VERSION 5.8 ;
BUSBITCHARS "[]" ;
DIVIDERCHAR "/" ;
UNITS
    DATABASE MICRONS 1000 ;
END UNITS

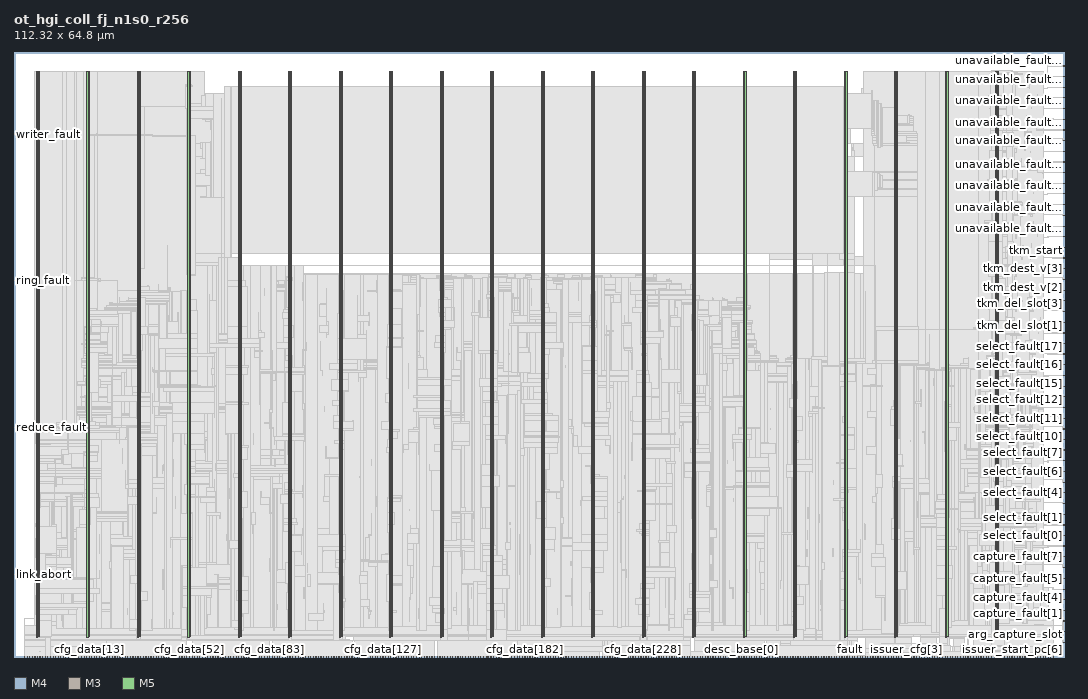
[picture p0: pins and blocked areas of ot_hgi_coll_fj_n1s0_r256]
MACRO ot_hgi_coll_fj_n1s0_r256
  FOREIGN ot_hgi_coll_fj_n1s0_r256 0 0 ;
  CLASS BLOCK ;
  SIZE 112.32 BY 64.8 ;
  PIN arg_capture_slot
    DIRECTION INPUT ;
    USE SIGNAL ;
    PORT
      LAYER M4 ;
        RECT  112.236 1.536 112.32 1.56 ;
    END
  END arg_capture_slot
  PIN capture_fault[0]
    DIRECTION INPUT ;
    USE SIGNAL ;
    PORT
      LAYER M4 ;
        RECT  112.236 2.688 112.32 2.712 ;
    END
  END capture_fault[0]
  PIN capture_fault[1]
    DIRECTION INPUT ;
    USE SIGNAL ;
    PORT
      LAYER M4 ;
        RECT  112.236 3.84 112.32 3.864 ;
    END
  END capture_fault[1]
  PIN capture_fault[2]
    DIRECTION INPUT ;
    USE SIGNAL ;
    PORT
      LAYER M4 ;
        RECT  112.236 4.992 112.32 5.016 ;
    END
  END capture_fault[2]
  PIN capture_fault[3]
    DIRECTION INPUT ;
    USE SIGNAL ;
    PORT
      LAYER M4 ;
        RECT  112.236 6.144 112.32 6.168 ;
    END
  END capture_fault[3]
  PIN capture_fault[4]
    DIRECTION INPUT ;
    USE SIGNAL ;
    PORT
      LAYER M4 ;
        RECT  112.236 7.248 112.32 7.272 ;
    END
  END capture_fault[4]
  PIN capture_fault[5]
    DIRECTION INPUT ;
    USE SIGNAL ;
    PORT
      LAYER M4 ;
        RECT  112.236 8.4 112.32 8.424 ;
    END
  END capture_fault[5]
  PIN capture_fault[6]
    DIRECTION INPUT ;
    USE SIGNAL ;
    PORT
      LAYER M4 ;
        RECT  112.236 9.552 112.32 9.576 ;
    END
  END capture_fault[6]
  PIN capture_fault[7]
    DIRECTION INPUT ;
    USE SIGNAL ;
    PORT
      LAYER M4 ;
        RECT  112.236 10.704 112.32 10.728 ;
    END
  END capture_fault[7]
  PIN cfg_addr[0]
    DIRECTION INPUT ;
    USE SIGNAL ;
    PORT
      LAYER M3 ;
        RECT  1.116 0 1.134 0.038 ;
    END
  END cfg_addr[0]
  PIN cfg_addr[10]
    DIRECTION INPUT ;
    USE SIGNAL ;
    PORT
      LAYER M3 ;
        RECT  3.888 0 3.906 0.038 ;
    END
  END cfg_addr[10]
  PIN cfg_addr[11]
    DIRECTION INPUT ;
    USE SIGNAL ;
    PORT
      LAYER M3 ;
        RECT  4.176 0 4.194 0.038 ;
    END
  END cfg_addr[11]
  PIN cfg_addr[1]
    DIRECTION INPUT ;
    USE SIGNAL ;
    PORT
      LAYER M3 ;
        RECT  1.404 0 1.422 0.038 ;
    END
  END cfg_addr[1]
  PIN cfg_addr[2]
    DIRECTION INPUT ;
    USE SIGNAL ;
    PORT
      LAYER M3 ;
        RECT  1.692 0 1.71 0.038 ;
    END
  END cfg_addr[2]
  PIN cfg_addr[3]
    DIRECTION INPUT ;
    USE SIGNAL ;
    PORT
      LAYER M3 ;
        RECT  1.944 0 1.962 0.038 ;
    END
  END cfg_addr[3]
  PIN cfg_addr[4]
    DIRECTION INPUT ;
    USE SIGNAL ;
    PORT
      LAYER M3 ;
        RECT  2.232 0 2.25 0.038 ;
    END
  END cfg_addr[4]
  PIN cfg_addr[5]
    DIRECTION INPUT ;
    USE SIGNAL ;
    PORT
      LAYER M3 ;
        RECT  2.52 0 2.538 0.038 ;
    END
  END cfg_addr[5]
  PIN cfg_addr[6]
    DIRECTION INPUT ;
    USE SIGNAL ;
    PORT
      LAYER M3 ;
        RECT  2.772 0 2.79 0.038 ;
    END
  END cfg_addr[6]
  PIN cfg_addr[7]
    DIRECTION INPUT ;
    USE SIGNAL ;
    PORT
      LAYER M3 ;
        RECT  3.06 0 3.078 0.038 ;
    END
  END cfg_addr[7]
  PIN cfg_addr[8]
    DIRECTION INPUT ;
    USE SIGNAL ;
    PORT
      LAYER M3 ;
        RECT  3.348 0 3.366 0.038 ;
    END
  END cfg_addr[8]
  PIN cfg_addr[9]
    DIRECTION INPUT ;
    USE SIGNAL ;
    PORT
      LAYER M3 ;
        RECT  3.6 0 3.618 0.038 ;
    END
  END cfg_addr[9]
  PIN cfg_data[0]
    DIRECTION INPUT ;
    USE SIGNAL ;
    PORT
      LAYER M3 ;
        RECT  4.428 0 4.446 0.038 ;
    END
  END cfg_data[0]
  PIN cfg_data[100]
    DIRECTION INPUT ;
    USE SIGNAL ;
    PORT
      LAYER M5 ;
        RECT  32.016 0 32.04 0.084 ;
    END
  END cfg_data[100]
  PIN cfg_data[101]
    DIRECTION INPUT ;
    USE SIGNAL ;
    PORT
      LAYER M5 ;
        RECT  32.304 0 32.328 0.084 ;
    END
  END cfg_data[101]
  PIN cfg_data[102]
    DIRECTION INPUT ;
    USE SIGNAL ;
    PORT
      LAYER M5 ;
        RECT  32.544 0 32.568 0.084 ;
    END
  END cfg_data[102]
  PIN cfg_data[103]
    DIRECTION INPUT ;
    USE SIGNAL ;
    PORT
      LAYER M5 ;
        RECT  32.832 0 32.856 0.084 ;
    END
  END cfg_data[103]
  PIN cfg_data[104]
    DIRECTION INPUT ;
    USE SIGNAL ;
    PORT
      LAYER M5 ;
        RECT  33.12 0 33.144 0.084 ;
    END
  END cfg_data[104]
  PIN cfg_data[105]
    DIRECTION INPUT ;
    USE SIGNAL ;
    PORT
      LAYER M5 ;
        RECT  33.408 0 33.432 0.084 ;
    END
  END cfg_data[105]
  PIN cfg_data[106]
    DIRECTION INPUT ;
    USE SIGNAL ;
    PORT
      LAYER M5 ;
        RECT  33.648 0 33.672 0.084 ;
    END
  END cfg_data[106]
  PIN cfg_data[107]
    DIRECTION INPUT ;
    USE SIGNAL ;
    PORT
      LAYER M5 ;
        RECT  33.936 0 33.96 0.084 ;
    END
  END cfg_data[107]
  PIN cfg_data[108]
    DIRECTION INPUT ;
    USE SIGNAL ;
    PORT
      LAYER M5 ;
        RECT  34.224 0 34.248 0.084 ;
    END
  END cfg_data[108]
  PIN cfg_data[109]
    DIRECTION INPUT ;
    USE SIGNAL ;
    PORT
      LAYER M5 ;
        RECT  34.512 0 34.536 0.084 ;
    END
  END cfg_data[109]
  PIN cfg_data[10]
    DIRECTION INPUT ;
    USE SIGNAL ;
    PORT
      LAYER M3 ;
        RECT  7.2 0 7.218 0.038 ;
    END
  END cfg_data[10]
  PIN cfg_data[110]
    DIRECTION INPUT ;
    USE SIGNAL ;
    PORT
      LAYER M5 ;
        RECT  34.752 0 34.776 0.084 ;
    END
  END cfg_data[110]
  PIN cfg_data[111]
    DIRECTION INPUT ;
    USE SIGNAL ;
    PORT
      LAYER M5 ;
        RECT  35.04 0 35.064 0.084 ;
    END
  END cfg_data[111]
  PIN cfg_data[112]
    DIRECTION INPUT ;
    USE SIGNAL ;
    PORT
      LAYER M5 ;
        RECT  35.328 0 35.352 0.084 ;
    END
  END cfg_data[112]
  PIN cfg_data[113]
    DIRECTION INPUT ;
    USE SIGNAL ;
    PORT
      LAYER M5 ;
        RECT  35.616 0 35.64 0.084 ;
    END
  END cfg_data[113]
  PIN cfg_data[114]
    DIRECTION INPUT ;
    USE SIGNAL ;
    PORT
      LAYER M5 ;
        RECT  35.856 0 35.88 0.084 ;
    END
  END cfg_data[114]
  PIN cfg_data[115]
    DIRECTION INPUT ;
    USE SIGNAL ;
    PORT
      LAYER M5 ;
        RECT  36.144 0 36.168 0.084 ;
    END
  END cfg_data[115]
  PIN cfg_data[116]
    DIRECTION INPUT ;
    USE SIGNAL ;
    PORT
      LAYER M3 ;
        RECT  36.432 0 36.45 0.038 ;
    END
  END cfg_data[116]
  PIN cfg_data[117]
    DIRECTION INPUT ;
    USE SIGNAL ;
    PORT
      LAYER M3 ;
        RECT  36.72 0 36.738 0.038 ;
    END
  END cfg_data[117]
  PIN cfg_data[118]
    DIRECTION INPUT ;
    USE SIGNAL ;
    PORT
      LAYER M3 ;
        RECT  36.972 0 36.99 0.038 ;
    END
  END cfg_data[118]
  PIN cfg_data[119]
    DIRECTION INPUT ;
    USE SIGNAL ;
    PORT
      LAYER M3 ;
        RECT  37.26 0 37.278 0.038 ;
    END
  END cfg_data[119]
  PIN cfg_data[11]
    DIRECTION INPUT ;
    USE SIGNAL ;
    PORT
      LAYER M3 ;
        RECT  7.488 0 7.506 0.038 ;
    END
  END cfg_data[11]
  PIN cfg_data[120]
    DIRECTION INPUT ;
    USE SIGNAL ;
    PORT
      LAYER M3 ;
        RECT  37.548 0 37.566 0.038 ;
    END
  END cfg_data[120]
  PIN cfg_data[121]
    DIRECTION INPUT ;
    USE SIGNAL ;
    PORT
      LAYER M3 ;
        RECT  37.8 0 37.818 0.038 ;
    END
  END cfg_data[121]
  PIN cfg_data[122]
    DIRECTION INPUT ;
    USE SIGNAL ;
    PORT
      LAYER M3 ;
        RECT  38.088 0 38.106 0.038 ;
    END
  END cfg_data[122]
  PIN cfg_data[123]
    DIRECTION INPUT ;
    USE SIGNAL ;
    PORT
      LAYER M3 ;
        RECT  38.376 0 38.394 0.038 ;
    END
  END cfg_data[123]
  PIN cfg_data[124]
    DIRECTION INPUT ;
    USE SIGNAL ;
    PORT
      LAYER M3 ;
        RECT  38.628 0 38.646 0.038 ;
    END
  END cfg_data[124]
  PIN cfg_data[125]
    DIRECTION INPUT ;
    USE SIGNAL ;
    PORT
      LAYER M3 ;
        RECT  38.916 0 38.934 0.038 ;
    END
  END cfg_data[125]
  PIN cfg_data[126]
    DIRECTION INPUT ;
    USE SIGNAL ;
    PORT
      LAYER M3 ;
        RECT  39.204 0 39.222 0.038 ;
    END
  END cfg_data[126]
  PIN cfg_data[127]
    DIRECTION INPUT ;
    USE SIGNAL ;
    PORT
      LAYER M3 ;
        RECT  39.456 0 39.474 0.038 ;
    END
  END cfg_data[127]
  PIN cfg_data[128]
    DIRECTION INPUT ;
    USE SIGNAL ;
    PORT
      LAYER M3 ;
        RECT  39.744 0 39.762 0.038 ;
    END
  END cfg_data[128]
  PIN cfg_data[129]
    DIRECTION INPUT ;
    USE SIGNAL ;
    PORT
      LAYER M3 ;
        RECT  40.032 0 40.05 0.038 ;
    END
  END cfg_data[129]
  PIN cfg_data[12]
    DIRECTION INPUT ;
    USE SIGNAL ;
    PORT
      LAYER M3 ;
        RECT  7.74 0 7.758 0.038 ;
    END
  END cfg_data[12]
  PIN cfg_data[130]
    DIRECTION INPUT ;
    USE SIGNAL ;
    PORT
      LAYER M3 ;
        RECT  40.284 0 40.302 0.038 ;
    END
  END cfg_data[130]
  PIN cfg_data[131]
    DIRECTION INPUT ;
    USE SIGNAL ;
    PORT
      LAYER M3 ;
        RECT  40.572 0 40.59 0.038 ;
    END
  END cfg_data[131]
  PIN cfg_data[132]
    DIRECTION INPUT ;
    USE SIGNAL ;
    PORT
      LAYER M3 ;
        RECT  40.86 0 40.878 0.038 ;
    END
  END cfg_data[132]
  PIN cfg_data[133]
    DIRECTION INPUT ;
    USE SIGNAL ;
    PORT
      LAYER M3 ;
        RECT  41.112 0 41.13 0.038 ;
    END
  END cfg_data[133]
  PIN cfg_data[134]
    DIRECTION INPUT ;
    USE SIGNAL ;
    PORT
      LAYER M3 ;
        RECT  41.4 0 41.418 0.038 ;
    END
  END cfg_data[134]
  PIN cfg_data[135]
    DIRECTION INPUT ;
    USE SIGNAL ;
    PORT
      LAYER M3 ;
        RECT  41.688 0 41.706 0.038 ;
    END
  END cfg_data[135]
  PIN cfg_data[136]
    DIRECTION INPUT ;
    USE SIGNAL ;
    PORT
      LAYER M3 ;
        RECT  41.94 0 41.958 0.038 ;
    END
  END cfg_data[136]
  PIN cfg_data[137]
    DIRECTION INPUT ;
    USE SIGNAL ;
    PORT
      LAYER M3 ;
        RECT  42.228 0 42.246 0.038 ;
    END
  END cfg_data[137]
  PIN cfg_data[138]
    DIRECTION INPUT ;
    USE SIGNAL ;
    PORT
      LAYER M3 ;
        RECT  42.516 0 42.534 0.038 ;
    END
  END cfg_data[138]
  PIN cfg_data[139]
    DIRECTION INPUT ;
    USE SIGNAL ;
    PORT
      LAYER M3 ;
        RECT  42.768 0 42.786 0.038 ;
    END
  END cfg_data[139]
  PIN cfg_data[13]
    DIRECTION INPUT ;
    USE SIGNAL ;
    PORT
      LAYER M3 ;
        RECT  8.028 0 8.046 0.038 ;
    END
  END cfg_data[13]
  PIN cfg_data[140]
    DIRECTION INPUT ;
    USE SIGNAL ;
    PORT
      LAYER M3 ;
        RECT  43.056 0 43.074 0.038 ;
    END
  END cfg_data[140]
  PIN cfg_data[141]
    DIRECTION INPUT ;
    USE SIGNAL ;
    PORT
      LAYER M3 ;
        RECT  43.344 0 43.362 0.038 ;
    END
  END cfg_data[141]
  PIN cfg_data[142]
    DIRECTION INPUT ;
    USE SIGNAL ;
    PORT
      LAYER M3 ;
        RECT  43.596 0 43.614 0.038 ;
    END
  END cfg_data[142]
  PIN cfg_data[143]
    DIRECTION INPUT ;
    USE SIGNAL ;
    PORT
      LAYER M3 ;
        RECT  43.884 0 43.902 0.038 ;
    END
  END cfg_data[143]
  PIN cfg_data[144]
    DIRECTION INPUT ;
    USE SIGNAL ;
    PORT
      LAYER M3 ;
        RECT  44.172 0 44.19 0.038 ;
    END
  END cfg_data[144]
  PIN cfg_data[145]
    DIRECTION INPUT ;
    USE SIGNAL ;
    PORT
      LAYER M3 ;
        RECT  44.424 0 44.442 0.038 ;
    END
  END cfg_data[145]
  PIN cfg_data[146]
    DIRECTION INPUT ;
    USE SIGNAL ;
    PORT
      LAYER M3 ;
        RECT  44.712 0 44.73 0.038 ;
    END
  END cfg_data[146]
  PIN cfg_data[147]
    DIRECTION INPUT ;
    USE SIGNAL ;
    PORT
      LAYER M3 ;
        RECT  44.964 0 44.982 0.038 ;
    END
  END cfg_data[147]
  PIN cfg_data[148]
    DIRECTION INPUT ;
    USE SIGNAL ;
    PORT
      LAYER M5 ;
        RECT  45.264 0 45.288 0.084 ;
    END
  END cfg_data[148]
  PIN cfg_data[149]
    DIRECTION INPUT ;
    USE SIGNAL ;
    PORT
      LAYER M5 ;
        RECT  45.552 0 45.576 0.084 ;
    END
  END cfg_data[149]
  PIN cfg_data[14]
    DIRECTION INPUT ;
    USE SIGNAL ;
    PORT
      LAYER M3 ;
        RECT  8.316 0 8.334 0.038 ;
    END
  END cfg_data[14]
  PIN cfg_data[150]
    DIRECTION INPUT ;
    USE SIGNAL ;
    PORT
      LAYER M5 ;
        RECT  45.792 0 45.816 0.084 ;
    END
  END cfg_data[150]
  PIN cfg_data[151]
    DIRECTION INPUT ;
    USE SIGNAL ;
    PORT
      LAYER M5 ;
        RECT  46.08 0 46.104 0.084 ;
    END
  END cfg_data[151]
  PIN cfg_data[152]
    DIRECTION INPUT ;
    USE SIGNAL ;
    PORT
      LAYER M5 ;
        RECT  46.368 0 46.392 0.084 ;
    END
  END cfg_data[152]
  PIN cfg_data[153]
    DIRECTION INPUT ;
    USE SIGNAL ;
    PORT
      LAYER M5 ;
        RECT  46.656 0 46.68 0.084 ;
    END
  END cfg_data[153]
  PIN cfg_data[154]
    DIRECTION INPUT ;
    USE SIGNAL ;
    PORT
      LAYER M5 ;
        RECT  46.896 0 46.92 0.084 ;
    END
  END cfg_data[154]
  PIN cfg_data[155]
    DIRECTION INPUT ;
    USE SIGNAL ;
    PORT
      LAYER M5 ;
        RECT  47.184 0 47.208 0.084 ;
    END
  END cfg_data[155]
  PIN cfg_data[156]
    DIRECTION INPUT ;
    USE SIGNAL ;
    PORT
      LAYER M5 ;
        RECT  47.472 0 47.496 0.084 ;
    END
  END cfg_data[156]
  PIN cfg_data[157]
    DIRECTION INPUT ;
    USE SIGNAL ;
    PORT
      LAYER M5 ;
        RECT  47.76 0 47.784 0.084 ;
    END
  END cfg_data[157]
  PIN cfg_data[158]
    DIRECTION INPUT ;
    USE SIGNAL ;
    PORT
      LAYER M5 ;
        RECT  48 0 48.024 0.084 ;
    END
  END cfg_data[158]
  PIN cfg_data[159]
    DIRECTION INPUT ;
    USE SIGNAL ;
    PORT
      LAYER M5 ;
        RECT  48.288 0 48.312 0.084 ;
    END
  END cfg_data[159]
  PIN cfg_data[15]
    DIRECTION INPUT ;
    USE SIGNAL ;
    PORT
      LAYER M3 ;
        RECT  8.568 0 8.586 0.038 ;
    END
  END cfg_data[15]
  PIN cfg_data[160]
    DIRECTION INPUT ;
    USE SIGNAL ;
    PORT
      LAYER M5 ;
        RECT  48.576 0 48.6 0.084 ;
    END
  END cfg_data[160]
  PIN cfg_data[161]
    DIRECTION INPUT ;
    USE SIGNAL ;
    PORT
      LAYER M5 ;
        RECT  48.816 0 48.84 0.084 ;
    END
  END cfg_data[161]
  PIN cfg_data[162]
    DIRECTION INPUT ;
    USE SIGNAL ;
    PORT
      LAYER M5 ;
        RECT  49.104 0 49.128 0.084 ;
    END
  END cfg_data[162]
  PIN cfg_data[163]
    DIRECTION INPUT ;
    USE SIGNAL ;
    PORT
      LAYER M5 ;
        RECT  49.392 0 49.416 0.084 ;
    END
  END cfg_data[163]
  PIN cfg_data[164]
    DIRECTION INPUT ;
    USE SIGNAL ;
    PORT
      LAYER M5 ;
        RECT  49.68 0 49.704 0.084 ;
    END
  END cfg_data[164]
  PIN cfg_data[165]
    DIRECTION INPUT ;
    USE SIGNAL ;
    PORT
      LAYER M5 ;
        RECT  49.92 0 49.944 0.084 ;
    END
  END cfg_data[165]
  PIN cfg_data[166]
    DIRECTION INPUT ;
    USE SIGNAL ;
    PORT
      LAYER M5 ;
        RECT  50.208 0 50.232 0.084 ;
    END
  END cfg_data[166]
  PIN cfg_data[167]
    DIRECTION INPUT ;
    USE SIGNAL ;
    PORT
      LAYER M5 ;
        RECT  50.496 0 50.52 0.084 ;
    END
  END cfg_data[167]
  PIN cfg_data[168]
    DIRECTION INPUT ;
    USE SIGNAL ;
    PORT
      LAYER M5 ;
        RECT  50.784 0 50.808 0.084 ;
    END
  END cfg_data[168]
  PIN cfg_data[169]
    DIRECTION INPUT ;
    USE SIGNAL ;
    PORT
      LAYER M5 ;
        RECT  51.024 0 51.048 0.084 ;
    END
  END cfg_data[169]
  PIN cfg_data[16]
    DIRECTION INPUT ;
    USE SIGNAL ;
    PORT
      LAYER M3 ;
        RECT  8.856 0 8.874 0.038 ;
    END
  END cfg_data[16]
  PIN cfg_data[170]
    DIRECTION INPUT ;
    USE SIGNAL ;
    PORT
      LAYER M5 ;
        RECT  51.312 0 51.336 0.084 ;
    END
  END cfg_data[170]
  PIN cfg_data[171]
    DIRECTION INPUT ;
    USE SIGNAL ;
    PORT
      LAYER M5 ;
        RECT  51.6 0 51.624 0.084 ;
    END
  END cfg_data[171]
  PIN cfg_data[172]
    DIRECTION INPUT ;
    USE SIGNAL ;
    PORT
      LAYER M5 ;
        RECT  51.888 0 51.912 0.084 ;
    END
  END cfg_data[172]
  PIN cfg_data[173]
    DIRECTION INPUT ;
    USE SIGNAL ;
    PORT
      LAYER M5 ;
        RECT  52.128 0 52.152 0.084 ;
    END
  END cfg_data[173]
  PIN cfg_data[174]
    DIRECTION INPUT ;
    USE SIGNAL ;
    PORT
      LAYER M5 ;
        RECT  52.416 0 52.44 0.084 ;
    END
  END cfg_data[174]
  PIN cfg_data[175]
    DIRECTION INPUT ;
    USE SIGNAL ;
    PORT
      LAYER M5 ;
        RECT  52.704 0 52.728 0.084 ;
    END
  END cfg_data[175]
  PIN cfg_data[176]
    DIRECTION INPUT ;
    USE SIGNAL ;
    PORT
      LAYER M5 ;
        RECT  52.992 0 53.016 0.084 ;
    END
  END cfg_data[176]
  PIN cfg_data[177]
    DIRECTION INPUT ;
    USE SIGNAL ;
    PORT
      LAYER M5 ;
        RECT  53.232 0 53.256 0.084 ;
    END
  END cfg_data[177]
  PIN cfg_data[178]
    DIRECTION INPUT ;
    USE SIGNAL ;
    PORT
      LAYER M5 ;
        RECT  53.52 0 53.544 0.084 ;
    END
  END cfg_data[178]
  PIN cfg_data[179]
    DIRECTION INPUT ;
    USE SIGNAL ;
    PORT
      LAYER M5 ;
        RECT  53.808 0 53.832 0.084 ;
    END
  END cfg_data[179]
  PIN cfg_data[17]
    DIRECTION INPUT ;
    USE SIGNAL ;
    PORT
      LAYER M3 ;
        RECT  9.144 0 9.162 0.038 ;
    END
  END cfg_data[17]
  PIN cfg_data[180]
    DIRECTION INPUT ;
    USE SIGNAL ;
    PORT
      LAYER M3 ;
        RECT  54.072 0 54.09 0.038 ;
    END
  END cfg_data[180]
  PIN cfg_data[181]
    DIRECTION INPUT ;
    USE SIGNAL ;
    PORT
      LAYER M3 ;
        RECT  54.36 0 54.378 0.038 ;
    END
  END cfg_data[181]
  PIN cfg_data[182]
    DIRECTION INPUT ;
    USE SIGNAL ;
    PORT
      LAYER M3 ;
        RECT  54.648 0 54.666 0.038 ;
    END
  END cfg_data[182]
  PIN cfg_data[183]
    DIRECTION INPUT ;
    USE SIGNAL ;
    PORT
      LAYER M3 ;
        RECT  54.9 0 54.918 0.038 ;
    END
  END cfg_data[183]
  PIN cfg_data[184]
    DIRECTION INPUT ;
    USE SIGNAL ;
    PORT
      LAYER M3 ;
        RECT  55.188 0 55.206 0.038 ;
    END
  END cfg_data[184]
  PIN cfg_data[185]
    DIRECTION INPUT ;
    USE SIGNAL ;
    PORT
      LAYER M3 ;
        RECT  55.476 0 55.494 0.038 ;
    END
  END cfg_data[185]
  PIN cfg_data[186]
    DIRECTION INPUT ;
    USE SIGNAL ;
    PORT
      LAYER M3 ;
        RECT  55.728 0 55.746 0.038 ;
    END
  END cfg_data[186]
  PIN cfg_data[187]
    DIRECTION INPUT ;
    USE SIGNAL ;
    PORT
      LAYER M3 ;
        RECT  56.016 0 56.034 0.038 ;
    END
  END cfg_data[187]
  PIN cfg_data[188]
    DIRECTION INPUT ;
    USE SIGNAL ;
    PORT
      LAYER M3 ;
        RECT  56.304 0 56.322 0.038 ;
    END
  END cfg_data[188]
  PIN cfg_data[189]
    DIRECTION INPUT ;
    USE SIGNAL ;
    PORT
      LAYER M3 ;
        RECT  56.556 0 56.574 0.038 ;
    END
  END cfg_data[189]
  PIN cfg_data[18]
    DIRECTION INPUT ;
    USE SIGNAL ;
    PORT
      LAYER M3 ;
        RECT  9.396 0 9.414 0.038 ;
    END
  END cfg_data[18]
  PIN cfg_data[190]
    DIRECTION INPUT ;
    USE SIGNAL ;
    PORT
      LAYER M3 ;
        RECT  56.844 0 56.862 0.038 ;
    END
  END cfg_data[190]
  PIN cfg_data[191]
    DIRECTION INPUT ;
    USE SIGNAL ;
    PORT
      LAYER M3 ;
        RECT  57.132 0 57.15 0.038 ;
    END
  END cfg_data[191]
  PIN cfg_data[192]
    DIRECTION INPUT ;
    USE SIGNAL ;
    PORT
      LAYER M3 ;
        RECT  57.384 0 57.402 0.038 ;
    END
  END cfg_data[192]
  PIN cfg_data[193]
    DIRECTION INPUT ;
    USE SIGNAL ;
    PORT
      LAYER M3 ;
        RECT  57.672 0 57.69 0.038 ;
    END
  END cfg_data[193]
  PIN cfg_data[194]
    DIRECTION INPUT ;
    USE SIGNAL ;
    PORT
      LAYER M3 ;
        RECT  57.96 0 57.978 0.038 ;
    END
  END cfg_data[194]
  PIN cfg_data[195]
    DIRECTION INPUT ;
    USE SIGNAL ;
    PORT
      LAYER M3 ;
        RECT  58.212 0 58.23 0.038 ;
    END
  END cfg_data[195]
  PIN cfg_data[196]
    DIRECTION INPUT ;
    USE SIGNAL ;
    PORT
      LAYER M3 ;
        RECT  58.5 0 58.518 0.038 ;
    END
  END cfg_data[196]
  PIN cfg_data[197]
    DIRECTION INPUT ;
    USE SIGNAL ;
    PORT
      LAYER M3 ;
        RECT  58.788 0 58.806 0.038 ;
    END
  END cfg_data[197]
  PIN cfg_data[198]
    DIRECTION INPUT ;
    USE SIGNAL ;
    PORT
      LAYER M3 ;
        RECT  59.04 0 59.058 0.038 ;
    END
  END cfg_data[198]
  PIN cfg_data[199]
    DIRECTION INPUT ;
    USE SIGNAL ;
    PORT
      LAYER M3 ;
        RECT  59.328 0 59.346 0.038 ;
    END
  END cfg_data[199]
  PIN cfg_data[19]
    DIRECTION INPUT ;
    USE SIGNAL ;
    PORT
      LAYER M3 ;
        RECT  9.684 0 9.702 0.038 ;
    END
  END cfg_data[19]
  PIN cfg_data[1]
    DIRECTION INPUT ;
    USE SIGNAL ;
    PORT
      LAYER M3 ;
        RECT  4.716 0 4.734 0.038 ;
    END
  END cfg_data[1]
  PIN cfg_data[200]
    DIRECTION INPUT ;
    USE SIGNAL ;
    PORT
      LAYER M3 ;
        RECT  59.616 0 59.634 0.038 ;
    END
  END cfg_data[200]
  PIN cfg_data[201]
    DIRECTION INPUT ;
    USE SIGNAL ;
    PORT
      LAYER M3 ;
        RECT  59.868 0 59.886 0.038 ;
    END
  END cfg_data[201]
  PIN cfg_data[202]
    DIRECTION INPUT ;
    USE SIGNAL ;
    PORT
      LAYER M3 ;
        RECT  60.156 0 60.174 0.038 ;
    END
  END cfg_data[202]
  PIN cfg_data[203]
    DIRECTION INPUT ;
    USE SIGNAL ;
    PORT
      LAYER M3 ;
        RECT  60.444 0 60.462 0.038 ;
    END
  END cfg_data[203]
  PIN cfg_data[204]
    DIRECTION INPUT ;
    USE SIGNAL ;
    PORT
      LAYER M3 ;
        RECT  60.696 0 60.714 0.038 ;
    END
  END cfg_data[204]
  PIN cfg_data[205]
    DIRECTION INPUT ;
    USE SIGNAL ;
    PORT
      LAYER M3 ;
        RECT  60.984 0 61.002 0.038 ;
    END
  END cfg_data[205]
  PIN cfg_data[206]
    DIRECTION INPUT ;
    USE SIGNAL ;
    PORT
      LAYER M3 ;
        RECT  61.236 0 61.254 0.038 ;
    END
  END cfg_data[206]
  PIN cfg_data[207]
    DIRECTION INPUT ;
    USE SIGNAL ;
    PORT
      LAYER M3 ;
        RECT  61.524 0 61.542 0.038 ;
    END
  END cfg_data[207]
  PIN cfg_data[208]
    DIRECTION INPUT ;
    USE SIGNAL ;
    PORT
      LAYER M3 ;
        RECT  61.812 0 61.83 0.038 ;
    END
  END cfg_data[208]
  PIN cfg_data[209]
    DIRECTION INPUT ;
    USE SIGNAL ;
    PORT
      LAYER M3 ;
        RECT  62.064 0 62.082 0.038 ;
    END
  END cfg_data[209]
  PIN cfg_data[20]
    DIRECTION INPUT ;
    USE SIGNAL ;
    PORT
      LAYER M5 ;
        RECT  9.936 0 9.96 0.084 ;
    END
  END cfg_data[20]
  PIN cfg_data[210]
    DIRECTION INPUT ;
    USE SIGNAL ;
    PORT
      LAYER M3 ;
        RECT  62.352 0 62.37 0.038 ;
    END
  END cfg_data[210]
  PIN cfg_data[211]
    DIRECTION INPUT ;
    USE SIGNAL ;
    PORT
      LAYER M3 ;
        RECT  62.64 0 62.658 0.038 ;
    END
  END cfg_data[211]
  PIN cfg_data[212]
    DIRECTION INPUT ;
    USE SIGNAL ;
    PORT
      LAYER M5 ;
        RECT  62.928 0 62.952 0.084 ;
    END
  END cfg_data[212]
  PIN cfg_data[213]
    DIRECTION INPUT ;
    USE SIGNAL ;
    PORT
      LAYER M5 ;
        RECT  63.168 0 63.192 0.084 ;
    END
  END cfg_data[213]
  PIN cfg_data[214]
    DIRECTION INPUT ;
    USE SIGNAL ;
    PORT
      LAYER M5 ;
        RECT  63.456 0 63.48 0.084 ;
    END
  END cfg_data[214]
  PIN cfg_data[215]
    DIRECTION INPUT ;
    USE SIGNAL ;
    PORT
      LAYER M5 ;
        RECT  63.744 0 63.768 0.084 ;
    END
  END cfg_data[215]
  PIN cfg_data[216]
    DIRECTION INPUT ;
    USE SIGNAL ;
    PORT
      LAYER M5 ;
        RECT  64.032 0 64.056 0.084 ;
    END
  END cfg_data[216]
  PIN cfg_data[217]
    DIRECTION INPUT ;
    USE SIGNAL ;
    PORT
      LAYER M5 ;
        RECT  64.272 0 64.296 0.084 ;
    END
  END cfg_data[217]
  PIN cfg_data[218]
    DIRECTION INPUT ;
    USE SIGNAL ;
    PORT
      LAYER M5 ;
        RECT  64.56 0 64.584 0.084 ;
    END
  END cfg_data[218]
  PIN cfg_data[219]
    DIRECTION INPUT ;
    USE SIGNAL ;
    PORT
      LAYER M5 ;
        RECT  64.848 0 64.872 0.084 ;
    END
  END cfg_data[219]
  PIN cfg_data[21]
    DIRECTION INPUT ;
    USE SIGNAL ;
    PORT
      LAYER M5 ;
        RECT  10.224 0 10.248 0.084 ;
    END
  END cfg_data[21]
  PIN cfg_data[220]
    DIRECTION INPUT ;
    USE SIGNAL ;
    PORT
      LAYER M5 ;
        RECT  65.088 0 65.112 0.084 ;
    END
  END cfg_data[220]
  PIN cfg_data[221]
    DIRECTION INPUT ;
    USE SIGNAL ;
    PORT
      LAYER M5 ;
        RECT  65.376 0 65.4 0.084 ;
    END
  END cfg_data[221]
  PIN cfg_data[222]
    DIRECTION INPUT ;
    USE SIGNAL ;
    PORT
      LAYER M5 ;
        RECT  65.664 0 65.688 0.084 ;
    END
  END cfg_data[222]
  PIN cfg_data[223]
    DIRECTION INPUT ;
    USE SIGNAL ;
    PORT
      LAYER M5 ;
        RECT  65.952 0 65.976 0.084 ;
    END
  END cfg_data[223]
  PIN cfg_data[224]
    DIRECTION INPUT ;
    USE SIGNAL ;
    PORT
      LAYER M5 ;
        RECT  66.192 0 66.216 0.084 ;
    END
  END cfg_data[224]
  PIN cfg_data[225]
    DIRECTION INPUT ;
    USE SIGNAL ;
    PORT
      LAYER M5 ;
        RECT  66.48 0 66.504 0.084 ;
    END
  END cfg_data[225]
  PIN cfg_data[226]
    DIRECTION INPUT ;
    USE SIGNAL ;
    PORT
      LAYER M5 ;
        RECT  66.768 0 66.792 0.084 ;
    END
  END cfg_data[226]
  PIN cfg_data[227]
    DIRECTION INPUT ;
    USE SIGNAL ;
    PORT
      LAYER M5 ;
        RECT  67.056 0 67.08 0.084 ;
    END
  END cfg_data[227]
  PIN cfg_data[228]
    DIRECTION INPUT ;
    USE SIGNAL ;
    PORT
      LAYER M5 ;
        RECT  67.296 0 67.32 0.084 ;
    END
  END cfg_data[228]
  PIN cfg_data[229]
    DIRECTION INPUT ;
    USE SIGNAL ;
    PORT
      LAYER M5 ;
        RECT  67.584 0 67.608 0.084 ;
    END
  END cfg_data[229]
  PIN cfg_data[22]
    DIRECTION INPUT ;
    USE SIGNAL ;
    PORT
      LAYER M5 ;
        RECT  10.512 0 10.536 0.084 ;
    END
  END cfg_data[22]
  PIN cfg_data[230]
    DIRECTION INPUT ;
    USE SIGNAL ;
    PORT
      LAYER M5 ;
        RECT  67.872 0 67.896 0.084 ;
    END
  END cfg_data[230]
  PIN cfg_data[231]
    DIRECTION INPUT ;
    USE SIGNAL ;
    PORT
      LAYER M5 ;
        RECT  68.16 0 68.184 0.084 ;
    END
  END cfg_data[231]
  PIN cfg_data[232]
    DIRECTION INPUT ;
    USE SIGNAL ;
    PORT
      LAYER M5 ;
        RECT  68.4 0 68.424 0.084 ;
    END
  END cfg_data[232]
  PIN cfg_data[233]
    DIRECTION INPUT ;
    USE SIGNAL ;
    PORT
      LAYER M5 ;
        RECT  68.688 0 68.712 0.084 ;
    END
  END cfg_data[233]
  PIN cfg_data[234]
    DIRECTION INPUT ;
    USE SIGNAL ;
    PORT
      LAYER M5 ;
        RECT  68.976 0 69 0.084 ;
    END
  END cfg_data[234]
  PIN cfg_data[235]
    DIRECTION INPUT ;
    USE SIGNAL ;
    PORT
      LAYER M5 ;
        RECT  69.264 0 69.288 0.084 ;
    END
  END cfg_data[235]
  PIN cfg_data[236]
    DIRECTION INPUT ;
    USE SIGNAL ;
    PORT
      LAYER M5 ;
        RECT  69.504 0 69.528 0.084 ;
    END
  END cfg_data[236]
  PIN cfg_data[237]
    DIRECTION INPUT ;
    USE SIGNAL ;
    PORT
      LAYER M5 ;
        RECT  69.792 0 69.816 0.084 ;
    END
  END cfg_data[237]
  PIN cfg_data[238]
    DIRECTION INPUT ;
    USE SIGNAL ;
    PORT
      LAYER M5 ;
        RECT  70.08 0 70.104 0.084 ;
    END
  END cfg_data[238]
  PIN cfg_data[239]
    DIRECTION INPUT ;
    USE SIGNAL ;
    PORT
      LAYER M5 ;
        RECT  70.368 0 70.392 0.084 ;
    END
  END cfg_data[239]
  PIN cfg_data[23]
    DIRECTION INPUT ;
    USE SIGNAL ;
    PORT
      LAYER M5 ;
        RECT  10.8 0 10.824 0.084 ;
    END
  END cfg_data[23]
  PIN cfg_data[240]
    DIRECTION INPUT ;
    USE SIGNAL ;
    PORT
      LAYER M5 ;
        RECT  70.608 0 70.632 0.084 ;
    END
  END cfg_data[240]
  PIN cfg_data[241]
    DIRECTION INPUT ;
    USE SIGNAL ;
    PORT
      LAYER M5 ;
        RECT  70.896 0 70.92 0.084 ;
    END
  END cfg_data[241]
  PIN cfg_data[242]
    DIRECTION INPUT ;
    USE SIGNAL ;
    PORT
      LAYER M5 ;
        RECT  71.184 0 71.208 0.084 ;
    END
  END cfg_data[242]
  PIN cfg_data[243]
    DIRECTION INPUT ;
    USE SIGNAL ;
    PORT
      LAYER M5 ;
        RECT  71.472 0 71.496 0.084 ;
    END
  END cfg_data[243]
  PIN cfg_data[244]
    DIRECTION INPUT ;
    USE SIGNAL ;
    PORT
      LAYER M3 ;
        RECT  71.748 0 71.766 0.038 ;
    END
  END cfg_data[244]
  PIN cfg_data[245]
    DIRECTION INPUT ;
    USE SIGNAL ;
    PORT
      LAYER M3 ;
        RECT  72 0 72.018 0.038 ;
    END
  END cfg_data[245]
  PIN cfg_data[246]
    DIRECTION INPUT ;
    USE SIGNAL ;
    PORT
      LAYER M3 ;
        RECT  72.288 0 72.306 0.038 ;
    END
  END cfg_data[246]
  PIN cfg_data[247]
    DIRECTION INPUT ;
    USE SIGNAL ;
    PORT
      LAYER M3 ;
        RECT  72.576 0 72.594 0.038 ;
    END
  END cfg_data[247]
  PIN cfg_data[248]
    DIRECTION INPUT ;
    USE SIGNAL ;
    PORT
      LAYER M3 ;
        RECT  72.828 0 72.846 0.038 ;
    END
  END cfg_data[248]
  PIN cfg_data[249]
    DIRECTION INPUT ;
    USE SIGNAL ;
    PORT
      LAYER M3 ;
        RECT  73.116 0 73.134 0.038 ;
    END
  END cfg_data[249]
  PIN cfg_data[24]
    DIRECTION INPUT ;
    USE SIGNAL ;
    PORT
      LAYER M5 ;
        RECT  11.04 0 11.064 0.084 ;
    END
  END cfg_data[24]
  PIN cfg_data[250]
    DIRECTION INPUT ;
    USE SIGNAL ;
    PORT
      LAYER M3 ;
        RECT  73.404 0 73.422 0.038 ;
    END
  END cfg_data[250]
  PIN cfg_data[251]
    DIRECTION INPUT ;
    USE SIGNAL ;
    PORT
      LAYER M3 ;
        RECT  73.656 0 73.674 0.038 ;
    END
  END cfg_data[251]
  PIN cfg_data[252]
    DIRECTION INPUT ;
    USE SIGNAL ;
    PORT
      LAYER M3 ;
        RECT  73.944 0 73.962 0.038 ;
    END
  END cfg_data[252]
  PIN cfg_data[253]
    DIRECTION INPUT ;
    USE SIGNAL ;
    PORT
      LAYER M3 ;
        RECT  74.232 0 74.25 0.038 ;
    END
  END cfg_data[253]
  PIN cfg_data[254]
    DIRECTION INPUT ;
    USE SIGNAL ;
    PORT
      LAYER M3 ;
        RECT  74.484 0 74.502 0.038 ;
    END
  END cfg_data[254]
  PIN cfg_data[255]
    DIRECTION INPUT ;
    USE SIGNAL ;
    PORT
      LAYER M3 ;
        RECT  74.772 0 74.79 0.038 ;
    END
  END cfg_data[255]
  PIN cfg_data[25]
    DIRECTION INPUT ;
    USE SIGNAL ;
    PORT
      LAYER M5 ;
        RECT  11.328 0 11.352 0.084 ;
    END
  END cfg_data[25]
  PIN cfg_data[26]
    DIRECTION INPUT ;
    USE SIGNAL ;
    PORT
      LAYER M5 ;
        RECT  11.616 0 11.64 0.084 ;
    END
  END cfg_data[26]
  PIN cfg_data[27]
    DIRECTION INPUT ;
    USE SIGNAL ;
    PORT
      LAYER M5 ;
        RECT  11.904 0 11.928 0.084 ;
    END
  END cfg_data[27]
  PIN cfg_data[28]
    DIRECTION INPUT ;
    USE SIGNAL ;
    PORT
      LAYER M5 ;
        RECT  12.144 0 12.168 0.084 ;
    END
  END cfg_data[28]
  PIN cfg_data[29]
    DIRECTION INPUT ;
    USE SIGNAL ;
    PORT
      LAYER M5 ;
        RECT  12.432 0 12.456 0.084 ;
    END
  END cfg_data[29]
  PIN cfg_data[2]
    DIRECTION INPUT ;
    USE SIGNAL ;
    PORT
      LAYER M3 ;
        RECT  5.004 0 5.022 0.038 ;
    END
  END cfg_data[2]
  PIN cfg_data[30]
    DIRECTION INPUT ;
    USE SIGNAL ;
    PORT
      LAYER M5 ;
        RECT  12.72 0 12.744 0.084 ;
    END
  END cfg_data[30]
  PIN cfg_data[31]
    DIRECTION INPUT ;
    USE SIGNAL ;
    PORT
      LAYER M5 ;
        RECT  13.008 0 13.032 0.084 ;
    END
  END cfg_data[31]
  PIN cfg_data[32]
    DIRECTION INPUT ;
    USE SIGNAL ;
    PORT
      LAYER M5 ;
        RECT  13.248 0 13.272 0.084 ;
    END
  END cfg_data[32]
  PIN cfg_data[33]
    DIRECTION INPUT ;
    USE SIGNAL ;
    PORT
      LAYER M5 ;
        RECT  13.536 0 13.56 0.084 ;
    END
  END cfg_data[33]
  PIN cfg_data[34]
    DIRECTION INPUT ;
    USE SIGNAL ;
    PORT
      LAYER M5 ;
        RECT  13.824 0 13.848 0.084 ;
    END
  END cfg_data[34]
  PIN cfg_data[35]
    DIRECTION INPUT ;
    USE SIGNAL ;
    PORT
      LAYER M5 ;
        RECT  14.112 0 14.136 0.084 ;
    END
  END cfg_data[35]
  PIN cfg_data[36]
    DIRECTION INPUT ;
    USE SIGNAL ;
    PORT
      LAYER M5 ;
        RECT  14.352 0 14.376 0.084 ;
    END
  END cfg_data[36]
  PIN cfg_data[37]
    DIRECTION INPUT ;
    USE SIGNAL ;
    PORT
      LAYER M5 ;
        RECT  14.64 0 14.664 0.084 ;
    END
  END cfg_data[37]
  PIN cfg_data[38]
    DIRECTION INPUT ;
    USE SIGNAL ;
    PORT
      LAYER M5 ;
        RECT  14.928 0 14.952 0.084 ;
    END
  END cfg_data[38]
  PIN cfg_data[39]
    DIRECTION INPUT ;
    USE SIGNAL ;
    PORT
      LAYER M5 ;
        RECT  15.216 0 15.24 0.084 ;
    END
  END cfg_data[39]
  PIN cfg_data[3]
    DIRECTION INPUT ;
    USE SIGNAL ;
    PORT
      LAYER M3 ;
        RECT  5.256 0 5.274 0.038 ;
    END
  END cfg_data[3]
  PIN cfg_data[40]
    DIRECTION INPUT ;
    USE SIGNAL ;
    PORT
      LAYER M5 ;
        RECT  15.456 0 15.48 0.084 ;
    END
  END cfg_data[40]
  PIN cfg_data[41]
    DIRECTION INPUT ;
    USE SIGNAL ;
    PORT
      LAYER M5 ;
        RECT  15.744 0 15.768 0.084 ;
    END
  END cfg_data[41]
  PIN cfg_data[42]
    DIRECTION INPUT ;
    USE SIGNAL ;
    PORT
      LAYER M5 ;
        RECT  16.032 0 16.056 0.084 ;
    END
  END cfg_data[42]
  PIN cfg_data[43]
    DIRECTION INPUT ;
    USE SIGNAL ;
    PORT
      LAYER M5 ;
        RECT  16.272 0 16.296 0.084 ;
    END
  END cfg_data[43]
  PIN cfg_data[44]
    DIRECTION INPUT ;
    USE SIGNAL ;
    PORT
      LAYER M5 ;
        RECT  16.56 0 16.584 0.084 ;
    END
  END cfg_data[44]
  PIN cfg_data[45]
    DIRECTION INPUT ;
    USE SIGNAL ;
    PORT
      LAYER M5 ;
        RECT  16.848 0 16.872 0.084 ;
    END
  END cfg_data[45]
  PIN cfg_data[46]
    DIRECTION INPUT ;
    USE SIGNAL ;
    PORT
      LAYER M5 ;
        RECT  17.136 0 17.16 0.084 ;
    END
  END cfg_data[46]
  PIN cfg_data[47]
    DIRECTION INPUT ;
    USE SIGNAL ;
    PORT
      LAYER M5 ;
        RECT  17.376 0 17.4 0.084 ;
    END
  END cfg_data[47]
  PIN cfg_data[48]
    DIRECTION INPUT ;
    USE SIGNAL ;
    PORT
      LAYER M5 ;
        RECT  17.664 0 17.688 0.084 ;
    END
  END cfg_data[48]
  PIN cfg_data[49]
    DIRECTION INPUT ;
    USE SIGNAL ;
    PORT
      LAYER M5 ;
        RECT  17.952 0 17.976 0.084 ;
    END
  END cfg_data[49]
  PIN cfg_data[4]
    DIRECTION INPUT ;
    USE SIGNAL ;
    PORT
      LAYER M3 ;
        RECT  5.544 0 5.562 0.038 ;
    END
  END cfg_data[4]
  PIN cfg_data[50]
    DIRECTION INPUT ;
    USE SIGNAL ;
    PORT
      LAYER M5 ;
        RECT  18.24 0 18.264 0.084 ;
    END
  END cfg_data[50]
  PIN cfg_data[51]
    DIRECTION INPUT ;
    USE SIGNAL ;
    PORT
      LAYER M5 ;
        RECT  18.48 0 18.504 0.084 ;
    END
  END cfg_data[51]
  PIN cfg_data[52]
    DIRECTION INPUT ;
    USE SIGNAL ;
    PORT
      LAYER M3 ;
        RECT  18.792 0 18.81 0.038 ;
    END
  END cfg_data[52]
  PIN cfg_data[53]
    DIRECTION INPUT ;
    USE SIGNAL ;
    PORT
      LAYER M3 ;
        RECT  19.044 0 19.062 0.038 ;
    END
  END cfg_data[53]
  PIN cfg_data[54]
    DIRECTION INPUT ;
    USE SIGNAL ;
    PORT
      LAYER M3 ;
        RECT  19.332 0 19.35 0.038 ;
    END
  END cfg_data[54]
  PIN cfg_data[55]
    DIRECTION INPUT ;
    USE SIGNAL ;
    PORT
      LAYER M3 ;
        RECT  19.62 0 19.638 0.038 ;
    END
  END cfg_data[55]
  PIN cfg_data[56]
    DIRECTION INPUT ;
    USE SIGNAL ;
    PORT
      LAYER M3 ;
        RECT  19.872 0 19.89 0.038 ;
    END
  END cfg_data[56]
  PIN cfg_data[57]
    DIRECTION INPUT ;
    USE SIGNAL ;
    PORT
      LAYER M3 ;
        RECT  20.16 0 20.178 0.038 ;
    END
  END cfg_data[57]
  PIN cfg_data[58]
    DIRECTION INPUT ;
    USE SIGNAL ;
    PORT
      LAYER M3 ;
        RECT  20.448 0 20.466 0.038 ;
    END
  END cfg_data[58]
  PIN cfg_data[59]
    DIRECTION INPUT ;
    USE SIGNAL ;
    PORT
      LAYER M3 ;
        RECT  20.7 0 20.718 0.038 ;
    END
  END cfg_data[59]
  PIN cfg_data[5]
    DIRECTION INPUT ;
    USE SIGNAL ;
    PORT
      LAYER M3 ;
        RECT  5.832 0 5.85 0.038 ;
    END
  END cfg_data[5]
  PIN cfg_data[60]
    DIRECTION INPUT ;
    USE SIGNAL ;
    PORT
      LAYER M3 ;
        RECT  20.988 0 21.006 0.038 ;
    END
  END cfg_data[60]
  PIN cfg_data[61]
    DIRECTION INPUT ;
    USE SIGNAL ;
    PORT
      LAYER M3 ;
        RECT  21.276 0 21.294 0.038 ;
    END
  END cfg_data[61]
  PIN cfg_data[62]
    DIRECTION INPUT ;
    USE SIGNAL ;
    PORT
      LAYER M3 ;
        RECT  21.528 0 21.546 0.038 ;
    END
  END cfg_data[62]
  PIN cfg_data[63]
    DIRECTION INPUT ;
    USE SIGNAL ;
    PORT
      LAYER M3 ;
        RECT  21.816 0 21.834 0.038 ;
    END
  END cfg_data[63]
  PIN cfg_data[64]
    DIRECTION INPUT ;
    USE SIGNAL ;
    PORT
      LAYER M3 ;
        RECT  22.104 0 22.122 0.038 ;
    END
  END cfg_data[64]
  PIN cfg_data[65]
    DIRECTION INPUT ;
    USE SIGNAL ;
    PORT
      LAYER M3 ;
        RECT  22.356 0 22.374 0.038 ;
    END
  END cfg_data[65]
  PIN cfg_data[66]
    DIRECTION INPUT ;
    USE SIGNAL ;
    PORT
      LAYER M3 ;
        RECT  22.644 0 22.662 0.038 ;
    END
  END cfg_data[66]
  PIN cfg_data[67]
    DIRECTION INPUT ;
    USE SIGNAL ;
    PORT
      LAYER M3 ;
        RECT  22.932 0 22.95 0.038 ;
    END
  END cfg_data[67]
  PIN cfg_data[68]
    DIRECTION INPUT ;
    USE SIGNAL ;
    PORT
      LAYER M3 ;
        RECT  23.184 0 23.202 0.038 ;
    END
  END cfg_data[68]
  PIN cfg_data[69]
    DIRECTION INPUT ;
    USE SIGNAL ;
    PORT
      LAYER M3 ;
        RECT  23.472 0 23.49 0.038 ;
    END
  END cfg_data[69]
  PIN cfg_data[6]
    DIRECTION INPUT ;
    USE SIGNAL ;
    PORT
      LAYER M3 ;
        RECT  6.084 0 6.102 0.038 ;
    END
  END cfg_data[6]
  PIN cfg_data[70]
    DIRECTION INPUT ;
    USE SIGNAL ;
    PORT
      LAYER M3 ;
        RECT  23.76 0 23.778 0.038 ;
    END
  END cfg_data[70]
  PIN cfg_data[71]
    DIRECTION INPUT ;
    USE SIGNAL ;
    PORT
      LAYER M3 ;
        RECT  24.012 0 24.03 0.038 ;
    END
  END cfg_data[71]
  PIN cfg_data[72]
    DIRECTION INPUT ;
    USE SIGNAL ;
    PORT
      LAYER M3 ;
        RECT  24.3 0 24.318 0.038 ;
    END
  END cfg_data[72]
  PIN cfg_data[73]
    DIRECTION INPUT ;
    USE SIGNAL ;
    PORT
      LAYER M3 ;
        RECT  24.588 0 24.606 0.038 ;
    END
  END cfg_data[73]
  PIN cfg_data[74]
    DIRECTION INPUT ;
    USE SIGNAL ;
    PORT
      LAYER M3 ;
        RECT  24.84 0 24.858 0.038 ;
    END
  END cfg_data[74]
  PIN cfg_data[75]
    DIRECTION INPUT ;
    USE SIGNAL ;
    PORT
      LAYER M3 ;
        RECT  25.128 0 25.146 0.038 ;
    END
  END cfg_data[75]
  PIN cfg_data[76]
    DIRECTION INPUT ;
    USE SIGNAL ;
    PORT
      LAYER M3 ;
        RECT  25.416 0 25.434 0.038 ;
    END
  END cfg_data[76]
  PIN cfg_data[77]
    DIRECTION INPUT ;
    USE SIGNAL ;
    PORT
      LAYER M3 ;
        RECT  25.668 0 25.686 0.038 ;
    END
  END cfg_data[77]
  PIN cfg_data[78]
    DIRECTION INPUT ;
    USE SIGNAL ;
    PORT
      LAYER M3 ;
        RECT  25.956 0 25.974 0.038 ;
    END
  END cfg_data[78]
  PIN cfg_data[79]
    DIRECTION INPUT ;
    USE SIGNAL ;
    PORT
      LAYER M3 ;
        RECT  26.244 0 26.262 0.038 ;
    END
  END cfg_data[79]
  PIN cfg_data[7]
    DIRECTION INPUT ;
    USE SIGNAL ;
    PORT
      LAYER M3 ;
        RECT  6.372 0 6.39 0.038 ;
    END
  END cfg_data[7]
  PIN cfg_data[80]
    DIRECTION INPUT ;
    USE SIGNAL ;
    PORT
      LAYER M3 ;
        RECT  26.496 0 26.514 0.038 ;
    END
  END cfg_data[80]
  PIN cfg_data[81]
    DIRECTION INPUT ;
    USE SIGNAL ;
    PORT
      LAYER M3 ;
        RECT  26.784 0 26.802 0.038 ;
    END
  END cfg_data[81]
  PIN cfg_data[82]
    DIRECTION INPUT ;
    USE SIGNAL ;
    PORT
      LAYER M3 ;
        RECT  27.072 0 27.09 0.038 ;
    END
  END cfg_data[82]
  PIN cfg_data[83]
    DIRECTION INPUT ;
    USE SIGNAL ;
    PORT
      LAYER M3 ;
        RECT  27.324 0 27.342 0.038 ;
    END
  END cfg_data[83]
  PIN cfg_data[84]
    DIRECTION INPUT ;
    USE SIGNAL ;
    PORT
      LAYER M5 ;
        RECT  27.6 0 27.624 0.084 ;
    END
  END cfg_data[84]
  PIN cfg_data[85]
    DIRECTION INPUT ;
    USE SIGNAL ;
    PORT
      LAYER M5 ;
        RECT  27.888 0 27.912 0.084 ;
    END
  END cfg_data[85]
  PIN cfg_data[86]
    DIRECTION INPUT ;
    USE SIGNAL ;
    PORT
      LAYER M5 ;
        RECT  28.176 0 28.2 0.084 ;
    END
  END cfg_data[86]
  PIN cfg_data[87]
    DIRECTION INPUT ;
    USE SIGNAL ;
    PORT
      LAYER M5 ;
        RECT  28.416 0 28.44 0.084 ;
    END
  END cfg_data[87]
  PIN cfg_data[88]
    DIRECTION INPUT ;
    USE SIGNAL ;
    PORT
      LAYER M5 ;
        RECT  28.704 0 28.728 0.084 ;
    END
  END cfg_data[88]
  PIN cfg_data[89]
    DIRECTION INPUT ;
    USE SIGNAL ;
    PORT
      LAYER M5 ;
        RECT  28.992 0 29.016 0.084 ;
    END
  END cfg_data[89]
  PIN cfg_data[8]
    DIRECTION INPUT ;
    USE SIGNAL ;
    PORT
      LAYER M3 ;
        RECT  6.66 0 6.678 0.038 ;
    END
  END cfg_data[8]
  PIN cfg_data[90]
    DIRECTION INPUT ;
    USE SIGNAL ;
    PORT
      LAYER M5 ;
        RECT  29.28 0 29.304 0.084 ;
    END
  END cfg_data[90]
  PIN cfg_data[91]
    DIRECTION INPUT ;
    USE SIGNAL ;
    PORT
      LAYER M5 ;
        RECT  29.52 0 29.544 0.084 ;
    END
  END cfg_data[91]
  PIN cfg_data[92]
    DIRECTION INPUT ;
    USE SIGNAL ;
    PORT
      LAYER M5 ;
        RECT  29.808 0 29.832 0.084 ;
    END
  END cfg_data[92]
  PIN cfg_data[93]
    DIRECTION INPUT ;
    USE SIGNAL ;
    PORT
      LAYER M5 ;
        RECT  30.096 0 30.12 0.084 ;
    END
  END cfg_data[93]
  PIN cfg_data[94]
    DIRECTION INPUT ;
    USE SIGNAL ;
    PORT
      LAYER M5 ;
        RECT  30.384 0 30.408 0.084 ;
    END
  END cfg_data[94]
  PIN cfg_data[95]
    DIRECTION INPUT ;
    USE SIGNAL ;
    PORT
      LAYER M5 ;
        RECT  30.624 0 30.648 0.084 ;
    END
  END cfg_data[95]
  PIN cfg_data[96]
    DIRECTION INPUT ;
    USE SIGNAL ;
    PORT
      LAYER M5 ;
        RECT  30.912 0 30.936 0.084 ;
    END
  END cfg_data[96]
  PIN cfg_data[97]
    DIRECTION INPUT ;
    USE SIGNAL ;
    PORT
      LAYER M5 ;
        RECT  31.2 0 31.224 0.084 ;
    END
  END cfg_data[97]
  PIN cfg_data[98]
    DIRECTION INPUT ;
    USE SIGNAL ;
    PORT
      LAYER M5 ;
        RECT  31.488 0 31.512 0.084 ;
    END
  END cfg_data[98]
  PIN cfg_data[99]
    DIRECTION INPUT ;
    USE SIGNAL ;
    PORT
      LAYER M5 ;
        RECT  31.728 0 31.752 0.084 ;
    END
  END cfg_data[99]
  PIN cfg_data[9]
    DIRECTION INPUT ;
    USE SIGNAL ;
    PORT
      LAYER M3 ;
        RECT  6.912 0 6.93 0.038 ;
    END
  END cfg_data[9]
  PIN cfg_target[0]
    DIRECTION INPUT ;
    USE SIGNAL ;
    PORT
      LAYER M3 ;
        RECT  75.06 0 75.078 0.038 ;
    END
  END cfg_target[0]
  PIN cfg_target[1]
    DIRECTION INPUT ;
    USE SIGNAL ;
    PORT
      LAYER M3 ;
        RECT  75.312 0 75.33 0.038 ;
    END
  END cfg_target[1]
  PIN cfg_target[2]
    DIRECTION INPUT ;
    USE SIGNAL ;
    PORT
      LAYER M3 ;
        RECT  75.6 0 75.618 0.038 ;
    END
  END cfg_target[2]
  PIN cfg_target[3]
    DIRECTION INPUT ;
    USE SIGNAL ;
    PORT
      LAYER M3 ;
        RECT  75.888 0 75.906 0.038 ;
    END
  END cfg_target[3]
  PIN cfg_target[4]
    DIRECTION INPUT ;
    USE SIGNAL ;
    PORT
      LAYER M3 ;
        RECT  76.14 0 76.158 0.038 ;
    END
  END cfg_target[4]
  PIN cfg_target[5]
    DIRECTION INPUT ;
    USE SIGNAL ;
    PORT
      LAYER M3 ;
        RECT  76.428 0 76.446 0.038 ;
    END
  END cfg_target[5]
  PIN cfg_target[6]
    DIRECTION INPUT ;
    USE SIGNAL ;
    PORT
      LAYER M3 ;
        RECT  76.716 0 76.734 0.038 ;
    END
  END cfg_target[6]
  PIN cfg_target[7]
    DIRECTION INPUT ;
    USE SIGNAL ;
    PORT
      LAYER M3 ;
        RECT  76.968 0 76.986 0.038 ;
    END
  END cfg_target[7]
  PIN cfg_v
    DIRECTION INPUT ;
    USE SIGNAL ;
    PORT
      LAYER M3 ;
        RECT  77.256 0 77.274 0.038 ;
    END
  END cfg_v
  PIN clk
    DIRECTION INPUT ;
    USE SIGNAL ;
    PORT
      LAYER M3 ;
        RECT  50.58 0 50.598 0.038 ;
    END
  END clk
  PIN configured
    DIRECTION OUTPUT ;
    USE SIGNAL ;
    PORT
      LAYER M3 ;
        RECT  77.544 0 77.562 0.038 ;
    END
  END configured
  PIN desc_base[0]
    DIRECTION INPUT ;
    USE SIGNAL ;
    PORT
      LAYER M3 ;
        RECT  77.796 0 77.814 0.038 ;
    END
  END desc_base[0]
  PIN desc_base[10]
    DIRECTION INPUT ;
    USE SIGNAL ;
    PORT
      LAYER M5 ;
        RECT  80.544 0 80.568 0.084 ;
    END
  END desc_base[10]
  PIN desc_base[11]
    DIRECTION INPUT ;
    USE SIGNAL ;
    PORT
      LAYER M5 ;
        RECT  80.832 0 80.856 0.084 ;
    END
  END desc_base[11]
  PIN desc_base[1]
    DIRECTION INPUT ;
    USE SIGNAL ;
    PORT
      LAYER M3 ;
        RECT  78.084 0 78.102 0.038 ;
    END
  END desc_base[1]
  PIN desc_base[2]
    DIRECTION INPUT ;
    USE SIGNAL ;
    PORT
      LAYER M3 ;
        RECT  78.336 0 78.354 0.038 ;
    END
  END desc_base[2]
  PIN desc_base[3]
    DIRECTION INPUT ;
    USE SIGNAL ;
    PORT
      LAYER M3 ;
        RECT  78.624 0 78.642 0.038 ;
    END
  END desc_base[3]
  PIN desc_base[4]
    DIRECTION INPUT ;
    USE SIGNAL ;
    PORT
      LAYER M3 ;
        RECT  78.912 0 78.93 0.038 ;
    END
  END desc_base[4]
  PIN desc_base[5]
    DIRECTION INPUT ;
    USE SIGNAL ;
    PORT
      LAYER M3 ;
        RECT  79.164 0 79.182 0.038 ;
    END
  END desc_base[5]
  PIN desc_base[6]
    DIRECTION INPUT ;
    USE SIGNAL ;
    PORT
      LAYER M3 ;
        RECT  79.452 0 79.47 0.038 ;
    END
  END desc_base[6]
  PIN desc_base[7]
    DIRECTION INPUT ;
    USE SIGNAL ;
    PORT
      LAYER M3 ;
        RECT  79.74 0 79.758 0.038 ;
    END
  END desc_base[7]
  PIN desc_base[8]
    DIRECTION INPUT ;
    USE SIGNAL ;
    PORT
      LAYER M3 ;
        RECT  79.992 0 80.01 0.038 ;
    END
  END desc_base[8]
  PIN desc_base[9]
    DIRECTION INPUT ;
    USE SIGNAL ;
    PORT
      LAYER M3 ;
        RECT  80.28 0 80.298 0.038 ;
    END
  END desc_base[9]
  PIN desc_limit[0]
    DIRECTION INPUT ;
    USE SIGNAL ;
    PORT
      LAYER M5 ;
        RECT  81.12 0 81.144 0.084 ;
    END
  END desc_limit[0]
  PIN desc_limit[10]
    DIRECTION INPUT ;
    USE SIGNAL ;
    PORT
      LAYER M5 ;
        RECT  83.856 0 83.88 0.084 ;
    END
  END desc_limit[10]
  PIN desc_limit[11]
    DIRECTION INPUT ;
    USE SIGNAL ;
    PORT
      LAYER M5 ;
        RECT  84.144 0 84.168 0.084 ;
    END
  END desc_limit[11]
  PIN desc_limit[12]
    DIRECTION INPUT ;
    USE SIGNAL ;
    PORT
      LAYER M5 ;
        RECT  84.432 0 84.456 0.084 ;
    END
  END desc_limit[12]
  PIN desc_limit[1]
    DIRECTION INPUT ;
    USE SIGNAL ;
    PORT
      LAYER M5 ;
        RECT  81.408 0 81.432 0.084 ;
    END
  END desc_limit[1]
  PIN desc_limit[2]
    DIRECTION INPUT ;
    USE SIGNAL ;
    PORT
      LAYER M5 ;
        RECT  81.648 0 81.672 0.084 ;
    END
  END desc_limit[2]
  PIN desc_limit[3]
    DIRECTION INPUT ;
    USE SIGNAL ;
    PORT
      LAYER M5 ;
        RECT  81.936 0 81.96 0.084 ;
    END
  END desc_limit[3]
  PIN desc_limit[4]
    DIRECTION INPUT ;
    USE SIGNAL ;
    PORT
      LAYER M5 ;
        RECT  82.224 0 82.248 0.084 ;
    END
  END desc_limit[4]
  PIN desc_limit[5]
    DIRECTION INPUT ;
    USE SIGNAL ;
    PORT
      LAYER M5 ;
        RECT  82.464 0 82.488 0.084 ;
    END
  END desc_limit[5]
  PIN desc_limit[6]
    DIRECTION INPUT ;
    USE SIGNAL ;
    PORT
      LAYER M5 ;
        RECT  82.752 0 82.776 0.084 ;
    END
  END desc_limit[6]
  PIN desc_limit[7]
    DIRECTION INPUT ;
    USE SIGNAL ;
    PORT
      LAYER M5 ;
        RECT  83.04 0 83.064 0.084 ;
    END
  END desc_limit[7]
  PIN desc_limit[8]
    DIRECTION INPUT ;
    USE SIGNAL ;
    PORT
      LAYER M5 ;
        RECT  83.328 0 83.352 0.084 ;
    END
  END desc_limit[8]
  PIN desc_limit[9]
    DIRECTION INPUT ;
    USE SIGNAL ;
    PORT
      LAYER M5 ;
        RECT  83.568 0 83.592 0.084 ;
    END
  END desc_limit[9]
  PIN desc_loops[0]
    DIRECTION INPUT ;
    USE SIGNAL ;
    PORT
      LAYER M5 ;
        RECT  84.672 0 84.696 0.084 ;
    END
  END desc_loops[0]
  PIN desc_loops[10]
    DIRECTION INPUT ;
    USE SIGNAL ;
    PORT
      LAYER M5 ;
        RECT  87.456 0 87.48 0.084 ;
    END
  END desc_loops[10]
  PIN desc_loops[11]
    DIRECTION INPUT ;
    USE SIGNAL ;
    PORT
      LAYER M5 ;
        RECT  87.744 0 87.768 0.084 ;
    END
  END desc_loops[11]
  PIN desc_loops[12]
    DIRECTION INPUT ;
    USE SIGNAL ;
    PORT
      LAYER M5 ;
        RECT  87.984 0 88.008 0.084 ;
    END
  END desc_loops[12]
  PIN desc_loops[13]
    DIRECTION INPUT ;
    USE SIGNAL ;
    PORT
      LAYER M5 ;
        RECT  88.272 0 88.296 0.084 ;
    END
  END desc_loops[13]
  PIN desc_loops[14]
    DIRECTION INPUT ;
    USE SIGNAL ;
    PORT
      LAYER M5 ;
        RECT  88.56 0 88.584 0.084 ;
    END
  END desc_loops[14]
  PIN desc_loops[15]
    DIRECTION INPUT ;
    USE SIGNAL ;
    PORT
      LAYER M5 ;
        RECT  88.848 0 88.872 0.084 ;
    END
  END desc_loops[15]
  PIN desc_loops[1]
    DIRECTION INPUT ;
    USE SIGNAL ;
    PORT
      LAYER M5 ;
        RECT  84.96 0 84.984 0.084 ;
    END
  END desc_loops[1]
  PIN desc_loops[2]
    DIRECTION INPUT ;
    USE SIGNAL ;
    PORT
      LAYER M5 ;
        RECT  85.248 0 85.272 0.084 ;
    END
  END desc_loops[2]
  PIN desc_loops[3]
    DIRECTION INPUT ;
    USE SIGNAL ;
    PORT
      LAYER M5 ;
        RECT  85.536 0 85.56 0.084 ;
    END
  END desc_loops[3]
  PIN desc_loops[4]
    DIRECTION INPUT ;
    USE SIGNAL ;
    PORT
      LAYER M5 ;
        RECT  85.776 0 85.8 0.084 ;
    END
  END desc_loops[4]
  PIN desc_loops[5]
    DIRECTION INPUT ;
    USE SIGNAL ;
    PORT
      LAYER M5 ;
        RECT  86.064 0 86.088 0.084 ;
    END
  END desc_loops[5]
  PIN desc_loops[6]
    DIRECTION INPUT ;
    USE SIGNAL ;
    PORT
      LAYER M5 ;
        RECT  86.352 0 86.376 0.084 ;
    END
  END desc_loops[6]
  PIN desc_loops[7]
    DIRECTION INPUT ;
    USE SIGNAL ;
    PORT
      LAYER M5 ;
        RECT  86.64 0 86.664 0.084 ;
    END
  END desc_loops[7]
  PIN desc_loops[8]
    DIRECTION INPUT ;
    USE SIGNAL ;
    PORT
      LAYER M5 ;
        RECT  86.88 0 86.904 0.084 ;
    END
  END desc_loops[8]
  PIN desc_loops[9]
    DIRECTION INPUT ;
    USE SIGNAL ;
    PORT
      LAYER M5 ;
        RECT  87.168 0 87.192 0.084 ;
    END
  END desc_loops[9]
  PIN desc_v
    DIRECTION INPUT ;
    USE SIGNAL ;
    PORT
      LAYER M5 ;
        RECT  89.088 0 89.112 0.084 ;
    END
  END desc_v
  PIN fault
    DIRECTION OUTPUT ;
    USE SIGNAL ;
    PORT
      LAYER M3 ;
        RECT  89.388 0 89.406 0.038 ;
    END
  END fault
  PIN fault_cause[0]
    DIRECTION OUTPUT ;
    USE SIGNAL ;
    PORT
      LAYER M3 ;
        RECT  89.676 0 89.694 0.038 ;
    END
  END fault_cause[0]
  PIN fault_cause[10]
    DIRECTION OUTPUT ;
    USE SIGNAL ;
    PORT
      LAYER M3 ;
        RECT  92.412 0 92.43 0.038 ;
    END
  END fault_cause[10]
  PIN fault_cause[11]
    DIRECTION OUTPUT ;
    USE SIGNAL ;
    PORT
      LAYER M3 ;
        RECT  92.7 0 92.718 0.038 ;
    END
  END fault_cause[11]
  PIN fault_cause[12]
    DIRECTION OUTPUT ;
    USE SIGNAL ;
    PORT
      LAYER M3 ;
        RECT  92.988 0 93.006 0.038 ;
    END
  END fault_cause[12]
  PIN fault_cause[13]
    DIRECTION OUTPUT ;
    USE SIGNAL ;
    PORT
      LAYER M3 ;
        RECT  93.24 0 93.258 0.038 ;
    END
  END fault_cause[13]
  PIN fault_cause[14]
    DIRECTION OUTPUT ;
    USE SIGNAL ;
    PORT
      LAYER M3 ;
        RECT  93.528 0 93.546 0.038 ;
    END
  END fault_cause[14]
  PIN fault_cause[15]
    DIRECTION OUTPUT ;
    USE SIGNAL ;
    PORT
      LAYER M3 ;
        RECT  93.816 0 93.834 0.038 ;
    END
  END fault_cause[15]
  PIN fault_cause[1]
    DIRECTION OUTPUT ;
    USE SIGNAL ;
    PORT
      LAYER M3 ;
        RECT  89.928 0 89.946 0.038 ;
    END
  END fault_cause[1]
  PIN fault_cause[2]
    DIRECTION OUTPUT ;
    USE SIGNAL ;
    PORT
      LAYER M3 ;
        RECT  90.216 0 90.234 0.038 ;
    END
  END fault_cause[2]
  PIN fault_cause[3]
    DIRECTION OUTPUT ;
    USE SIGNAL ;
    PORT
      LAYER M3 ;
        RECT  90.504 0 90.522 0.038 ;
    END
  END fault_cause[3]
  PIN fault_cause[4]
    DIRECTION OUTPUT ;
    USE SIGNAL ;
    PORT
      LAYER M3 ;
        RECT  90.756 0 90.774 0.038 ;
    END
  END fault_cause[4]
  PIN fault_cause[5]
    DIRECTION OUTPUT ;
    USE SIGNAL ;
    PORT
      LAYER M3 ;
        RECT  91.044 0 91.062 0.038 ;
    END
  END fault_cause[5]
  PIN fault_cause[6]
    DIRECTION OUTPUT ;
    USE SIGNAL ;
    PORT
      LAYER M3 ;
        RECT  91.332 0 91.35 0.038 ;
    END
  END fault_cause[6]
  PIN fault_cause[7]
    DIRECTION OUTPUT ;
    USE SIGNAL ;
    PORT
      LAYER M3 ;
        RECT  91.584 0 91.602 0.038 ;
    END
  END fault_cause[7]
  PIN fault_cause[8]
    DIRECTION OUTPUT ;
    USE SIGNAL ;
    PORT
      LAYER M3 ;
        RECT  91.872 0 91.89 0.038 ;
    END
  END fault_cause[8]
  PIN fault_cause[9]
    DIRECTION OUTPUT ;
    USE SIGNAL ;
    PORT
      LAYER M3 ;
        RECT  92.16 0 92.178 0.038 ;
    END
  END fault_cause[9]
  PIN init_busy
    DIRECTION OUTPUT ;
    USE SIGNAL ;
    PORT
      LAYER M3 ;
        RECT  94.068 0 94.086 0.038 ;
    END
  END init_busy
  PIN issuer_busy
    DIRECTION INPUT ;
    USE SIGNAL ;
    PORT
      LAYER M3 ;
        RECT  94.356 0 94.374 0.038 ;
    END
  END issuer_busy
  PIN issuer_cfg[0]
    DIRECTION OUTPUT ;
    USE SIGNAL ;
    PORT
      LAYER M3 ;
        RECT  94.608 0 94.626 0.038 ;
    END
  END issuer_cfg[0]
  PIN issuer_cfg[10]
    DIRECTION OUTPUT ;
    USE SIGNAL ;
    PORT
      LAYER M3 ;
        RECT  97.38 0 97.398 0.038 ;
    END
  END issuer_cfg[10]
  PIN issuer_cfg[11]
    DIRECTION OUTPUT ;
    USE SIGNAL ;
    PORT
      LAYER M3 ;
        RECT  97.668 0 97.686 0.038 ;
    END
  END issuer_cfg[11]
  PIN issuer_cfg[12]
    DIRECTION OUTPUT ;
    USE SIGNAL ;
    PORT
      LAYER M3 ;
        RECT  97.92 0 97.938 0.038 ;
    END
  END issuer_cfg[12]
  PIN issuer_cfg[13]
    DIRECTION OUTPUT ;
    USE SIGNAL ;
    PORT
      LAYER M5 ;
        RECT  98.208 0 98.232 0.084 ;
    END
  END issuer_cfg[13]
  PIN issuer_cfg[14]
    DIRECTION OUTPUT ;
    USE SIGNAL ;
    PORT
      LAYER M5 ;
        RECT  98.496 0 98.52 0.084 ;
    END
  END issuer_cfg[14]
  PIN issuer_cfg[15]
    DIRECTION OUTPUT ;
    USE SIGNAL ;
    PORT
      LAYER M5 ;
        RECT  98.736 0 98.76 0.084 ;
    END
  END issuer_cfg[15]
  PIN issuer_cfg[16]
    DIRECTION OUTPUT ;
    USE SIGNAL ;
    PORT
      LAYER M5 ;
        RECT  99.024 0 99.048 0.084 ;
    END
  END issuer_cfg[16]
  PIN issuer_cfg[17]
    DIRECTION OUTPUT ;
    USE SIGNAL ;
    PORT
      LAYER M5 ;
        RECT  99.312 0 99.336 0.084 ;
    END
  END issuer_cfg[17]
  PIN issuer_cfg[18]
    DIRECTION OUTPUT ;
    USE SIGNAL ;
    PORT
      LAYER M5 ;
        RECT  99.6 0 99.624 0.084 ;
    END
  END issuer_cfg[18]
  PIN issuer_cfg[19]
    DIRECTION OUTPUT ;
    USE SIGNAL ;
    PORT
      LAYER M5 ;
        RECT  99.84 0 99.864 0.084 ;
    END
  END issuer_cfg[19]
  PIN issuer_cfg[1]
    DIRECTION OUTPUT ;
    USE SIGNAL ;
    PORT
      LAYER M3 ;
        RECT  94.896 0 94.914 0.038 ;
    END
  END issuer_cfg[1]
  PIN issuer_cfg[20]
    DIRECTION OUTPUT ;
    USE SIGNAL ;
    PORT
      LAYER M5 ;
        RECT  100.128 0 100.152 0.084 ;
    END
  END issuer_cfg[20]
  PIN issuer_cfg[21]
    DIRECTION OUTPUT ;
    USE SIGNAL ;
    PORT
      LAYER M5 ;
        RECT  100.416 0 100.44 0.084 ;
    END
  END issuer_cfg[21]
  PIN issuer_cfg[22]
    DIRECTION OUTPUT ;
    USE SIGNAL ;
    PORT
      LAYER M5 ;
        RECT  100.704 0 100.728 0.084 ;
    END
  END issuer_cfg[22]
  PIN issuer_cfg[23]
    DIRECTION OUTPUT ;
    USE SIGNAL ;
    PORT
      LAYER M5 ;
        RECT  100.944 0 100.968 0.084 ;
    END
  END issuer_cfg[23]
  PIN issuer_cfg[24]
    DIRECTION OUTPUT ;
    USE SIGNAL ;
    PORT
      LAYER M5 ;
        RECT  101.232 0 101.256 0.084 ;
    END
  END issuer_cfg[24]
  PIN issuer_cfg[25]
    DIRECTION OUTPUT ;
    USE SIGNAL ;
    PORT
      LAYER M5 ;
        RECT  101.52 0 101.544 0.084 ;
    END
  END issuer_cfg[25]
  PIN issuer_cfg[26]
    DIRECTION OUTPUT ;
    USE SIGNAL ;
    PORT
      LAYER M5 ;
        RECT  101.808 0 101.832 0.084 ;
    END
  END issuer_cfg[26]
  PIN issuer_cfg[27]
    DIRECTION OUTPUT ;
    USE SIGNAL ;
    PORT
      LAYER M5 ;
        RECT  102.048 0 102.072 0.084 ;
    END
  END issuer_cfg[27]
  PIN issuer_cfg[28]
    DIRECTION OUTPUT ;
    USE SIGNAL ;
    PORT
      LAYER M5 ;
        RECT  102.336 0 102.36 0.084 ;
    END
  END issuer_cfg[28]
  PIN issuer_cfg[29]
    DIRECTION OUTPUT ;
    USE SIGNAL ;
    PORT
      LAYER M5 ;
        RECT  102.624 0 102.648 0.084 ;
    END
  END issuer_cfg[29]
  PIN issuer_cfg[2]
    DIRECTION OUTPUT ;
    USE SIGNAL ;
    PORT
      LAYER M3 ;
        RECT  95.184 0 95.202 0.038 ;
    END
  END issuer_cfg[2]
  PIN issuer_cfg[30]
    DIRECTION OUTPUT ;
    USE SIGNAL ;
    PORT
      LAYER M5 ;
        RECT  102.912 0 102.936 0.084 ;
    END
  END issuer_cfg[30]
  PIN issuer_cfg[31]
    DIRECTION OUTPUT ;
    USE SIGNAL ;
    PORT
      LAYER M5 ;
        RECT  103.152 0 103.176 0.084 ;
    END
  END issuer_cfg[31]
  PIN issuer_cfg[32]
    DIRECTION OUTPUT ;
    USE SIGNAL ;
    PORT
      LAYER M5 ;
        RECT  103.44 0 103.464 0.084 ;
    END
  END issuer_cfg[32]
  PIN issuer_cfg[33]
    DIRECTION OUTPUT ;
    USE SIGNAL ;
    PORT
      LAYER M5 ;
        RECT  103.728 0 103.752 0.084 ;
    END
  END issuer_cfg[33]
  PIN issuer_cfg[34]
    DIRECTION OUTPUT ;
    USE SIGNAL ;
    PORT
      LAYER M5 ;
        RECT  104.016 0 104.04 0.084 ;
    END
  END issuer_cfg[34]
  PIN issuer_cfg[35]
    DIRECTION OUTPUT ;
    USE SIGNAL ;
    PORT
      LAYER M5 ;
        RECT  104.256 0 104.28 0.084 ;
    END
  END issuer_cfg[35]
  PIN issuer_cfg[36]
    DIRECTION OUTPUT ;
    USE SIGNAL ;
    PORT
      LAYER M5 ;
        RECT  104.544 0 104.568 0.084 ;
    END
  END issuer_cfg[36]
  PIN issuer_cfg[3]
    DIRECTION OUTPUT ;
    USE SIGNAL ;
    PORT
      LAYER M3 ;
        RECT  95.436 0 95.454 0.038 ;
    END
  END issuer_cfg[3]
  PIN issuer_cfg[4]
    DIRECTION OUTPUT ;
    USE SIGNAL ;
    PORT
      LAYER M3 ;
        RECT  95.724 0 95.742 0.038 ;
    END
  END issuer_cfg[4]
  PIN issuer_cfg[5]
    DIRECTION OUTPUT ;
    USE SIGNAL ;
    PORT
      LAYER M3 ;
        RECT  96.012 0 96.03 0.038 ;
    END
  END issuer_cfg[5]
  PIN issuer_cfg[6]
    DIRECTION OUTPUT ;
    USE SIGNAL ;
    PORT
      LAYER M3 ;
        RECT  96.264 0 96.282 0.038 ;
    END
  END issuer_cfg[6]
  PIN issuer_cfg[7]
    DIRECTION OUTPUT ;
    USE SIGNAL ;
    PORT
      LAYER M3 ;
        RECT  96.552 0 96.57 0.038 ;
    END
  END issuer_cfg[7]
  PIN issuer_cfg[8]
    DIRECTION OUTPUT ;
    USE SIGNAL ;
    PORT
      LAYER M3 ;
        RECT  96.84 0 96.858 0.038 ;
    END
  END issuer_cfg[8]
  PIN issuer_cfg[9]
    DIRECTION OUTPUT ;
    USE SIGNAL ;
    PORT
      LAYER M3 ;
        RECT  97.092 0 97.11 0.038 ;
    END
  END issuer_cfg[9]
  PIN issuer_fault
    DIRECTION INPUT ;
    USE SIGNAL ;
    PORT
      LAYER M5 ;
        RECT  104.832 0 104.856 0.084 ;
    END
  END issuer_fault
  PIN issuer_start
    DIRECTION OUTPUT ;
    USE SIGNAL ;
    PORT
      LAYER M5 ;
        RECT  105.12 0 105.144 0.084 ;
    END
  END issuer_start
  PIN issuer_start_pc[0]
    DIRECTION OUTPUT ;
    USE SIGNAL ;
    PORT
      LAYER M5 ;
        RECT  105.36 0 105.384 0.084 ;
    END
  END issuer_start_pc[0]
  PIN issuer_start_pc[1]
    DIRECTION OUTPUT ;
    USE SIGNAL ;
    PORT
      LAYER M5 ;
        RECT  105.648 0 105.672 0.084 ;
    END
  END issuer_start_pc[1]
  PIN issuer_start_pc[2]
    DIRECTION OUTPUT ;
    USE SIGNAL ;
    PORT
      LAYER M5 ;
        RECT  105.936 0 105.96 0.084 ;
    END
  END issuer_start_pc[2]
  PIN issuer_start_pc[3]
    DIRECTION OUTPUT ;
    USE SIGNAL ;
    PORT
      LAYER M5 ;
        RECT  106.224 0 106.248 0.084 ;
    END
  END issuer_start_pc[3]
  PIN issuer_start_pc[4]
    DIRECTION OUTPUT ;
    USE SIGNAL ;
    PORT
      LAYER M5 ;
        RECT  106.464 0 106.488 0.084 ;
    END
  END issuer_start_pc[4]
  PIN issuer_start_pc[5]
    DIRECTION OUTPUT ;
    USE SIGNAL ;
    PORT
      LAYER M5 ;
        RECT  106.752 0 106.776 0.084 ;
    END
  END issuer_start_pc[5]
  PIN issuer_start_pc[6]
    DIRECTION OUTPUT ;
    USE SIGNAL ;
    PORT
      LAYER M3 ;
        RECT  107.028 0 107.046 0.038 ;
    END
  END issuer_start_pc[6]
  PIN issuer_start_pc[7]
    DIRECTION OUTPUT ;
    USE SIGNAL ;
    PORT
      LAYER M3 ;
        RECT  107.316 0 107.334 0.038 ;
    END
  END issuer_start_pc[7]
  PIN issuer_uop_pc[0]
    DIRECTION INPUT ;
    USE SIGNAL ;
    PORT
      LAYER M3 ;
        RECT  107.604 0 107.622 0.038 ;
    END
  END issuer_uop_pc[0]
  PIN issuer_uop_pc[1]
    DIRECTION INPUT ;
    USE SIGNAL ;
    PORT
      LAYER M3 ;
        RECT  107.856 0 107.874 0.038 ;
    END
  END issuer_uop_pc[1]
  PIN issuer_uop_pc[2]
    DIRECTION INPUT ;
    USE SIGNAL ;
    PORT
      LAYER M3 ;
        RECT  108.144 0 108.162 0.038 ;
    END
  END issuer_uop_pc[2]
  PIN issuer_uop_pc[3]
    DIRECTION INPUT ;
    USE SIGNAL ;
    PORT
      LAYER M3 ;
        RECT  108.432 0 108.45 0.038 ;
    END
  END issuer_uop_pc[3]
  PIN issuer_uop_pc[4]
    DIRECTION INPUT ;
    USE SIGNAL ;
    PORT
      LAYER M3 ;
        RECT  108.684 0 108.702 0.038 ;
    END
  END issuer_uop_pc[4]
  PIN issuer_uop_pc[5]
    DIRECTION INPUT ;
    USE SIGNAL ;
    PORT
      LAYER M3 ;
        RECT  108.972 0 108.99 0.038 ;
    END
  END issuer_uop_pc[5]
  PIN issuer_uop_pc[6]
    DIRECTION INPUT ;
    USE SIGNAL ;
    PORT
      LAYER M3 ;
        RECT  109.26 0 109.278 0.038 ;
    END
  END issuer_uop_pc[6]
  PIN issuer_uop_pc[7]
    DIRECTION INPUT ;
    USE SIGNAL ;
    PORT
      LAYER M3 ;
        RECT  109.512 0 109.53 0.038 ;
    END
  END issuer_uop_pc[7]
  PIN issuer_uop_v
    DIRECTION INPUT ;
    USE SIGNAL ;
    PORT
      LAYER M3 ;
        RECT  109.8 0 109.818 0.038 ;
    END
  END issuer_uop_v
  PIN launch_v
    DIRECTION INPUT ;
    USE SIGNAL ;
    PORT
      LAYER M3 ;
        RECT  110.088 0 110.106 0.038 ;
    END
  END launch_v
  PIN link_abort
    DIRECTION INPUT ;
    USE SIGNAL ;
    PORT
      LAYER M4 ;
        RECT  0 8.832 0.084 8.856 ;
    END
  END link_abort
  PIN program_active
    DIRECTION INPUT ;
    USE SIGNAL ;
    PORT
      LAYER M3 ;
        RECT  110.34 0 110.358 0.038 ;
    END
  END program_active
  PIN program_fault
    DIRECTION OUTPUT ;
    USE SIGNAL ;
    PORT
      LAYER M3 ;
        RECT  110.628 0 110.646 0.038 ;
    END
  END program_fault
  PIN protocol_fault
    DIRECTION INPUT ;
    USE SIGNAL ;
    PORT
      LAYER M4 ;
        RECT  112.236 11.856 112.32 11.88 ;
    END
  END protocol_fault
  PIN qid[0]
    DIRECTION INPUT ;
    USE SIGNAL ;
    PORT
      LAYER M3 ;
        RECT  110.88 0 110.898 0.038 ;
    END
  END qid[0]
  PIN qid[1]
    DIRECTION INPUT ;
    USE SIGNAL ;
    PORT
      LAYER M3 ;
        RECT  111.168 0 111.186 0.038 ;
    END
  END qid[1]
  PIN reduce_fault
    DIRECTION INPUT ;
    USE SIGNAL ;
    PORT
      LAYER M4 ;
        RECT  0 24.528 0.084 24.552 ;
    END
  END reduce_fault
  PIN ring_fault
    DIRECTION INPUT ;
    USE SIGNAL ;
    PORT
      LAYER M4 ;
        RECT  0 40.224 0.084 40.248 ;
    END
  END ring_fault
  PIN rst_n
    DIRECTION INPUT ;
    USE SIGNAL ;
    PORT
      LAYER M3 ;
        RECT  51.804 0 51.822 0.038 ;
    END
  END rst_n
  PIN select_fault[0]
    DIRECTION INPUT ;
    USE SIGNAL ;
    PORT
      LAYER M4 ;
        RECT  112.236 12.96 112.32 12.984 ;
    END
  END select_fault[0]
  PIN select_fault[10]
    DIRECTION INPUT ;
    USE SIGNAL ;
    PORT
      LAYER M4 ;
        RECT  112.236 24.384 112.32 24.408 ;
    END
  END select_fault[10]
  PIN select_fault[11]
    DIRECTION INPUT ;
    USE SIGNAL ;
    PORT
      LAYER M4 ;
        RECT  112.236 25.536 112.32 25.56 ;
    END
  END select_fault[11]
  PIN select_fault[12]
    DIRECTION INPUT ;
    USE SIGNAL ;
    PORT
      LAYER M4 ;
        RECT  112.236 26.688 112.32 26.712 ;
    END
  END select_fault[12]
  PIN select_fault[13]
    DIRECTION INPUT ;
    USE SIGNAL ;
    PORT
      LAYER M4 ;
        RECT  112.236 27.84 112.32 27.864 ;
    END
  END select_fault[13]
  PIN select_fault[14]
    DIRECTION INPUT ;
    USE SIGNAL ;
    PORT
      LAYER M4 ;
        RECT  112.236 28.944 112.32 28.968 ;
    END
  END select_fault[14]
  PIN select_fault[15]
    DIRECTION INPUT ;
    USE SIGNAL ;
    PORT
      LAYER M4 ;
        RECT  112.236 30.096 112.32 30.12 ;
    END
  END select_fault[15]
  PIN select_fault[16]
    DIRECTION INPUT ;
    USE SIGNAL ;
    PORT
      LAYER M4 ;
        RECT  112.236 31.248 112.32 31.272 ;
    END
  END select_fault[16]
  PIN select_fault[17]
    DIRECTION INPUT ;
    USE SIGNAL ;
    PORT
      LAYER M4 ;
        RECT  112.236 32.4 112.32 32.424 ;
    END
  END select_fault[17]
  PIN select_fault[1]
    DIRECTION INPUT ;
    USE SIGNAL ;
    PORT
      LAYER M4 ;
        RECT  112.236 14.112 112.32 14.136 ;
    END
  END select_fault[1]
  PIN select_fault[2]
    DIRECTION INPUT ;
    USE SIGNAL ;
    PORT
      LAYER M4 ;
        RECT  112.236 15.264 112.32 15.288 ;
    END
  END select_fault[2]
  PIN select_fault[3]
    DIRECTION INPUT ;
    USE SIGNAL ;
    PORT
      LAYER M4 ;
        RECT  112.236 16.416 112.32 16.44 ;
    END
  END select_fault[3]
  PIN select_fault[4]
    DIRECTION INPUT ;
    USE SIGNAL ;
    PORT
      LAYER M4 ;
        RECT  112.236 17.568 112.32 17.592 ;
    END
  END select_fault[4]
  PIN select_fault[5]
    DIRECTION INPUT ;
    USE SIGNAL ;
    PORT
      LAYER M4 ;
        RECT  112.236 18.672 112.32 18.696 ;
    END
  END select_fault[5]
  PIN select_fault[6]
    DIRECTION INPUT ;
    USE SIGNAL ;
    PORT
      LAYER M4 ;
        RECT  112.236 19.824 112.32 19.848 ;
    END
  END select_fault[6]
  PIN select_fault[7]
    DIRECTION INPUT ;
    USE SIGNAL ;
    PORT
      LAYER M4 ;
        RECT  112.236 20.976 112.32 21 ;
    END
  END select_fault[7]
  PIN select_fault[8]
    DIRECTION INPUT ;
    USE SIGNAL ;
    PORT
      LAYER M4 ;
        RECT  112.236 22.128 112.32 22.152 ;
    END
  END select_fault[8]
  PIN select_fault[9]
    DIRECTION INPUT ;
    USE SIGNAL ;
    PORT
      LAYER M4 ;
        RECT  112.236 23.232 112.32 23.256 ;
    END
  END select_fault[9]
  PIN tkm_del_slot[0]
    DIRECTION INPUT ;
    USE SIGNAL ;
    PORT
      LAYER M4 ;
        RECT  112.236 33.552 112.32 33.576 ;
    END
  END tkm_del_slot[0]
  PIN tkm_del_slot[1]
    DIRECTION INPUT ;
    USE SIGNAL ;
    PORT
      LAYER M4 ;
        RECT  112.236 34.656 112.32 34.68 ;
    END
  END tkm_del_slot[1]
  PIN tkm_del_slot[2]
    DIRECTION INPUT ;
    USE SIGNAL ;
    PORT
      LAYER M4 ;
        RECT  112.236 35.808 112.32 35.832 ;
    END
  END tkm_del_slot[2]
  PIN tkm_del_slot[3]
    DIRECTION INPUT ;
    USE SIGNAL ;
    PORT
      LAYER M4 ;
        RECT  112.236 36.96 112.32 36.984 ;
    END
  END tkm_del_slot[3]
  PIN tkm_dest_v[0]
    DIRECTION INPUT ;
    USE SIGNAL ;
    PORT
      LAYER M4 ;
        RECT  112.236 38.112 112.32 38.136 ;
    END
  END tkm_dest_v[0]
  PIN tkm_dest_v[1]
    DIRECTION INPUT ;
    USE SIGNAL ;
    PORT
      LAYER M4 ;
        RECT  112.236 39.216 112.32 39.24 ;
    END
  END tkm_dest_v[1]
  PIN tkm_dest_v[2]
    DIRECTION INPUT ;
    USE SIGNAL ;
    PORT
      LAYER M4 ;
        RECT  112.236 40.368 112.32 40.392 ;
    END
  END tkm_dest_v[2]
  PIN tkm_dest_v[3]
    DIRECTION INPUT ;
    USE SIGNAL ;
    PORT
      LAYER M4 ;
        RECT  112.236 41.52 112.32 41.544 ;
    END
  END tkm_dest_v[3]
  PIN tkm_start
    DIRECTION INPUT ;
    USE SIGNAL ;
    PORT
      LAYER M4 ;
        RECT  112.236 42.672 112.32 42.696 ;
    END
  END tkm_start
  PIN unavailable_fault[0]
    DIRECTION INPUT ;
    USE SIGNAL ;
    PORT
      LAYER M4 ;
        RECT  112.236 43.824 112.32 43.848 ;
    END
  END unavailable_fault[0]
  PIN unavailable_fault[10]
    DIRECTION INPUT ;
    USE SIGNAL ;
    PORT
      LAYER M4 ;
        RECT  112.236 55.248 112.32 55.272 ;
    END
  END unavailable_fault[10]
  PIN unavailable_fault[11]
    DIRECTION INPUT ;
    USE SIGNAL ;
    PORT
      LAYER M4 ;
        RECT  112.236 56.352 112.32 56.376 ;
    END
  END unavailable_fault[11]
  PIN unavailable_fault[12]
    DIRECTION INPUT ;
    USE SIGNAL ;
    PORT
      LAYER M4 ;
        RECT  112.236 57.504 112.32 57.528 ;
    END
  END unavailable_fault[12]
  PIN unavailable_fault[13]
    DIRECTION INPUT ;
    USE SIGNAL ;
    PORT
      LAYER M4 ;
        RECT  112.236 58.656 112.32 58.68 ;
    END
  END unavailable_fault[13]
  PIN unavailable_fault[14]
    DIRECTION INPUT ;
    USE SIGNAL ;
    PORT
      LAYER M4 ;
        RECT  112.236 59.808 112.32 59.832 ;
    END
  END unavailable_fault[14]
  PIN unavailable_fault[15]
    DIRECTION INPUT ;
    USE SIGNAL ;
    PORT
      LAYER M4 ;
        RECT  112.236 60.912 112.32 60.936 ;
    END
  END unavailable_fault[15]
  PIN unavailable_fault[16]
    DIRECTION INPUT ;
    USE SIGNAL ;
    PORT
      LAYER M4 ;
        RECT  112.236 62.064 112.32 62.088 ;
    END
  END unavailable_fault[16]
  PIN unavailable_fault[17]
    DIRECTION INPUT ;
    USE SIGNAL ;
    PORT
      LAYER M4 ;
        RECT  112.236 63.216 112.32 63.24 ;
    END
  END unavailable_fault[17]
  PIN unavailable_fault[1]
    DIRECTION INPUT ;
    USE SIGNAL ;
    PORT
      LAYER M4 ;
        RECT  112.236 44.928 112.32 44.952 ;
    END
  END unavailable_fault[1]
  PIN unavailable_fault[2]
    DIRECTION INPUT ;
    USE SIGNAL ;
    PORT
      LAYER M4 ;
        RECT  112.236 46.08 112.32 46.104 ;
    END
  END unavailable_fault[2]
  PIN unavailable_fault[3]
    DIRECTION INPUT ;
    USE SIGNAL ;
    PORT
      LAYER M4 ;
        RECT  112.236 47.232 112.32 47.256 ;
    END
  END unavailable_fault[3]
  PIN unavailable_fault[4]
    DIRECTION INPUT ;
    USE SIGNAL ;
    PORT
      LAYER M4 ;
        RECT  112.236 48.384 112.32 48.408 ;
    END
  END unavailable_fault[4]
  PIN unavailable_fault[5]
    DIRECTION INPUT ;
    USE SIGNAL ;
    PORT
      LAYER M4 ;
        RECT  112.236 49.536 112.32 49.56 ;
    END
  END unavailable_fault[5]
  PIN unavailable_fault[6]
    DIRECTION INPUT ;
    USE SIGNAL ;
    PORT
      LAYER M4 ;
        RECT  112.236 50.64 112.32 50.664 ;
    END
  END unavailable_fault[6]
  PIN unavailable_fault[7]
    DIRECTION INPUT ;
    USE SIGNAL ;
    PORT
      LAYER M4 ;
        RECT  112.236 51.792 112.32 51.816 ;
    END
  END unavailable_fault[7]
  PIN unavailable_fault[8]
    DIRECTION INPUT ;
    USE SIGNAL ;
    PORT
      LAYER M4 ;
        RECT  112.236 52.944 112.32 52.968 ;
    END
  END unavailable_fault[8]
  PIN unavailable_fault[9]
    DIRECTION INPUT ;
    USE SIGNAL ;
    PORT
      LAYER M4 ;
        RECT  112.236 54.096 112.32 54.12 ;
    END
  END unavailable_fault[9]
  PIN writer_fault
    DIRECTION INPUT ;
    USE SIGNAL ;
    PORT
      LAYER M4 ;
        RECT  0 55.92 0.084 55.944 ;
    END
  END writer_fault
  PIN VDD
    DIRECTION INOUT ;
    USE POWER ;
    PORT
      LAYER M5 ;
        RECT  105.192 2.151 105.312 62.649 ;
        RECT  99.792 2.151 99.912 62.649 ;
        RECT  94.392 2.151 94.512 62.649 ;
        RECT  88.992 2.151 89.112 62.649 ;
        RECT  83.592 2.151 83.712 62.649 ;
        RECT  78.192 2.151 78.312 62.649 ;
        RECT  72.792 2.151 72.912 62.649 ;
        RECT  67.392 2.151 67.512 62.649 ;
        RECT  61.992 2.151 62.112 62.649 ;
        RECT  56.592 2.151 56.712 62.649 ;
        RECT  51.192 2.151 51.312 62.649 ;
        RECT  45.792 2.151 45.912 62.649 ;
        RECT  40.392 2.151 40.512 62.649 ;
        RECT  34.992 2.151 35.112 62.649 ;
        RECT  29.592 2.151 29.712 62.649 ;
        RECT  24.192 2.151 24.312 62.649 ;
        RECT  18.792 2.151 18.912 62.649 ;
        RECT  13.392 2.151 13.512 62.649 ;
        RECT  7.992 2.151 8.112 62.649 ;
        RECT  2.592 2.151 2.712 62.649 ;
    END
  END VDD
  PIN VSS
    DIRECTION INOUT ;
    USE GROUND ;
    PORT
      LAYER M5 ;
        RECT  105 2.137 105.12 62.663 ;
        RECT  99.6 2.137 99.72 62.663 ;
        RECT  94.2 2.137 94.32 62.663 ;
        RECT  88.8 2.137 88.92 62.649 ;
        RECT  83.4 2.137 83.52 62.649 ;
        RECT  78 2.137 78.12 62.649 ;
        RECT  72.6 2.137 72.72 62.649 ;
        RECT  67.2 2.137 67.32 62.649 ;
        RECT  61.8 2.137 61.92 62.649 ;
        RECT  56.4 2.137 56.52 62.649 ;
        RECT  51 2.137 51.12 62.649 ;
        RECT  45.6 2.137 45.72 62.649 ;
        RECT  40.2 2.137 40.32 62.649 ;
        RECT  34.8 2.137 34.92 62.649 ;
        RECT  29.4 2.137 29.52 62.649 ;
        RECT  24 2.137 24.12 62.649 ;
        RECT  18.6 2.137 18.72 62.663 ;
        RECT  13.2 2.137 13.32 62.663 ;
        RECT  7.8 2.137 7.92 62.663 ;
        RECT  2.4 2.137 2.52 62.663 ;
    END
  END VSS
  OBS
    LAYER RVTN ;
     RECT  2.16 2.16 110.16 2.295 ;
     RECT  2.16 2.565 110.16 2.835 ;
     RECT  2.16 3.105 110.16 3.375 ;
     RECT  2.16 3.645 110.16 3.915 ;
     RECT  2.16 4.185 110.16 4.455 ;
     RECT  2.16 4.725 110.16 4.995 ;
     RECT  2.16 5.265 110.16 5.535 ;
     RECT  2.16 5.805 110.16 6.075 ;
     RECT  2.16 6.345 110.16 6.615 ;
     RECT  2.16 6.885 110.16 7.155 ;
     RECT  2.16 7.425 110.16 7.695 ;
     RECT  2.16 7.965 110.16 8.235 ;
     RECT  2.16 8.505 110.16 8.775 ;
     RECT  2.16 9.045 110.16 9.315 ;
     RECT  2.16 9.585 110.16 9.855 ;
     RECT  2.16 10.125 110.16 10.395 ;
     RECT  2.16 10.665 110.16 10.935 ;
     RECT  2.16 11.205 110.16 11.475 ;
     RECT  2.16 11.745 110.16 12.015 ;
     RECT  2.16 12.285 110.16 12.555 ;
     RECT  2.16 12.825 110.16 13.095 ;
     RECT  2.16 13.365 110.16 13.635 ;
     RECT  2.16 13.905 110.16 14.175 ;
     RECT  2.16 14.445 110.16 14.715 ;
     RECT  2.16 14.985 110.16 15.255 ;
     RECT  2.16 15.525 110.16 15.795 ;
     RECT  2.16 16.065 110.16 16.335 ;
     RECT  2.16 16.605 110.16 16.875 ;
     RECT  2.16 17.145 110.16 17.415 ;
     RECT  2.16 17.685 110.16 17.955 ;
     RECT  2.16 18.225 110.16 18.495 ;
     RECT  2.16 18.765 110.16 19.035 ;
     RECT  2.16 19.305 110.16 19.575 ;
     RECT  2.16 19.845 110.16 20.115 ;
     RECT  2.16 20.385 110.16 20.655 ;
     RECT  2.16 20.925 110.16 21.195 ;
     RECT  2.16 21.465 110.16 21.735 ;
     RECT  2.16 22.005 110.16 22.275 ;
     RECT  2.16 22.545 110.16 22.815 ;
     RECT  2.16 23.085 110.16 23.355 ;
     RECT  2.16 23.625 110.16 23.895 ;
     RECT  2.16 24.165 110.16 24.435 ;
     RECT  2.16 24.705 110.16 24.975 ;
     RECT  2.16 25.245 110.16 25.515 ;
     RECT  2.16 25.785 110.16 26.055 ;
     RECT  2.16 26.325 110.16 26.595 ;
     RECT  2.16 26.865 110.16 27.135 ;
     RECT  2.16 27.405 110.16 27.675 ;
     RECT  2.16 27.945 110.16 28.215 ;
     RECT  2.16 28.485 110.16 28.755 ;
     RECT  2.16 29.025 110.16 29.295 ;
     RECT  2.16 29.565 110.16 29.835 ;
     RECT  2.16 30.105 110.16 30.375 ;
     RECT  2.16 30.645 110.16 30.915 ;
     RECT  2.16 31.185 110.16 31.455 ;
     RECT  2.16 31.725 110.16 31.995 ;
     RECT  2.16 32.265 110.16 32.535 ;
     RECT  2.16 32.805 110.16 33.075 ;
     RECT  2.16 33.345 110.16 33.615 ;
     RECT  2.16 33.885 110.16 34.155 ;
     RECT  2.16 34.425 110.16 34.695 ;
     RECT  2.16 34.965 110.16 35.235 ;
     RECT  2.16 35.505 110.16 35.775 ;
     RECT  2.16 36.045 110.16 36.315 ;
     RECT  2.16 36.585 110.16 36.855 ;
     RECT  2.16 37.125 110.16 37.395 ;
     RECT  2.16 37.665 110.16 37.935 ;
     RECT  2.16 38.205 110.16 38.475 ;
     RECT  2.16 38.745 110.16 39.015 ;
     RECT  2.16 39.285 110.16 39.555 ;
     RECT  2.16 39.825 110.16 40.095 ;
     RECT  2.16 40.365 110.16 40.635 ;
     RECT  2.16 40.905 110.16 41.04 ;
     RECT  2.16 41.04 20.412 41.175 ;
     RECT  90.828 41.04 110.16 41.175 ;
     RECT  2.16 41.445 20.412 41.715 ;
     RECT  90.828 41.445 110.16 41.715 ;
     RECT  2.16 41.985 20.412 42.255 ;
     RECT  90.828 41.985 110.16 42.255 ;
     RECT  2.16 42.525 20.412 42.795 ;
     RECT  90.828 42.525 110.16 42.795 ;
     RECT  2.16 43.065 20.412 43.335 ;
     RECT  90.828 43.065 110.16 43.335 ;
     RECT  2.16 43.605 20.412 43.875 ;
     RECT  90.828 43.605 110.16 43.875 ;
     RECT  2.16 44.145 20.412 44.415 ;
     RECT  90.828 44.145 110.16 44.415 ;
     RECT  2.16 44.685 20.412 44.955 ;
     RECT  90.828 44.685 110.16 44.955 ;
     RECT  2.16 45.225 20.412 45.495 ;
     RECT  90.828 45.225 110.16 45.495 ;
     RECT  2.16 45.765 20.412 46.035 ;
     RECT  90.828 45.765 110.16 46.035 ;
     RECT  2.16 46.305 20.412 46.575 ;
     RECT  90.828 46.305 110.16 46.575 ;
     RECT  2.16 46.845 20.412 47.115 ;
     RECT  90.828 46.845 110.16 47.115 ;
     RECT  2.16 47.385 20.412 47.655 ;
     RECT  90.828 47.385 110.16 47.655 ;
     RECT  2.16 47.925 20.412 48.195 ;
     RECT  90.828 47.925 110.16 48.195 ;
     RECT  2.16 48.465 20.412 48.735 ;
     RECT  90.828 48.465 110.16 48.735 ;
     RECT  2.16 49.005 20.412 49.275 ;
     RECT  90.828 49.005 110.16 49.275 ;
     RECT  2.16 49.545 20.412 49.815 ;
     RECT  90.828 49.545 110.16 49.815 ;
     RECT  2.16 50.085 20.412 50.355 ;
     RECT  90.828 50.085 110.16 50.355 ;
     RECT  2.16 50.625 20.412 50.895 ;
     RECT  90.828 50.625 110.16 50.895 ;
     RECT  2.16 51.165 20.412 51.435 ;
     RECT  90.828 51.165 110.16 51.435 ;
     RECT  2.16 51.705 20.412 51.975 ;
     RECT  90.828 51.705 110.16 51.975 ;
     RECT  2.16 52.245 20.412 52.515 ;
     RECT  90.828 52.245 110.16 52.515 ;
     RECT  2.16 52.785 20.412 53.055 ;
     RECT  90.828 52.785 110.16 53.055 ;
     RECT  2.16 53.325 20.412 53.595 ;
     RECT  90.828 53.325 110.16 53.595 ;
     RECT  2.16 53.865 20.412 54.135 ;
     RECT  90.828 53.865 110.16 54.135 ;
     RECT  2.16 54.405 20.412 54.675 ;
     RECT  90.828 54.405 110.16 54.675 ;
     RECT  2.16 54.945 20.412 55.215 ;
     RECT  90.828 54.945 110.16 55.215 ;
     RECT  2.16 55.485 20.412 55.755 ;
     RECT  90.828 55.485 110.16 55.755 ;
     RECT  2.16 56.025 20.412 56.295 ;
     RECT  90.828 56.025 110.16 56.295 ;
     RECT  2.16 56.565 20.412 56.835 ;
     RECT  90.828 56.565 110.16 56.835 ;
     RECT  2.16 57.105 20.412 57.375 ;
     RECT  90.828 57.105 110.16 57.375 ;
     RECT  2.16 57.645 20.412 57.915 ;
     RECT  90.828 57.645 110.16 57.915 ;
     RECT  2.16 58.185 20.412 58.455 ;
     RECT  90.828 58.185 110.16 58.455 ;
     RECT  2.16 58.725 20.412 58.995 ;
     RECT  90.828 58.725 110.16 58.995 ;
     RECT  2.16 59.265 20.412 59.535 ;
     RECT  90.828 59.265 110.16 59.535 ;
     RECT  2.16 59.805 20.412 60.075 ;
     RECT  90.828 59.805 110.16 60.075 ;
     RECT  2.16 60.345 20.412 60.615 ;
     RECT  90.828 60.345 110.16 60.615 ;
     RECT  2.16 60.885 20.412 61.155 ;
     RECT  90.828 60.885 110.16 61.155 ;
     RECT  2.16 61.425 20.412 61.695 ;
     RECT  90.828 61.425 110.16 61.695 ;
     RECT  2.16 61.965 20.412 62.235 ;
     RECT  90.828 61.965 110.16 62.235 ;
     RECT  2.16 62.505 20.412 62.64 ;
     RECT  90.828 62.505 110.16 62.64 ;
    LAYER RVTP ;
     RECT  2.16 2.295 110.16 2.565 ;
     RECT  2.16 2.835 110.16 3.105 ;
     RECT  2.16 3.375 110.16 3.645 ;
     RECT  2.16 3.915 110.16 4.185 ;
     RECT  2.16 4.455 110.16 4.725 ;
     RECT  2.16 4.995 110.16 5.265 ;
     RECT  2.16 5.535 110.16 5.805 ;
     RECT  2.16 6.075 110.16 6.345 ;
     RECT  2.16 6.615 110.16 6.885 ;
     RECT  2.16 7.155 110.16 7.425 ;
     RECT  2.16 7.695 110.16 7.965 ;
     RECT  2.16 8.235 110.16 8.505 ;
     RECT  2.16 8.775 110.16 9.045 ;
     RECT  2.16 9.315 110.16 9.585 ;
     RECT  2.16 9.855 110.16 10.125 ;
     RECT  2.16 10.395 110.16 10.665 ;
     RECT  2.16 10.935 110.16 11.205 ;
     RECT  2.16 11.475 110.16 11.745 ;
     RECT  2.16 12.015 110.16 12.285 ;
     RECT  2.16 12.555 110.16 12.825 ;
     RECT  2.16 13.095 110.16 13.365 ;
     RECT  2.16 13.635 110.16 13.905 ;
     RECT  2.16 14.175 110.16 14.445 ;
     RECT  2.16 14.715 110.16 14.985 ;
     RECT  2.16 15.255 110.16 15.525 ;
     RECT  2.16 15.795 110.16 16.065 ;
     RECT  2.16 16.335 110.16 16.605 ;
     RECT  2.16 16.875 110.16 17.145 ;
     RECT  2.16 17.415 110.16 17.685 ;
     RECT  2.16 17.955 110.16 18.225 ;
     RECT  2.16 18.495 110.16 18.765 ;
     RECT  2.16 19.035 110.16 19.305 ;
     RECT  2.16 19.575 110.16 19.845 ;
     RECT  2.16 20.115 110.16 20.385 ;
     RECT  2.16 20.655 110.16 20.925 ;
     RECT  2.16 21.195 110.16 21.465 ;
     RECT  2.16 21.735 110.16 22.005 ;
     RECT  2.16 22.275 110.16 22.545 ;
     RECT  2.16 22.815 110.16 23.085 ;
     RECT  2.16 23.355 110.16 23.625 ;
     RECT  2.16 23.895 110.16 24.165 ;
     RECT  2.16 24.435 110.16 24.705 ;
     RECT  2.16 24.975 110.16 25.245 ;
     RECT  2.16 25.515 110.16 25.785 ;
     RECT  2.16 26.055 110.16 26.325 ;
     RECT  2.16 26.595 110.16 26.865 ;
     RECT  2.16 27.135 110.16 27.405 ;
     RECT  2.16 27.675 110.16 27.945 ;
     RECT  2.16 28.215 110.16 28.485 ;
     RECT  2.16 28.755 110.16 29.025 ;
     RECT  2.16 29.295 110.16 29.565 ;
     RECT  2.16 29.835 110.16 30.105 ;
     RECT  2.16 30.375 110.16 30.645 ;
     RECT  2.16 30.915 110.16 31.185 ;
     RECT  2.16 31.455 110.16 31.725 ;
     RECT  2.16 31.995 110.16 32.265 ;
     RECT  2.16 32.535 110.16 32.805 ;
     RECT  2.16 33.075 110.16 33.345 ;
     RECT  2.16 33.615 110.16 33.885 ;
     RECT  2.16 34.155 110.16 34.425 ;
     RECT  2.16 34.695 110.16 34.965 ;
     RECT  2.16 35.235 110.16 35.505 ;
     RECT  2.16 35.775 110.16 36.045 ;
     RECT  2.16 36.315 110.16 36.585 ;
     RECT  2.16 36.855 110.16 37.125 ;
     RECT  2.16 37.395 110.16 37.665 ;
     RECT  2.16 37.935 110.16 38.205 ;
     RECT  2.16 38.475 110.16 38.745 ;
     RECT  2.16 39.015 110.16 39.285 ;
     RECT  2.16 39.555 110.16 39.825 ;
     RECT  2.16 40.095 110.16 40.365 ;
     RECT  2.16 40.635 110.16 40.905 ;
     RECT  2.16 41.175 20.412 41.445 ;
     RECT  90.828 41.175 110.16 41.445 ;
     RECT  2.16 41.715 20.412 41.985 ;
     RECT  90.828 41.715 110.16 41.985 ;
     RECT  2.16 42.255 20.412 42.525 ;
     RECT  90.828 42.255 110.16 42.525 ;
     RECT  2.16 42.795 20.412 43.065 ;
     RECT  90.828 42.795 110.16 43.065 ;
     RECT  2.16 43.335 20.412 43.605 ;
     RECT  90.828 43.335 110.16 43.605 ;
     RECT  2.16 43.875 20.412 44.145 ;
     RECT  90.828 43.875 110.16 44.145 ;
     RECT  2.16 44.415 20.412 44.685 ;
     RECT  90.828 44.415 110.16 44.685 ;
     RECT  2.16 44.955 20.412 45.225 ;
     RECT  90.828 44.955 110.16 45.225 ;
     RECT  2.16 45.495 20.412 45.765 ;
     RECT  90.828 45.495 110.16 45.765 ;
     RECT  2.16 46.035 20.412 46.305 ;
     RECT  90.828 46.035 110.16 46.305 ;
     RECT  2.16 46.575 20.412 46.845 ;
     RECT  90.828 46.575 110.16 46.845 ;
     RECT  2.16 47.115 20.412 47.385 ;
     RECT  90.828 47.115 110.16 47.385 ;
     RECT  2.16 47.655 20.412 47.925 ;
     RECT  90.828 47.655 110.16 47.925 ;
     RECT  2.16 48.195 20.412 48.465 ;
     RECT  90.828 48.195 110.16 48.465 ;
     RECT  2.16 48.735 20.412 49.005 ;
     RECT  90.828 48.735 110.16 49.005 ;
     RECT  2.16 49.275 20.412 49.545 ;
     RECT  90.828 49.275 110.16 49.545 ;
     RECT  2.16 49.815 20.412 50.085 ;
     RECT  90.828 49.815 110.16 50.085 ;
     RECT  2.16 50.355 20.412 50.625 ;
     RECT  90.828 50.355 110.16 50.625 ;
     RECT  2.16 50.895 20.412 51.165 ;
     RECT  90.828 50.895 110.16 51.165 ;
     RECT  2.16 51.435 20.412 51.705 ;
     RECT  90.828 51.435 110.16 51.705 ;
     RECT  2.16 51.975 20.412 52.245 ;
     RECT  90.828 51.975 110.16 52.245 ;
     RECT  2.16 52.515 20.412 52.785 ;
     RECT  90.828 52.515 110.16 52.785 ;
     RECT  2.16 53.055 20.412 53.325 ;
     RECT  90.828 53.055 110.16 53.325 ;
     RECT  2.16 53.595 20.412 53.865 ;
     RECT  90.828 53.595 110.16 53.865 ;
     RECT  2.16 54.135 20.412 54.405 ;
     RECT  90.828 54.135 110.16 54.405 ;
     RECT  2.16 54.675 20.412 54.945 ;
     RECT  90.828 54.675 110.16 54.945 ;
     RECT  2.16 55.215 20.412 55.485 ;
     RECT  90.828 55.215 110.16 55.485 ;
     RECT  2.16 55.755 20.412 56.025 ;
     RECT  90.828 55.755 110.16 56.025 ;
     RECT  2.16 56.295 20.412 56.565 ;
     RECT  90.828 56.295 110.16 56.565 ;
     RECT  2.16 56.835 20.412 57.105 ;
     RECT  90.828 56.835 110.16 57.105 ;
     RECT  2.16 57.375 20.412 57.645 ;
     RECT  90.828 57.375 110.16 57.645 ;
     RECT  2.16 57.915 20.412 58.185 ;
     RECT  90.828 57.915 110.16 58.185 ;
     RECT  2.16 58.455 20.412 58.725 ;
     RECT  90.828 58.455 110.16 58.725 ;
     RECT  2.16 58.995 20.412 59.265 ;
     RECT  90.828 58.995 110.16 59.265 ;
     RECT  2.16 59.535 20.412 59.805 ;
     RECT  90.828 59.535 110.16 59.805 ;
     RECT  2.16 60.075 20.412 60.345 ;
     RECT  90.828 60.075 110.16 60.345 ;
     RECT  2.16 60.615 20.412 60.885 ;
     RECT  90.828 60.615 110.16 60.885 ;
     RECT  2.16 61.155 20.412 61.425 ;
     RECT  90.828 61.155 110.16 61.425 ;
     RECT  2.16 61.695 20.412 61.965 ;
     RECT  90.828 61.695 110.16 61.965 ;
     RECT  2.16 62.235 20.412 62.505 ;
     RECT  90.828 62.235 110.16 62.505 ;
    LAYER M1 ;
     RECT  2.16 2.151 110.16 41.049 ;
     RECT  22.464 43.2 88.776 61.032 ;
     RECT  2.16 41.049 20.412 62.649 ;
     RECT  90.828 41.049 110.16 62.649 ;
    LAYER M2 ;
     RECT  1.399 3.042 1.687 3.06 ;
     RECT  1.687 3.042 1.939 3.33 ;
     RECT  1.939 2.646 2.16 3.33 ;
     RECT  1.111 4.122 2.16 4.14 ;
     RECT  0.103 8.82 2.16 8.838 ;
     RECT  0.103 40.302 2.16 40.32 ;
     RECT  0.103 55.962 2.16 55.98 ;
     RECT  2.16 2.151 2.515 62.649 ;
     RECT  2.515 1.728 2.759 62.649 ;
     RECT  2.759 2.151 5.215 62.649 ;
     RECT  5.215 1.728 5.567 62.649 ;
     RECT  5.567 2.151 6.511 62.649 ;
     RECT  6.511 1.728 6.683 62.649 ;
     RECT  6.683 2.151 7.411 62.649 ;
     RECT  7.411 2.106 8.951 62.649 ;
     RECT  18.211 0.036 18.815 0.054 ;
     RECT  8.951 2.151 18.895 62.649 ;
     RECT  18.895 2.106 20.412 62.649 ;
     RECT  20.412 59.436 20.651 59.634 ;
     RECT  20.412 49.014 20.687 57.6 ;
     RECT  20.412 47.628 20.831 47.754 ;
     RECT  20.412 45.27 21.191 45.558 ;
     RECT  20.412 2.106 21.263 42.822 ;
     RECT  20.412 44.154 21.335 44.334 ;
     RECT  21.271 0.036 21.371 0.054 ;
     RECT  20.831 47.736 21.371 47.754 ;
     RECT  20.687 49.212 21.415 57.6 ;
     RECT  21.335 44.154 21.443 44.172 ;
     RECT  21.415 49.05 21.551 57.6 ;
     RECT  21.551 49.131 21.659 57.6 ;
     RECT  20.651 59.616 21.695 59.634 ;
     RECT  21.263 2.106 21.811 42.174 ;
     RECT  21.811 1.728 21.983 42.174 ;
     RECT  21.883 43.146 22.464 43.164 ;
     RECT  21.191 45.27 22.464 45.288 ;
     RECT  22.135 46.746 22.464 46.764 ;
     RECT  21.659 49.284 22.464 49.689 ;
     RECT  21.659 50.436 22.464 53.154 ;
     RECT  21.659 54.342 22.464 54.972 ;
     RECT  21.659 55.962 22.464 56.664 ;
     RECT  22.464 43.146 22.487 61.032 ;
     RECT  21.983 2.106 22.883 42.174 ;
     RECT  22.883 2.106 23.747 42.129 ;
     RECT  23.747 2.106 23.855 41.589 ;
     RECT  23.855 2.106 24.007 41.049 ;
     RECT  24.007 1.728 25.871 41.049 ;
     RECT  25.871 2.106 25.943 41.049 ;
     RECT  25.943 2.151 26.779 41.049 ;
     RECT  26.779 0.036 26.879 0.054 ;
     RECT  26.779 2.106 30.371 41.049 ;
     RECT  30.371 2.151 36.499 41.049 ;
     RECT  36.499 1.728 36.743 41.049 ;
     RECT  40.171 0.036 40.307 0.054 ;
     RECT  36.743 2.151 42.223 41.049 ;
     RECT  42.223 1.728 42.395 41.049 ;
     RECT  51.583 0.036 51.827 0.054 ;
     RECT  42.395 2.151 60.691 41.049 ;
     RECT  60.691 1.728 60.863 41.049 ;
     RECT  61.807 0.036 61.979 0.054 ;
     RECT  76.423 0.036 76.595 0.054 ;
     RECT  78.079 0.036 78.179 0.054 ;
     RECT  60.863 2.151 78.331 41.049 ;
     RECT  78.331 1.728 78.467 41.049 ;
     RECT  22.487 43.2 80.815 61.032 ;
     RECT  78.467 2.151 83.227 41.049 ;
     RECT  81.283 0.846 83.767 0.864 ;
     RECT  83.227 2.106 83.767 41.049 ;
     RECT  80.815 42.498 85.459 61.032 ;
     RECT  84.091 0.036 85.927 0.054 ;
     RECT  83.767 0.846 86.647 41.049 ;
     RECT  85.927 0.036 88.303 0.09 ;
     RECT  86.647 0.846 88.303 41.13 ;
     RECT  85.459 41.886 88.776 61.032 ;
     RECT  88.303 0.036 88.835 41.13 ;
     RECT  88.776 56.376 88.907 56.394 ;
     RECT  88.835 0.036 89.411 41.049 ;
     RECT  88.776 54.882 89.635 54.9 ;
     RECT  89.411 1.152 89.699 41.049 ;
     RECT  89.527 53.568 89.851 53.586 ;
     RECT  89.635 54.45 89.851 54.9 ;
     RECT  89.699 1.152 89.951 1.17 ;
     RECT  89.411 0.036 90.527 0.162 ;
     RECT  89.699 2.106 90.563 41.049 ;
     RECT  88.776 49.32 90.643 51.426 ;
     RECT  88.776 59.472 90.643 60.264 ;
     RECT  90.527 0.072 90.779 0.162 ;
     RECT  90.563 2.151 90.828 41.049 ;
     RECT  88.776 41.886 90.828 42.822 ;
     RECT  90.643 49.32 90.828 51.66 ;
     RECT  89.851 53.568 90.828 54.9 ;
     RECT  88.776 57.726 90.828 58.41 ;
     RECT  90.643 59.472 90.828 60.804 ;
     RECT  90.779 0.144 91.355 0.162 ;
     RECT  92.983 1.152 93.307 1.17 ;
     RECT  92.659 0.036 93.371 0.054 ;
     RECT  93.307 0.846 93.623 1.17 ;
     RECT  95.179 0.036 95.747 0.054 ;
     RECT  93.623 0.846 96.547 0.864 ;
     RECT  96.547 0.576 96.835 0.864 ;
     RECT  96.835 0.036 96.907 0.864 ;
     RECT  96.907 0.036 96.935 1.17 ;
     RECT  96.935 0.036 97.187 0.126 ;
     RECT  90.828 2.151 97.519 62.649 ;
     RECT  96.935 1.152 97.763 1.17 ;
     RECT  97.187 0.036 98.015 0.054 ;
     RECT  97.519 2.106 98.951 62.649 ;
     RECT  101.083 1.152 101.723 1.17 ;
     RECT  98.951 2.151 103.207 62.649 ;
     RECT  103.207 1.152 104.495 1.17 ;
     RECT  103.207 2.106 104.575 62.649 ;
     RECT  104.575 2.106 104.711 62.694 ;
     RECT  105.619 1.152 105.719 1.17 ;
     RECT  104.711 2.151 106.763 62.694 ;
     RECT  107.023 1.152 107.375 1.17 ;
     RECT  107.311 0.036 107.663 0.054 ;
     RECT  106.763 2.151 110.16 62.649 ;
     RECT  110.16 2.232 110.363 4.212 ;
     RECT  110.16 22.212 110.579 22.23 ;
     RECT  110.16 32.472 110.579 32.49 ;
     RECT  110.16 48.402 110.579 48.42 ;
     RECT  110.16 49.482 110.579 49.5 ;
     RECT  110.16 50.562 110.579 50.58 ;
     RECT  110.16 54.072 110.579 54.09 ;
     RECT  110.16 60.822 110.579 60.84 ;
     RECT  110.16 62.442 110.579 62.46 ;
     RECT  110.16 4.968 110.615 4.986 ;
     RECT  110.16 11.682 110.615 11.7 ;
     RECT  110.16 14.112 110.615 14.13 ;
     RECT  110.16 15.192 110.615 15.21 ;
     RECT  110.16 19.782 110.615 19.8 ;
     RECT  110.16 20.862 110.615 20.88 ;
     RECT  110.16 30.042 110.615 30.06 ;
     RECT  110.16 33.552 110.615 33.57 ;
     RECT  110.16 34.632 110.615 34.65 ;
     RECT  110.16 35.712 110.615 35.73 ;
     RECT  110.16 43.812 110.615 43.83 ;
     RECT  110.16 44.892 110.615 44.91 ;
     RECT  110.16 59.742 110.615 59.76 ;
     RECT  110.16 6.282 110.651 7.416 ;
     RECT  110.651 7.398 111.155 7.416 ;
     RECT  110.16 8.478 111.155 8.496 ;
     RECT  110.16 10.71 111.155 10.728 ;
     RECT  110.16 13.032 111.155 13.05 ;
     RECT  110.16 17.622 111.155 17.64 ;
     RECT  110.16 23.328 111.155 23.346 ;
     RECT  110.16 27.882 111.155 27.9 ;
     RECT  110.16 28.962 111.155 28.98 ;
     RECT  110.16 38.142 111.155 38.16 ;
     RECT  110.16 39.258 111.155 39.276 ;
     RECT  110.16 42.732 111.155 42.75 ;
     RECT  110.16 52.992 111.155 53.01 ;
     RECT  110.16 57.618 111.155 57.636 ;
     RECT  110.16 58.662 111.155 58.68 ;
     RECT  110.363 3.384 111.191 4.212 ;
     RECT  110.16 25.722 111.731 25.74 ;
     RECT  110.16 31.392 111.731 31.41 ;
     RECT  110.363 2.232 112.235 2.25 ;
     RECT  111.191 3.384 112.235 3.402 ;
     RECT  111.191 4.194 112.235 4.212 ;
     RECT  110.651 6.282 112.235 6.3 ;
     RECT  110.16 9.9 112.235 9.918 ;
     RECT  110.16 16.542 112.235 16.56 ;
     RECT  110.16 18.972 112.235 18.99 ;
     RECT  110.16 24.642 112.235 24.66 ;
     RECT  110.16 37.062 112.235 37.08 ;
     RECT  110.16 40.572 112.235 40.59 ;
     RECT  110.16 47.322 112.235 47.34 ;
     RECT  110.16 55.494 112.235 55.512 ;
    LAYER M3 ;
     RECT  18.792 0.012 27.342 0.031 ;
     RECT  51.804 0.012 51.822 0.031 ;
     RECT  89.388 0.012 97.938 0.031 ;
     RECT  18.216 0.031 27.342 0.059 ;
     RECT  71.748 0.012 80.298 0.077 ;
     RECT  18.216 0.059 18.234 0.091 ;
     RECT  84.096 0.031 84.114 0.091 ;
     RECT  107.028 0.012 111.186 0.091 ;
     RECT  89.388 0.031 98.01 0.095 ;
     RECT  50.58 0.012 50.598 0.125 ;
     RECT  101.16 0.091 101.646 0.139 ;
     RECT  91.044 0.095 98.01 0.523 ;
     RECT  103.212 0.091 103.23 0.523 ;
     RECT  105.156 0.091 105.174 0.523 ;
     RECT  106.308 0.091 111.186 0.523 ;
     RECT  72.288 0.077 80.298 0.557 ;
     RECT  15.372 0.091 15.39 0.571 ;
     RECT  54.072 0.012 62.658 0.571 ;
     RECT  81.9 0.091 81.918 0.571 ;
     RECT  83.628 0.091 84.114 0.571 ;
     RECT  85.932 0.067 85.95 0.571 ;
     RECT  101.088 0.139 101.646 0.571 ;
     RECT  103.212 0.523 103.842 0.571 ;
     RECT  102.636 0.571 104.238 0.619 ;
     RECT  81.9 0.571 84.114 0.841 ;
     RECT  89.388 0.095 90.234 0.869 ;
     RECT  91.044 0.523 98.73 0.869 ;
     RECT  1.116 0.012 9.702 1.147 ;
     RECT  28.8 0.091 28.818 1.147 ;
     RECT  29.556 0.571 29.574 1.147 ;
     RECT  47.808 0.571 47.826 1.147 ;
     RECT  54.072 0.571 63.234 1.147 ;
     RECT  65.412 0.571 65.43 1.147 ;
     RECT  88.308 0.139 88.326 1.147 ;
     RECT  100.62 0.571 101.646 1.147 ;
     RECT  102.636 0.619 104.418 1.147 ;
     RECT  105.156 0.523 111.186 1.147 ;
     RECT  96.912 0.869 98.73 1.175 ;
     RECT  13.752 1.147 14.31 1.195 ;
     RECT  46.26 1.147 46.278 1.387 ;
     RECT  81.288 0.841 84.114 1.453 ;
     RECT  1.116 1.147 10.314 1.723 ;
     RECT  11.376 0.571 11.394 1.723 ;
     RECT  13.644 1.195 14.31 1.723 ;
     RECT  15.372 0.571 15.858 1.723 ;
     RECT  17.676 0.091 18.234 1.723 ;
     RECT  19.044 0.059 27.342 1.723 ;
     RECT  28.548 1.147 28.818 1.723 ;
     RECT  29.556 1.147 30.294 1.723 ;
     RECT  36.432 0.012 44.982 1.723 ;
     RECT  45.756 1.387 46.278 1.723 ;
     RECT  47.808 1.147 48.474 1.723 ;
     RECT  50.148 0.571 50.166 1.723 ;
     RECT  51.588 0.031 51.822 1.723 ;
     RECT  52.632 1.147 63.882 1.723 ;
     RECT  65.412 1.147 65.97 1.723 ;
     RECT  67.788 0.571 68.346 1.723 ;
     RECT  70.704 1.147 70.722 1.723 ;
     RECT  72.828 0.557 80.298 1.723 ;
     RECT  81.288 1.453 84.69 1.723 ;
     RECT  85.932 0.571 86.346 1.723 ;
     RECT  88.308 1.147 88.398 1.723 ;
     RECT  89.64 0.869 90.234 1.723 ;
     RECT  35.496 1.723 35.514 1.771 ;
     RECT  1.116 1.723 34.65 1.819 ;
     RECT  35.388 1.771 35.514 1.819 ;
     RECT  99.468 1.099 99.486 2.011 ;
     RECT  100.512 1.147 101.718 2.011 ;
     RECT  72.828 1.723 90.234 2.101 ;
     RECT  91.044 0.869 96.03 2.101 ;
     RECT  96.984 1.175 98.73 2.101 ;
     RECT  99.468 2.011 101.718 2.101 ;
     RECT  52.632 1.723 66.906 2.143 ;
     RECT  67.752 1.723 71.586 2.143 ;
     RECT  72.828 2.101 96.03 2.143 ;
     RECT  36.324 1.723 51.822 2.191 ;
     RECT  52.632 2.143 71.586 2.191 ;
     RECT  72.615 2.143 96.03 2.191 ;
     RECT  96.984 2.101 101.718 2.191 ;
     RECT  102.636 1.147 111.186 2.191 ;
     RECT  1.116 1.819 35.514 2.299 ;
     RECT  36.288 2.191 51.822 2.299 ;
     RECT  1.116 2.299 51.822 2.371 ;
     RECT  52.632 2.191 96.174 2.371 ;
     RECT  96.984 2.191 111.186 2.371 ;
     RECT  1.116 2.371 111.186 3.335 ;
     RECT  2.376 3.335 111.186 3.911 ;
     RECT  1.116 3.335 1.134 4.145 ;
     RECT  112.212 1.531 112.23 4.217 ;
     RECT  2.376 3.911 110.646 4.531 ;
     RECT  2.34 4.531 110.646 5.069 ;
     RECT  2.34 5.069 87.39 5.099 ;
     RECT  2.34 5.099 87.246 5.741 ;
     RECT  80.352 5.741 87.246 5.845 ;
     RECT  80.352 5.845 87.57 5.881 ;
     RECT  88.38 5.069 110.646 5.881 ;
     RECT  112.212 6.139 112.23 6.305 ;
     RECT  2.34 5.741 79.578 6.611 ;
     RECT  80.352 5.881 110.646 6.611 ;
     RECT  2.415 6.611 79.578 6.691 ;
     RECT  80.352 6.611 104.094 6.691 ;
     RECT  2.415 6.691 104.094 6.809 ;
     RECT  104.832 6.611 110.646 6.809 ;
     RECT  2.415 6.809 103.95 6.845 ;
     RECT  111.132 7.243 111.15 7.421 ;
     RECT  2.415 6.845 103.842 7.723 ;
     RECT  2.376 7.723 103.842 7.861 ;
     RECT  104.832 6.809 110.07 7.861 ;
     RECT  2.376 7.861 110.07 7.889 ;
     RECT  111.132 8.395 111.15 8.501 ;
     RECT  0.108 8.815 0.126 8.861 ;
     RECT  2.415 7.889 110.07 9.923 ;
     RECT  112.212 9.547 112.23 9.923 ;
     RECT  2.415 9.923 22.086 10.669 ;
     RECT  111.132 10.696 111.15 10.733 ;
     RECT  2.34 10.669 22.086 11.101 ;
     RECT  22.86 9.923 110.07 11.101 ;
     RECT  2.34 11.101 110.07 11.677 ;
     RECT  2.34 11.677 110.61 11.885 ;
     RECT  2.34 11.885 110.07 12.623 ;
     RECT  2.415 12.623 110.07 12.659 ;
     RECT  110.052 12.659 110.07 12.893 ;
     RECT  111.132 12.955 111.15 13.055 ;
     RECT  2.415 12.659 108.99 13.441 ;
     RECT  2.415 13.441 109.35 13.909 ;
     RECT  110.592 14.101 110.61 14.141 ;
     RECT  2.34 13.909 109.35 14.243 ;
     RECT  2.415 14.243 109.35 14.791 ;
     RECT  2.415 14.791 109.422 14.989 ;
     RECT  110.592 15.187 110.61 15.293 ;
     RECT  2.376 14.989 109.422 15.331 ;
     RECT  2.376 15.331 109.746 15.449 ;
     RECT  112.212 16.411 112.23 16.565 ;
     RECT  2.376 15.449 109.422 16.609 ;
     RECT  2.376 16.609 109.674 16.681 ;
     RECT  2.376 16.681 109.854 16.799 ;
     RECT  2.376 16.799 109.242 17.519 ;
     RECT  2.376 17.519 108.846 17.609 ;
     RECT  111.132 17.563 111.15 17.645 ;
     RECT  109.656 17.761 109.674 17.879 ;
     RECT  2.415 17.609 108.846 18.563 ;
     RECT  112.212 18.667 112.23 18.995 ;
     RECT  2.415 18.563 27.666 19.309 ;
     RECT  28.404 18.563 108.846 19.309 ;
     RECT  2.415 19.309 108.846 19.651 ;
     RECT  110.592 19.777 110.61 19.853 ;
     RECT  2.415 19.651 108.954 19.921 ;
     RECT  2.415 19.921 109.206 19.949 ;
     RECT  3.6 19.949 109.206 20.183 ;
     RECT  2.415 19.949 2.697 20.695 ;
     RECT  2.376 20.695 2.697 20.731 ;
     RECT  3.6 20.183 108.846 20.731 ;
     RECT  110.592 20.857 110.61 21.005 ;
     RECT  2.376 20.731 108.846 21.271 ;
     RECT  2.376 21.271 108.99 21.533 ;
     RECT  28.404 21.533 108.99 22.081 ;
     RECT  28.404 22.081 109.494 22.199 ;
     RECT  110.556 22.123 110.574 22.235 ;
     RECT  2.376 21.533 27.666 22.549 ;
     RECT  28.404 22.199 109.062 22.549 ;
     RECT  2.376 22.549 109.062 22.855 ;
     RECT  2.34 22.855 109.062 23.161 ;
     RECT  2.34 23.161 109.35 23.251 ;
     RECT  2.34 23.251 109.854 23.315 ;
     RECT  111.132 23.227 111.15 23.351 ;
     RECT  11.952 23.315 109.854 23.459 ;
     RECT  2.34 23.315 10.998 24.061 ;
     RECT  12.024 23.459 109.854 24.089 ;
     RECT  2.34 24.061 11.286 24.269 ;
     RECT  12.024 24.089 109.602 24.359 ;
     RECT  2.34 24.269 3.186 24.475 ;
     RECT  2.268 24.475 3.186 24.509 ;
     RECT  4.284 24.269 11.286 24.511 ;
     RECT  12.024 24.359 108.954 24.511 ;
     RECT  2.268 24.509 2.697 24.557 ;
     RECT  4.284 24.511 108.954 24.665 ;
     RECT  112.212 24.379 112.23 24.665 ;
     RECT  6.552 24.665 108.954 24.809 ;
     RECT  4.536 24.665 5.706 24.899 ;
     RECT  4.536 24.899 5.13 25.043 ;
     RECT  7.02 24.809 108.954 25.591 ;
     RECT  111.708 25.531 111.726 25.745 ;
     RECT  7.02 25.591 109.35 25.825 ;
     RECT  6.84 25.825 109.35 25.861 ;
     RECT  6.84 25.861 109.602 25.889 ;
     RECT  6.84 25.889 108.81 26.203 ;
     RECT  6.696 26.203 108.81 26.519 ;
     RECT  109.584 25.889 109.602 26.527 ;
     RECT  6.84 26.519 108.81 26.635 ;
     RECT  109.584 26.527 110.034 26.635 ;
     RECT  6.84 26.635 110.034 26.717 ;
     RECT  6.84 26.717 109.35 26.789 ;
     RECT  7.272 26.789 109.35 27.365 ;
     RECT  7.272 27.365 108.774 27.751 ;
     RECT  7.164 27.751 108.774 27.869 ;
     RECT  109.548 27.445 109.566 27.869 ;
     RECT  111.132 27.835 111.15 27.905 ;
     RECT  111.132 28.939 111.15 28.985 ;
     RECT  7.272 27.869 108.774 29.021 ;
     RECT  88.596 29.021 108.774 29.029 ;
     RECT  7.272 29.021 87.822 29.065 ;
     RECT  6.948 29.065 87.822 29.083 ;
     RECT  88.596 29.029 108.846 29.101 ;
     RECT  88.596 29.101 108.882 29.219 ;
     RECT  6.804 29.083 87.822 29.489 ;
     RECT  7.416 29.489 87.822 30.001 ;
     RECT  88.596 29.219 106.578 30.001 ;
     RECT  7.416 30.001 106.578 30.065 ;
     RECT  110.592 30.037 110.61 30.125 ;
     RECT  107.316 29.219 108.846 30.181 ;
     RECT  107.316 30.181 109.422 30.407 ;
     RECT  79.956 30.065 106.578 30.415 ;
     RECT  107.316 30.407 107.91 30.415 ;
     RECT  79.956 30.415 107.91 30.443 ;
     RECT  79.956 30.443 107.442 30.569 ;
     RECT  108.648 30.407 109.422 30.569 ;
     RECT  104.904 30.569 107.442 30.605 ;
     RECT  79.956 30.569 104.094 30.713 ;
     RECT  105.015 30.605 107.442 30.713 ;
     RECT  108.648 30.569 108.774 30.713 ;
     RECT  99.216 30.713 104.094 30.749 ;
     RECT  106.596 30.713 107.442 30.749 ;
     RECT  79.956 30.713 98.442 30.839 ;
     RECT  99.216 30.749 103.266 30.839 ;
     RECT  7.416 30.065 79.218 30.847 ;
     RECT  79.956 30.839 97.974 30.847 ;
     RECT  99.216 30.839 102.33 30.875 ;
     RECT  104.04 30.749 104.094 30.875 ;
     RECT  7.416 30.847 97.974 30.955 ;
     RECT  99.216 30.875 102.15 31.019 ;
     RECT  104.076 30.875 104.094 31.019 ;
     RECT  7.236 30.955 97.974 31.145 ;
     RECT  87.876 31.145 97.974 31.181 ;
     RECT  99.615 31.019 102.15 31.181 ;
     RECT  103.14 30.839 103.266 31.181 ;
     RECT  101.088 31.181 102.15 31.217 ;
     RECT  99.615 31.181 100.026 31.253 ;
     RECT  88.344 31.181 97.974 31.289 ;
     RECT  88.344 31.289 96.786 31.379 ;
     RECT  97.632 31.289 97.974 31.379 ;
     RECT  101.232 31.217 102.15 31.379 ;
     RECT  105.015 30.713 105.822 31.379 ;
     RECT  105.015 31.379 105.75 31.387 ;
     RECT  111.708 31.243 111.726 31.415 ;
     RECT  97.704 31.379 97.974 31.451 ;
     RECT  7.236 31.145 87.066 31.487 ;
     RECT  7.236 31.487 81.738 31.531 ;
     RECT  108.648 30.713 108.666 31.531 ;
     RECT  7.2 31.531 81.738 31.649 ;
     RECT  82.512 31.487 87.066 31.649 ;
     RECT  88.344 31.379 91.062 31.649 ;
     RECT  106.596 30.749 107.262 31.649 ;
     RECT  7.236 31.649 81.738 31.721 ;
     RECT  85.212 31.649 87.066 31.757 ;
     RECT  91.836 31.379 96.786 31.757 ;
     RECT  82.512 31.649 84.33 31.829 ;
     RECT  82.512 31.829 84.258 31.901 ;
     RECT  7.236 31.721 79.83 31.919 ;
     RECT  80.82 31.721 81.738 31.919 ;
     RECT  101.592 31.379 102.15 31.919 ;
     RECT  104.4 31.387 105.75 31.927 ;
     RECT  80.82 31.919 81.63 31.955 ;
     RECT  82.512 31.901 83.697 31.955 ;
     RECT  88.815 31.649 91.062 31.955 ;
     RECT  82.764 31.955 83.697 31.991 ;
     RECT  82.836 31.991 83.697 32.027 ;
     RECT  102.132 31.919 102.15 32.063 ;
     RECT  80.82 31.955 81.558 32.189 ;
     RECT  85.32 31.757 87.066 32.189 ;
     RECT  104.04 31.927 105.75 32.189 ;
     RECT  104.04 32.189 105.297 32.225 ;
     RECT  80.82 32.189 81.522 32.261 ;
     RECT  7.416 31.919 79.83 32.297 ;
     RECT  83.088 32.027 83.697 32.297 ;
     RECT  108.648 31.531 108.99 32.341 ;
     RECT  108.648 32.341 109.314 32.459 ;
     RECT  7.416 32.297 78.462 32.495 ;
     RECT  79.236 32.297 79.83 32.495 ;
     RECT  104.76 32.225 105.297 32.495 ;
     RECT  110.556 32.395 110.574 32.495 ;
     RECT  79.236 32.495 79.794 32.567 ;
     RECT  79.236 32.567 79.722 32.729 ;
     RECT  79.236 32.729 79.578 32.765 ;
     RECT  7.524 32.495 78.462 33.151 ;
     RECT  79.236 32.765 79.434 33.151 ;
     RECT  107.244 31.649 107.262 33.385 ;
     RECT  108.648 32.459 108.666 33.385 ;
     RECT  7.524 33.151 79.434 33.421 ;
     RECT  105.015 32.495 105.297 33.421 ;
     RECT  108.648 33.385 108.702 33.421 ;
     RECT  7.236 33.421 79.434 33.581 ;
     RECT  110.592 33.541 110.61 33.581 ;
     RECT  107.244 33.385 107.838 33.619 ;
     RECT  108.648 33.421 108.954 33.619 ;
     RECT  107.244 33.619 108.954 33.629 ;
     RECT  108.216 33.629 108.954 33.691 ;
     RECT  108.216 33.691 109.206 33.809 ;
     RECT  7.524 33.581 79.434 33.845 ;
     RECT  108.648 33.809 109.206 33.953 ;
     RECT  7.524 33.845 79.29 33.989 ;
     RECT  107.244 33.629 107.262 34.429 ;
     RECT  7.524 33.989 79.254 34.465 ;
     RECT  105.015 33.421 105.822 34.501 ;
     RECT  106.596 34.429 107.802 34.501 ;
     RECT  97.956 31.451 97.974 34.529 ;
     RECT  7.488 34.465 79.254 34.619 ;
     RECT  105.015 34.501 107.802 34.655 ;
     RECT  110.592 34.627 110.61 34.685 ;
     RECT  109.62 34.591 109.638 34.727 ;
     RECT  107.784 34.655 107.802 34.735 ;
     RECT  107.784 34.735 107.874 34.889 ;
     RECT  107.856 34.889 107.874 34.961 ;
     RECT  99.615 31.253 99.897 35.032 ;
     RECT  103.14 31.181 103.158 35.035 ;
     RECT  99.504 35.032 99.897 35.069 ;
     RECT  102.6 35.035 103.158 35.213 ;
     RECT  7.488 34.619 78.93 35.309 ;
     RECT  92.052 31.757 96.786 35.339 ;
     RECT  7.74 35.309 78.93 35.573 ;
     RECT  75.312 35.573 78.93 35.671 ;
     RECT  75.312 35.671 78.966 35.735 ;
     RECT  110.592 35.707 110.61 35.837 ;
     RECT  75.42 35.735 78.966 35.969 ;
     RECT  109.656 35.851 109.674 35.969 ;
     RECT  105.015 34.655 107.01 35.995 ;
     RECT  75.42 35.969 78.822 36.005 ;
     RECT  104.4 35.995 107.01 36.041 ;
     RECT  109.836 36.121 109.854 36.275 ;
     RECT  104.58 36.041 107.01 36.347 ;
     RECT  7.74 35.573 74.394 36.391 ;
     RECT  104.58 36.347 106.29 36.419 ;
     RECT  7.74 36.391 74.646 36.625 ;
     RECT  75.42 36.005 78.297 36.625 ;
     RECT  108.648 33.953 108.666 36.931 ;
     RECT  108.648 36.931 109.026 37.049 ;
     RECT  7.74 36.625 78.297 37.085 ;
     RECT  112.212 36.955 112.23 37.085 ;
     RECT  9.648 37.085 78.297 37.165 ;
     RECT  104.976 36.419 106.29 37.201 ;
     RECT  107.172 36.931 107.19 37.201 ;
     RECT  9.648 37.165 78.642 37.291 ;
     RECT  7.74 37.085 8.802 37.319 ;
     RECT  104.256 37.201 107.19 37.319 ;
     RECT  104.256 37.319 106.254 37.339 ;
     RECT  9.648 37.291 78.75 37.355 ;
     RECT  104.076 37.339 106.254 37.391 ;
     RECT  107.172 37.319 107.19 37.391 ;
     RECT  9.936 37.355 78.75 37.589 ;
     RECT  104.796 37.391 106.254 37.589 ;
     RECT  9.936 37.589 78.642 37.613 ;
     RECT  10.224 37.613 78.642 37.625 ;
     RECT  10.224 37.625 33.822 37.733 ;
     RECT  10.224 37.733 16.83 37.859 ;
     RECT  34.704 37.625 73.854 37.859 ;
     RECT  74.592 37.625 78.297 37.859 ;
     RECT  10.224 37.859 10.566 37.895 ;
     RECT  74.736 37.859 78.297 37.895 ;
     RECT  34.704 37.859 73.71 37.931 ;
     RECT  10.224 37.895 10.242 37.967 ;
     RECT  74.736 37.895 74.97 37.967 ;
     RECT  108.648 37.049 108.954 37.975 ;
     RECT  75.744 37.895 78.297 38.003 ;
     RECT  107.316 37.399 107.334 38.011 ;
     RECT  11.304 37.859 16.83 38.039 ;
     RECT  12.06 38.039 16.83 38.129 ;
     RECT  75.744 38.003 76.338 38.129 ;
     RECT  107.316 38.011 107.838 38.129 ;
     RECT  108.576 37.975 108.954 38.137 ;
     RECT  12.06 38.129 16.722 38.165 ;
     RECT  111.132 38.107 111.15 38.165 ;
     RECT  64.908 37.931 73.71 38.189 ;
     RECT  75.78 38.129 76.338 38.189 ;
     RECT  75.78 38.189 76.086 38.201 ;
     RECT  107.316 38.129 107.658 38.201 ;
     RECT  108.468 38.137 108.954 38.281 ;
     RECT  12.276 38.165 16.722 38.399 ;
     RECT  74.736 37.967 74.862 38.399 ;
     RECT  75.78 38.201 75.978 38.399 ;
     RECT  12.276 38.399 12.294 38.435 ;
     RECT  74.736 38.399 74.754 38.435 ;
     RECT  75.78 38.399 75.798 38.435 ;
     RECT  77.292 38.003 78.297 38.435 ;
     RECT  108.468 38.281 109.206 38.435 ;
     RECT  17.568 37.733 33.822 38.443 ;
     RECT  34.704 37.931 64.134 38.443 ;
     RECT  11.304 38.039 11.322 38.507 ;
     RECT  108.576 38.435 109.206 38.543 ;
     RECT  13.176 38.399 16.722 38.669 ;
     RECT  17.568 38.443 64.134 38.669 ;
     RECT  17.568 38.669 33.858 38.705 ;
     RECT  64.908 38.189 73.35 38.705 ;
     RECT  17.568 38.705 33.534 38.741 ;
     RECT  64.908 38.705 72.954 38.785 ;
     RECT  34.704 38.669 64.134 38.821 ;
     RECT  64.872 38.785 72.954 38.821 ;
     RECT  17.82 38.741 33.534 38.849 ;
     RECT  17.856 38.849 33.534 38.939 ;
     RECT  13.215 38.669 16.722 39.019 ;
     RECT  105.015 37.589 106.254 39.091 ;
     RECT  107.316 38.201 107.334 39.091 ;
     RECT  91.044 31.955 91.062 39.119 ;
     RECT  108.576 38.543 108.594 39.119 ;
     RECT  13.215 39.019 16.794 39.209 ;
     RECT  34.704 38.821 72.954 39.209 ;
     RECT  105.015 39.091 107.334 39.209 ;
     RECT  13.215 39.209 15.498 39.245 ;
     RECT  17.856 38.939 17.874 39.245 ;
     RECT  18.615 38.939 33.534 39.245 ;
     RECT  111.132 39.211 111.15 39.281 ;
     RECT  34.704 39.209 57.114 39.293 ;
     RECT  15.408 39.245 15.498 39.317 ;
     RECT  16.38 39.209 16.794 39.317 ;
     RECT  58.032 39.209 72.954 39.317 ;
     RECT  58.032 39.317 72.897 39.341 ;
     RECT  16.38 39.317 16.758 39.389 ;
     RECT  16.452 39.389 16.758 39.479 ;
     RECT  26.316 39.245 33.534 39.487 ;
     RECT  34.704 39.293 56.934 39.487 ;
     RECT  16.452 39.479 16.578 39.515 ;
     RECT  108.288 39.289 108.306 39.515 ;
     RECT  105.015 39.209 107.01 39.587 ;
     RECT  13.215 39.245 14.526 39.623 ;
     RECT  13.215 39.623 14.418 39.659 ;
     RECT  26.316 39.487 33.786 39.659 ;
     RECT  34.632 39.487 56.934 39.721 ;
     RECT  14.292 39.659 14.418 39.749 ;
     RECT  18.615 39.245 25.542 39.749 ;
     RECT  26.784 39.659 33.786 39.757 ;
     RECT  34.524 39.721 56.934 39.757 ;
     RECT  14.292 39.749 14.31 39.785 ;
     RECT  26.784 39.757 56.934 39.785 ;
     RECT  15.48 39.317 15.498 39.857 ;
     RECT  26.784 39.785 29.697 39.857 ;
     RECT  58.032 39.341 71.442 39.893 ;
     RECT  72.36 39.341 72.897 39.893 ;
     RECT  71.424 39.893 71.442 39.965 ;
     RECT  58.032 39.893 70.362 39.991 ;
     RECT  30.672 39.785 56.934 40.019 ;
     RECT  18.615 39.749 25.362 40.055 ;
     RECT  30.744 40.019 33.246 40.055 ;
     RECT  42.444 40.019 56.934 40.055 ;
     RECT  34.416 40.019 41.526 40.064 ;
     RECT  34.416 40.064 41.31 40.127 ;
     RECT  9 40.135 9.018 40.171 ;
     RECT  26.784 39.857 28.242 40.199 ;
     RECT  34.416 40.127 37.998 40.199 ;
     RECT  57.672 39.991 70.362 40.199 ;
     RECT  50.04 40.055 56.934 40.261 ;
     RECT  57.672 40.199 68.778 40.261 ;
     RECT  26.784 40.199 27.954 40.289 ;
     RECT  32.94 40.055 33.246 40.289 ;
     RECT  34.416 40.199 35.097 40.289 ;
     RECT  37.296 40.199 37.998 40.289 ;
     RECT  50.04 40.261 68.778 40.289 ;
     RECT  6.48 40.261 6.498 40.297 ;
     RECT  7.74 37.319 8.097 40.297 ;
     RECT  6.48 40.297 8.097 40.301 ;
     RECT  0.108 40.219 0.126 40.325 ;
     RECT  27.108 40.289 27.954 40.325 ;
     RECT  69.84 40.199 70.362 40.325 ;
     RECT  35.892 40.199 36.342 40.349 ;
     RECT  42.444 40.055 49.086 40.349 ;
     RECT  27.108 40.325 27.846 40.361 ;
     RECT  35.928 40.349 36.342 40.361 ;
     RECT  37.296 40.289 37.926 40.361 ;
     RECT  38.772 40.127 41.31 40.361 ;
     RECT  32.976 40.289 33.246 40.397 ;
     RECT  36.18 40.361 36.342 40.397 ;
     RECT  69.84 40.325 70.146 40.397 ;
     RECT  30.744 40.055 31.626 40.433 ;
     RECT  33.228 40.397 33.246 40.433 ;
     RECT  34.776 40.289 35.097 40.433 ;
     RECT  36.252 40.397 36.342 40.433 ;
     RECT  37.332 40.361 37.926 40.433 ;
     RECT  45.036 40.349 49.086 40.433 ;
     RECT  50.04 40.289 55.35 40.433 ;
     RECT  64.908 40.289 68.778 40.433 ;
     RECT  7.2 40.301 8.097 40.441 ;
     RECT  9 40.171 9.27 40.441 ;
     RECT  7.2 40.441 9.27 40.469 ;
     RECT  27.396 40.361 27.846 40.469 ;
     RECT  28.98 39.857 29.697 40.469 ;
     RECT  56.376 40.289 63.954 40.469 ;
     RECT  64.908 40.433 68.742 40.469 ;
     RECT  70.128 40.397 70.146 40.469 ;
     RECT  36.252 40.433 36.27 40.493 ;
     RECT  4.536 40.441 5.202 40.559 ;
     RECT  30.744 40.433 31.41 40.559 ;
     RECT  50.112 40.433 53.694 40.559 ;
     RECT  64.908 40.469 65.718 40.559 ;
     RECT  42.444 40.349 43.758 40.561 ;
     RECT  50.112 40.559 52.83 40.589 ;
     RECT  56.376 40.469 58.878 40.589 ;
     RECT  4.536 40.559 4.554 40.595 ;
     RECT  7.2 40.469 8.586 40.595 ;
     RECT  30.96 40.559 31.41 40.595 ;
     RECT  42.444 40.561 43.506 40.595 ;
     RECT  45.18 40.433 49.086 40.595 ;
     RECT  54.504 40.433 55.35 40.595 ;
     RECT  56.415 40.589 58.878 40.595 ;
     RECT  64.944 40.559 65.61 40.595 ;
     RECT  112.212 40.363 112.23 40.595 ;
     RECT  38.772 40.361 40.878 40.631 ;
     RECT  59.652 40.469 63.954 40.631 ;
     RECT  64.944 40.595 64.998 40.631 ;
     RECT  61.704 40.631 63.954 40.637 ;
     RECT  64.944 40.631 64.962 40.637 ;
     RECT  66.492 40.469 68.742 40.64 ;
     RECT  30.96 40.595 31.194 40.667 ;
     RECT  39.528 40.631 40.497 40.667 ;
     RECT  45.18 40.595 47.358 40.667 ;
     RECT  61.704 40.637 62.946 40.667 ;
     RECT  106.992 39.587 107.01 40.667 ;
     RECT  105.015 39.587 106.254 40.675 ;
     RECT  104.364 40.675 106.254 40.733 ;
     RECT  37.332 40.433 37.602 40.739 ;
     RECT  39.564 40.667 40.497 40.739 ;
     RECT  48.204 40.595 49.086 40.739 ;
     RECT  50.76 40.589 52.83 40.739 ;
     RECT  29.412 40.469 29.697 40.787 ;
     RECT  34.815 40.433 35.097 40.787 ;
     RECT  39.78 40.739 40.497 40.787 ;
     RECT  66.492 40.64 67.497 40.787 ;
     RECT  72.615 39.893 72.897 40.787 ;
     RECT  78.015 38.435 78.297 40.787 ;
     RECT  83.415 32.297 83.697 40.787 ;
     RECT  18.615 40.055 25.146 40.829 ;
     RECT  29.412 40.787 29.505 40.829 ;
     RECT  42.48 40.595 43.506 40.829 ;
     RECT  45.18 40.667 46.782 40.829 ;
     RECT  48.204 40.739 48.978 40.829 ;
     RECT  53.568 40.559 53.694 40.829 ;
     RECT  54.72 40.595 55.35 40.829 ;
     RECT  56.415 40.595 57.15 40.829 ;
     RECT  59.796 40.631 60.462 40.829 ;
     RECT  61.74 40.667 62.946 40.829 ;
     RECT  63.756 40.637 63.954 40.829 ;
     RECT  66.492 40.787 67.374 40.829 ;
     RECT  37.332 40.739 37.53 40.865 ;
     RECT  39.78 40.787 40.305 40.865 ;
     RECT  48.204 40.829 48.366 40.865 ;
     RECT  50.76 40.739 52.758 40.865 ;
     RECT  53.568 40.829 53.658 40.865 ;
     RECT  54.72 40.829 55.242 40.865 ;
     RECT  56.415 40.829 57.006 40.865 ;
     RECT  63.756 40.829 63.774 40.865 ;
     RECT  66.492 40.829 67.305 40.865 ;
     RECT  68.436 40.64 68.742 40.865 ;
     RECT  42.48 40.829 43.398 40.877 ;
     RECT  58.104 40.595 58.878 40.901 ;
     RECT  104.508 40.733 106.254 40.901 ;
     RECT  37.512 40.865 37.53 40.937 ;
     RECT  48.348 40.865 48.366 40.937 ;
     RECT  50.76 40.865 51.93 40.937 ;
     RECT  52.74 40.865 52.758 40.937 ;
     RECT  53.64 40.865 53.658 40.937 ;
     RECT  54.72 40.865 54.738 40.937 ;
     RECT  58.104 40.901 58.734 40.937 ;
     RECT  25.128 40.829 25.146 40.973 ;
     RECT  30.96 40.667 30.978 40.973 ;
     RECT  58.716 40.937 58.734 40.973 ;
     RECT  66.672 40.865 67.305 40.973 ;
     RECT  42.768 40.877 42.786 41.009 ;
     RECT  45.615 40.829 46.782 41.009 ;
     RECT  51.015 40.937 51.93 41.009 ;
     RECT  68.436 40.865 68.454 41.009 ;
     RECT  18.615 40.829 24.105 41.057 ;
     RECT  29.415 40.829 29.505 41.057 ;
     RECT  34.815 40.787 34.905 41.057 ;
     RECT  40.215 40.865 40.305 41.057 ;
     RECT  45.615 41.009 45.705 41.057 ;
     RECT  51.015 41.009 51.105 41.057 ;
     RECT  56.415 40.865 56.505 41.057 ;
     RECT  61.815 40.829 61.905 41.057 ;
     RECT  67.215 40.973 67.305 41.057 ;
     RECT  72.615 40.787 72.705 41.057 ;
     RECT  78.015 40.787 78.105 41.057 ;
     RECT  83.415 40.787 83.505 41.057 ;
     RECT  88.815 31.955 89.874 41.107 ;
     RECT  86.652 32.189 87.066 41.135 ;
     RECT  107.172 40.711 107.19 41.135 ;
     RECT  18.615 41.057 23.85 41.549 ;
     RECT  110.016 41.377 110.034 41.549 ;
     RECT  23.724 41.549 23.85 41.594 ;
     RECT  13.215 39.659 13.554 41.611 ;
     RECT  107.712 41.521 107.73 41.675 ;
     RECT  105.015 40.901 106.254 41.755 ;
     RECT  104.904 41.755 106.254 41.791 ;
     RECT  85.464 32.189 85.482 41.909 ;
     RECT  104.076 41.791 106.758 41.909 ;
     RECT  104.364 41.909 106.758 41.981 ;
     RECT  23.724 41.594 23.742 42.134 ;
     RECT  18.615 41.549 22.878 42.179 ;
     RECT  88.812 41.107 89.874 42.493 ;
     RECT  108.684 42.565 108.702 42.601 ;
     RECT  105.015 41.981 106.254 42.629 ;
     RECT  107.82 42.565 107.838 42.719 ;
     RECT  111.132 42.667 111.15 42.755 ;
     RECT  106.02 42.629 106.254 42.763 ;
     RECT  108.684 42.601 108.954 42.835 ;
     RECT  108.504 42.835 108.954 42.871 ;
     RECT  107.676 42.871 107.694 42.941 ;
     RECT  108.504 42.871 109.206 42.989 ;
     RECT  109.188 42.989 109.206 43.133 ;
     RECT  18.615 42.179 22.482 43.2 ;
     RECT  80.82 32.261 80.838 43.2 ;
     RECT  87.048 41.135 87.066 43.2 ;
     RECT  88.344 42.493 89.874 43.2 ;
     RECT  107.928 43.609 107.946 43.681 ;
     RECT  107.316 43.681 107.946 43.799 ;
     RECT  110.592 43.807 110.61 43.853 ;
     RECT  106.02 42.763 106.326 43.871 ;
     RECT  106.236 43.871 106.326 43.879 ;
     RECT  16.452 39.515 16.47 44.069 ;
     RECT  107.928 43.799 107.946 44.069 ;
     RECT  108.828 43.843 108.846 44.213 ;
     RECT  105.015 42.629 105.297 44.419 ;
     RECT  104.976 44.419 105.297 44.443 ;
     RECT  103.14 35.213 103.158 44.447 ;
     RECT  106.236 43.879 106.902 44.483 ;
     RECT  110.592 44.887 110.61 44.957 ;
     RECT  104.4 44.443 105.297 44.995 ;
     RECT  104.4 44.995 105.354 45.005 ;
     RECT  104.976 45.005 105.354 45.031 ;
     RECT  106.236 44.483 106.326 45.031 ;
     RECT  104.976 45.031 106.326 45.149 ;
     RECT  107.172 44.761 107.19 45.149 ;
     RECT  109.476 44.995 109.494 45.221 ;
     RECT  104.976 45.149 106.254 45.293 ;
     RECT  104.976 45.293 106.146 45.329 ;
     RECT  110.016 45.967 110.034 46.109 ;
     RECT  103.824 46.171 103.842 46.309 ;
     RECT  106.02 45.329 106.146 46.309 ;
     RECT  103.824 46.309 103.986 46.345 ;
     RECT  104.976 45.329 105.297 46.345 ;
     RECT  103.824 46.345 105.297 46.381 ;
     RECT  106.02 46.309 106.722 46.381 ;
     RECT  103.824 46.381 106.722 46.499 ;
     RECT  109.008 46.111 109.026 46.607 ;
     RECT  103.824 46.499 106.146 46.643 ;
     RECT  107.676 46.747 107.694 47.155 ;
     RECT  106.884 46.651 106.902 47.191 ;
     RECT  107.676 47.155 107.838 47.191 ;
     RECT  106.884 47.191 107.838 47.309 ;
     RECT  108.684 47.155 108.954 47.317 ;
     RECT  106.884 47.309 107.334 47.345 ;
     RECT  112.212 47.227 112.23 47.345 ;
     RECT  108.216 47.317 108.954 47.461 ;
     RECT  108.216 47.461 109.206 47.615 ;
     RECT  109.188 47.615 109.206 47.723 ;
     RECT  105.015 46.643 106.146 48.271 ;
     RECT  106.992 47.345 107.334 48.271 ;
     RECT  105.015 48.271 106.218 48.397 ;
     RECT  106.992 48.271 107.838 48.397 ;
     RECT  110.556 48.379 110.574 48.425 ;
     RECT  109.116 48.361 109.134 48.461 ;
     RECT  105.015 48.397 107.838 48.659 ;
     RECT  105.015 48.659 107.766 48.695 ;
     RECT  92.052 35.339 96.678 49.291 ;
     RECT  90.612 49.477 90.63 49.483 ;
     RECT  110.556 49.477 110.574 49.565 ;
     RECT  90.612 49.483 90.702 49.613 ;
     RECT  109.008 49.621 109.026 49.739 ;
     RECT  90.648 49.613 90.702 49.771 ;
     RECT  105.015 48.695 106.146 49.771 ;
     RECT  104.4 49.771 106.146 49.811 ;
     RECT  107.316 48.695 107.334 49.891 ;
     RECT  90.648 49.771 91.206 50.017 ;
     RECT  91.98 49.291 96.678 50.017 ;
     RECT  106.956 49.891 107.334 50.045 ;
     RECT  90.648 50.017 96.678 50.117 ;
     RECT  104.58 49.811 106.146 50.117 ;
     RECT  107.064 50.045 107.334 50.117 ;
     RECT  90.648 50.117 91.206 50.351 ;
     RECT  18.615 43.2 89.874 50.359 ;
     RECT  18.576 50.359 89.874 50.459 ;
     RECT  110.556 50.557 110.574 50.669 ;
     RECT  90.648 50.351 90.666 50.701 ;
     RECT  90.612 50.701 90.666 50.765 ;
     RECT  105.015 50.117 106.146 50.899 ;
     RECT  107.1 50.117 107.334 50.899 ;
     RECT  91.98 50.117 96.678 50.923 ;
     RECT  104.256 50.899 104.274 50.971 ;
     RECT  105.015 50.899 107.334 50.971 ;
     RECT  104.256 50.971 107.334 51.019 ;
     RECT  104.112 51.019 107.334 51.089 ;
     RECT  91.764 50.923 96.678 51.125 ;
     RECT  107.1 51.089 107.334 51.161 ;
     RECT  104.94 51.089 106.146 51.395 ;
     RECT  90.648 50.765 90.666 51.665 ;
     RECT  110.016 51.709 110.034 51.781 ;
     RECT  109.476 51.781 110.034 51.821 ;
     RECT  92.052 51.125 96.678 51.871 ;
     RECT  109.476 51.821 109.494 51.899 ;
     RECT  91.764 51.871 96.678 51.917 ;
     RECT  107.316 51.161 107.334 52.015 ;
     RECT  108.216 51.979 108.234 52.015 ;
     RECT  107.316 52.015 108.45 52.051 ;
     RECT  104.976 51.395 106.146 52.141 ;
     RECT  107.316 52.051 109.458 52.141 ;
     RECT  104.976 52.141 109.458 52.205 ;
     RECT  104.976 52.205 108.954 52.277 ;
     RECT  104.976 52.277 108.234 52.439 ;
     RECT  104.976 52.439 107.766 52.979 ;
     RECT  111.132 52.939 111.15 53.015 ;
     RECT  107.748 52.979 107.766 53.285 ;
     RECT  104.976 52.979 107.01 53.357 ;
     RECT  18.615 50.459 89.874 53.591 ;
     RECT  104.976 53.357 106.146 53.941 ;
     RECT  106.992 53.357 107.01 53.941 ;
     RECT  108.684 53.941 108.702 54.059 ;
     RECT  104.58 53.941 106.146 54.091 ;
     RECT  110.556 54.067 110.574 54.125 ;
     RECT  104.4 54.091 106.146 54.131 ;
     RECT  89.64 53.591 89.874 54.167 ;
     RECT  106.992 53.941 107.19 54.365 ;
     RECT  89.64 54.167 89.658 54.473 ;
     RECT  104.976 54.131 106.146 54.643 ;
     RECT  92.052 51.917 96.678 54.679 ;
     RECT  18.615 53.591 88.83 54.877 ;
     RECT  91.908 54.679 96.678 54.913 ;
     RECT  108.144 54.139 108.162 55.111 ;
     RECT  108.144 55.111 108.81 55.211 ;
     RECT  104.184 55.021 104.202 55.243 ;
     RECT  91.872 54.913 96.678 55.255 ;
     RECT  104.04 55.243 104.202 55.255 ;
     RECT  104.976 54.643 106.866 55.255 ;
     RECT  104.04 55.255 106.866 55.283 ;
     RECT  104.76 55.283 106.866 55.409 ;
     RECT  110.016 55.255 110.034 55.409 ;
     RECT  112.212 55.243 112.23 55.517 ;
     RECT  91.836 55.255 96.678 55.525 ;
     RECT  103.752 55.381 103.77 55.715 ;
     RECT  7.815 40.595 8.586 55.795 ;
     RECT  91.8 55.525 96.678 55.795 ;
     RECT  2.415 24.557 2.697 55.831 ;
     RECT  7.815 55.795 8.874 55.853 ;
     RECT  14.832 55.723 14.85 55.853 ;
     RECT  2.415 55.831 3.33 55.949 ;
     RECT  6.804 55.651 6.822 55.949 ;
     RECT  8.856 55.853 8.874 55.949 ;
     RECT  0.108 55.915 0.126 55.985 ;
     RECT  5.148 55.831 5.166 55.985 ;
     RECT  91.764 55.795 96.678 55.985 ;
     RECT  108.144 55.211 108.162 56.101 ;
     RECT  105.015 55.409 106.866 56.129 ;
     RECT  91.764 55.985 96.534 56.219 ;
     RECT  108.144 56.101 108.882 56.219 ;
     RECT  108.144 56.219 108.45 56.299 ;
     RECT  107.604 56.299 108.45 56.363 ;
     RECT  110.016 56.299 110.034 56.371 ;
     RECT  109.404 56.371 110.034 56.381 ;
     RECT  108.216 56.363 108.45 56.489 ;
     RECT  109.404 56.381 109.422 56.525 ;
     RECT  108.216 56.489 108.234 56.597 ;
     RECT  91.764 56.219 96.21 56.813 ;
     RECT  91.836 56.813 96.21 56.939 ;
     RECT  91.872 56.939 96.21 56.957 ;
     RECT  91.908 56.957 96.21 57.209 ;
     RECT  91.908 57.209 94.497 57.443 ;
     RECT  95.256 57.209 96.21 57.443 ;
     RECT  95.292 57.443 96.21 57.569 ;
     RECT  107.316 57.451 107.334 57.569 ;
     RECT  105.015 56.129 106.146 57.577 ;
     RECT  18.615 54.877 89.478 57.581 ;
     RECT  111.132 57.499 111.15 57.641 ;
     RECT  91.908 57.443 93.438 57.691 ;
     RECT  91.728 57.691 93.438 57.749 ;
     RECT  93.348 57.749 93.366 57.839 ;
     RECT  95.328 57.569 96.21 57.839 ;
     RECT  105.015 57.577 106.866 57.875 ;
     RECT  108.288 57.721 108.306 57.875 ;
     RECT  95.328 57.839 95.994 57.911 ;
     RECT  95.328 57.911 95.742 57.917 ;
     RECT  105.015 57.875 106.65 57.947 ;
     RECT  95.616 57.917 95.742 57.965 ;
     RECT  95.724 57.965 95.742 57.983 ;
     RECT  18.615 57.581 88.866 58.415 ;
     RECT  105.015 57.947 106.146 58.531 ;
     RECT  94.215 57.443 94.497 58.621 ;
     RECT  104.58 58.531 106.146 58.621 ;
     RECT  104.436 58.621 106.146 58.685 ;
     RECT  111.132 58.648 111.15 58.685 ;
     RECT  93.636 58.621 94.497 58.829 ;
     RECT  108.864 58.693 108.882 58.829 ;
     RECT  13.215 41.611 13.95 58.925 ;
     RECT  107.712 58.693 107.73 58.955 ;
     RECT  91.764 57.749 92.538 58.987 ;
     RECT  91.152 58.987 92.538 59.083 ;
     RECT  91.152 59.083 92.646 59.161 ;
     RECT  18.615 58.415 88.776 59.213 ;
     RECT  91.152 59.161 92.79 59.213 ;
     RECT  20.052 59.213 88.776 59.309 ;
     RECT  21.672 59.309 88.776 59.371 ;
     RECT  20.052 59.309 20.646 59.459 ;
     RECT  91.152 59.213 92.43 59.504 ;
     RECT  105.015 58.685 106.146 59.575 ;
     RECT  104.292 59.575 106.146 59.611 ;
     RECT  104.256 59.611 106.146 59.659 ;
     RECT  104.112 59.659 106.146 59.729 ;
     RECT  91.152 59.504 91.746 59.789 ;
     RECT  106.956 59.611 106.974 59.809 ;
     RECT  110.592 59.737 110.61 59.837 ;
     RECT  20.052 59.459 20.43 59.885 ;
     RECT  91.692 59.789 91.746 59.885 ;
     RECT  104.292 59.729 105.966 59.909 ;
     RECT  21.672 59.371 88.866 59.981 ;
     RECT  91.728 59.885 91.746 59.981 ;
     RECT  106.956 59.809 107.154 59.999 ;
     RECT  104.292 59.909 105.894 60.035 ;
     RECT  20.052 59.885 20.07 60.077 ;
     RECT  109.476 59.809 109.494 60.143 ;
     RECT  21.672 59.981 21.69 60.173 ;
     RECT  22.464 59.981 88.866 60.269 ;
     RECT  91.764 60.235 91.782 60.575 ;
     RECT  90.648 60.043 90.666 60.809 ;
     RECT  110.556 60.817 110.574 60.941 ;
     RECT  108.648 60.817 108.666 60.961 ;
     RECT  22.464 60.269 88.776 61.032 ;
     RECT  18.615 59.213 18.897 61.147 ;
     RECT  107.136 59.999 107.154 61.195 ;
     RECT  108.252 60.961 108.666 61.195 ;
     RECT  107.136 61.195 108.666 61.231 ;
     RECT  107.136 61.231 108.954 61.232 ;
     RECT  18.615 61.147 19.026 61.259 ;
     RECT  107.136 61.232 107.154 61.421 ;
     RECT  108.36 61.232 108.954 61.421 ;
     RECT  110.016 61.969 110.034 62.041 ;
     RECT  109.476 62.041 110.034 62.093 ;
     RECT  106.776 62.005 107.01 62.131 ;
     RECT  108.36 61.421 108.378 62.159 ;
     RECT  109.476 62.093 109.494 62.159 ;
     RECT  104.976 60.035 105.894 62.197 ;
     RECT  106.632 62.131 107.01 62.197 ;
     RECT  104.976 62.197 107.01 62.311 ;
     RECT  2.415 55.949 2.697 62.387 ;
     RECT  7.815 55.853 8.097 62.387 ;
     RECT  13.215 58.925 13.497 62.387 ;
     RECT  18.615 61.259 18.897 62.387 ;
     RECT  94.215 58.829 94.497 62.387 ;
     RECT  99.615 35.069 99.897 62.387 ;
     RECT  104.976 62.311 107.874 62.395 ;
     RECT  104.436 62.395 107.874 62.435 ;
     RECT  104.58 62.435 107.874 62.465 ;
     RECT  105.876 62.465 107.334 62.537 ;
     RECT  106.2 62.537 106.83 62.573 ;
     RECT  106.74 62.573 106.83 62.609 ;
     RECT  2.415 62.387 2.505 62.657 ;
     RECT  7.815 62.387 7.905 62.657 ;
     RECT  13.215 62.387 13.305 62.657 ;
     RECT  18.615 62.387 18.705 62.657 ;
     RECT  94.215 62.387 94.305 62.657 ;
     RECT  99.615 62.387 99.705 62.657 ;
     RECT  104.58 62.465 105.105 62.657 ;
     RECT  104.58 62.657 104.598 62.699 ;
     RECT  106.74 62.609 106.758 62.699 ;
     RECT  110.556 62.437 110.574 63.245 ;
    LAYER M4 ;
     RECT  0.06 8.832 0.137 8.856 ;
     RECT  0.06 40.224 0.137 40.248 ;
     RECT  0.06 55.92 0.137 55.944 ;
     RECT  0.06 24.528 2.329 24.552 ;
     RECT  2.365 3.696 2.408 3.72 ;
     RECT  2.365 7.728 2.408 7.752 ;
     RECT  2.329 12.048 2.408 12.072 ;
     RECT  2.365 15.264 2.408 15.288 ;
     RECT  2.365 17.472 2.408 17.496 ;
     RECT  2.329 24.096 2.408 24.552 ;
     RECT  2.408 2.148 2.512 62.652 ;
     RECT  2.512 2.418 2.704 62.382 ;
     RECT  2.704 2.736 2.867 4.584 ;
     RECT  2.704 17.472 2.867 17.496 ;
     RECT  2.761 0.576 2.873 0.6 ;
     RECT  2.704 24.096 3.197 24.504 ;
     RECT  2.867 3.408 3.457 4.584 ;
     RECT  3.457 3.696 3.521 4.584 ;
     RECT  2.704 10.896 3.697 11.016 ;
     RECT  2.704 13.056 3.769 16.152 ;
     RECT  2.704 5.568 3.805 8.856 ;
     RECT  2.704 12.048 3.881 12.072 ;
     RECT  2.704 22.704 3.881 22.728 ;
     RECT  3.308 0.048 3.923 0.072 ;
     RECT  3.521 3.84 3.973 4.584 ;
     RECT  3.805 5.568 3.973 9.72 ;
     RECT  3.697 10.848 3.98 11.016 ;
     RECT  3.769 13.056 3.98 16.584 ;
     RECT  3.913 2.256 3.997 2.28 ;
     RECT  3.98 12.864 4.067 16.584 ;
     RECT  4.067 13.344 4.277 16.584 ;
     RECT  2.704 18.816 4.309 19.32 ;
     RECT  2.704 20.88 4.345 20.904 ;
     RECT  4.309 18.24 4.499 19.32 ;
     RECT  3.973 3.84 4.525 9.72 ;
     RECT  4.525 3.024 4.565 9.72 ;
     RECT  4.499 18.432 4.565 19.32 ;
     RECT  3.197 24.48 4.565 24.504 ;
     RECT  3.98 10.848 4.849 11.448 ;
     RECT  4.277 13.344 5.029 16.056 ;
     RECT  4.849 10.608 5.101 11.448 ;
     RECT  4.345 20.688 5.101 21.192 ;
     RECT  5.077 22.176 5.101 22.2 ;
     RECT  4.565 18.432 5.177 19.224 ;
     RECT  5.101 20.688 5.184 22.2 ;
     RECT  4.565 3.024 5.249 9.576 ;
     RECT  5.184 20.688 5.281 21.72 ;
     RECT  5.029 12.768 5.569 16.056 ;
     RECT  5.461 17.136 5.569 17.16 ;
     RECT  5.101 10.608 5.677 11.544 ;
     RECT  5.677 10.608 5.701 11.784 ;
     RECT  5.569 12.768 5.701 17.16 ;
     RECT  4.777 24.432 5.749 24.456 ;
     RECT  5.749 23.904 5.836 24.456 ;
     RECT  5.701 10.608 6.001 17.16 ;
     RECT  5.281 20.592 6.145 21.72 ;
     RECT  5.249 5.568 6.181 9.576 ;
     RECT  6.001 10.608 6.181 17.4 ;
     RECT  6.181 5.568 6.293 17.4 ;
     RECT  6.293 5.568 6.329 16.056 ;
     RECT  5.249 3.024 6.685 4.536 ;
     RECT  6.329 5.568 6.685 12.6 ;
     RECT  6.293 17.04 7.333 17.4 ;
     RECT  6.685 3.024 7.369 12.6 ;
     RECT  6.329 13.68 7.369 16.056 ;
     RECT  6.145 20.304 7.477 21.72 ;
     RECT  7.333 17.04 7.525 17.448 ;
     RECT  5.177 18.432 7.525 19.08 ;
     RECT  6.793 29.088 7.657 29.112 ;
     RECT  6.685 26.208 7.693 26.232 ;
     RECT  7.549 27.936 7.693 27.96 ;
     RECT  7.693 26.208 7.765 27.96 ;
     RECT  7.477 20.304 7.801 22.008 ;
     RECT  7.369 3.024 7.808 16.056 ;
     RECT  7.525 17.04 7.808 19.08 ;
     RECT  7.801 20.16 7.808 22.008 ;
     RECT  6.181 24.48 7.808 24.504 ;
     RECT  7.765 25.536 7.808 27.96 ;
     RECT  7.657 29.088 7.808 29.784 ;
     RECT  7.225 30.96 7.808 30.984 ;
     RECT  7.225 33.552 7.808 33.576 ;
     RECT  7.477 35.28 7.808 35.304 ;
     RECT  6.469 40.272 7.808 40.296 ;
     RECT  7.808 2.148 7.912 62.652 ;
     RECT  7.912 2.418 8.104 62.382 ;
     RECT  8.104 27.168 8.273 29.784 ;
     RECT  8.104 34.608 8.273 36.12 ;
     RECT  8.104 30.816 8.284 31.32 ;
     RECT  8.273 27.312 8.309 29.784 ;
     RECT  8.104 24.48 8.417 25.56 ;
     RECT  8.104 33.552 8.705 33.576 ;
     RECT  8.417 24.48 8.771 25.176 ;
     RECT  8.104 3.024 8.849 19.08 ;
     RECT  8.309 27.312 9.011 29.688 ;
     RECT  8.771 24.48 9.107 25.032 ;
     RECT  9.011 28.8 9.209 29.688 ;
     RECT  8.273 36.096 9.241 36.12 ;
     RECT  9.241 35.904 9.245 36.12 ;
     RECT  8.273 34.608 9.253 34.68 ;
     RECT  9.253 33.6 9.277 34.68 ;
     RECT  9.245 35.904 9.277 35.928 ;
     RECT  8.849 3.024 9.317 14.52 ;
     RECT  9.277 33.6 9.325 35.928 ;
     RECT  8.849 15.552 9.385 19.08 ;
     RECT  8.104 20.16 9.385 23.304 ;
     RECT  8.104 32.496 9.709 32.52 ;
     RECT  9.107 24.72 9.853 25.032 ;
     RECT  9.709 32.352 9.973 32.52 ;
     RECT  9.325 33.6 9.973 35.352 ;
     RECT  9.011 27.312 9.997 27.336 ;
     RECT  9.209 28.8 9.997 29.112 ;
     RECT  9.745 1.728 10.213 1.752 ;
     RECT  10.213 1.152 10.325 1.752 ;
     RECT  9.317 3.024 10.357 4.824 ;
     RECT  9.317 5.856 10.357 14.52 ;
     RECT  10.357 3.024 10.361 14.52 ;
     RECT  9.853 24.72 10.393 25.992 ;
     RECT  9.997 27.216 10.393 29.112 ;
     RECT  10.361 3.024 10.405 12.024 ;
     RECT  10.393 24.72 10.46 29.112 ;
     RECT  8.284 31.296 10.501 31.32 ;
     RECT  9.973 32.352 10.501 35.352 ;
     RECT  10.46 24.72 10.547 29.928 ;
     RECT  10.547 24.72 10.577 29.64 ;
     RECT  10.577 24.72 10.825 24.744 ;
     RECT  10.577 25.968 10.865 29.64 ;
     RECT  10.501 31.296 10.973 35.352 ;
     RECT  10.325 1.728 11.077 1.752 ;
     RECT  9.925 37.584 11.077 37.608 ;
     RECT  11.077 36.768 11.123 37.608 ;
     RECT  8.104 40.272 11.123 40.296 ;
     RECT  10.973 31.488 11.149 35.352 ;
     RECT  11.123 36.768 11.149 36.792 ;
     RECT  10.865 26.016 11.509 29.64 ;
     RECT  11.149 31.488 11.585 36.792 ;
     RECT  11.365 0.576 11.651 0.6 ;
     RECT  10.361 13.152 11.653 14.52 ;
     RECT  11.653 13.056 11.725 14.52 ;
     RECT  10.405 3.024 11.765 11.784 ;
     RECT  11.509 26.016 11.837 30.408 ;
     RECT  10.825 24.528 11.981 24.744 ;
     RECT  11.837 28.944 12.049 30.408 ;
     RECT  11.077 1.728 12.157 1.8 ;
     RECT  9.385 15.552 12.157 23.304 ;
     RECT  11.981 24.528 12.157 24.552 ;
     RECT  11.725 12.912 12.181 14.52 ;
     RECT  12.157 15.552 12.181 24.552 ;
     RECT  12.181 12.912 12.233 24.552 ;
     RECT  11.765 3.024 12.337 10.44 ;
     RECT  11.837 26.016 12.337 27.912 ;
     RECT  11.585 32.352 12.445 36.792 ;
     RECT  12.445 32.352 12.589 36.936 ;
     RECT  11.765 11.472 12.661 11.784 ;
     RECT  12.233 12.912 12.661 17.976 ;
     RECT  12.337 2.832 12.985 10.44 ;
     RECT  12.661 11.472 12.985 17.976 ;
     RECT  12.337 25.632 13.093 27.912 ;
     RECT  12.049 28.944 13.093 30.84 ;
     RECT  13.093 25.632 13.129 30.84 ;
     RECT  12.589 32.256 13.129 36.936 ;
     RECT  12.157 1.728 13.208 1.848 ;
     RECT  12.985 2.832 13.208 17.976 ;
     RECT  12.233 18.96 13.208 24.552 ;
     RECT  13.129 25.536 13.208 30.84 ;
     RECT  13.129 32.016 13.208 36.936 ;
     RECT  11.077 39.216 13.208 39.24 ;
     RECT  8.104 55.824 13.208 55.848 ;
     RECT  13.093 0.096 13.283 0.12 ;
     RECT  13.208 1.728 13.312 62.652 ;
     RECT  13.312 2.418 13.504 62.382 ;
     RECT  13.504 23.952 13.565 26.76 ;
     RECT  13.504 2.88 13.601 22.824 ;
     RECT  13.504 28.272 14.033 38.424 ;
     RECT  13.525 1.152 14.321 1.224 ;
     RECT  14.033 28.272 14.429 37.656 ;
     RECT  13.565 25.056 14.569 26.76 ;
     RECT  14.429 28.272 14.569 34.44 ;
     RECT  13.565 23.952 14.605 23.976 ;
     RECT  14.569 25.056 14.605 34.44 ;
     RECT  14.341 1.728 14.675 1.8 ;
     RECT  13.504 55.824 14.821 55.848 ;
     RECT  13.601 2.88 14.861 21.528 ;
     RECT  14.821 55.728 14.861 55.848 ;
     RECT  14.861 3.024 14.867 21.528 ;
     RECT  14.605 23.952 15.005 34.44 ;
     RECT  14.867 19.2 15.253 21.528 ;
     RECT  13.601 22.8 15.253 22.824 ;
     RECT  15.253 19.2 15.325 22.824 ;
     RECT  15.005 23.952 15.325 24.744 ;
     RECT  15.005 25.824 15.469 34.44 ;
     RECT  14.429 35.616 15.469 37.656 ;
     RECT  15.469 25.824 15.617 37.656 ;
     RECT  15.361 0.096 15.779 0.12 ;
     RECT  15.829 0.576 16.067 0.6 ;
     RECT  14.867 3.024 16.117 18.072 ;
     RECT  15.325 19.2 16.117 24.744 ;
     RECT  16.117 3.024 16.297 24.744 ;
     RECT  15.617 25.824 16.297 26.088 ;
     RECT  15.617 27.264 16.316 37.656 ;
     RECT  14.675 1.728 16.585 1.752 ;
     RECT  16.316 27.264 16.621 37.992 ;
     RECT  16.621 27.168 16.657 37.992 ;
     RECT  15.433 39.024 16.657 39.048 ;
     RECT  16.657 27.168 16.873 39.048 ;
     RECT  16.585 1.728 16.883 1.8 ;
     RECT  16.297 3.024 16.909 26.088 ;
     RECT  16.873 27.12 16.909 39.048 ;
     RECT  17.621 0.096 17.705 0.12 ;
     RECT  16.909 3.024 17.845 39.048 ;
     RECT  17.845 3.024 17.941 39.24 ;
     RECT  16.883 1.728 17.953 1.752 ;
     RECT  17.941 2.88 17.953 39.24 ;
     RECT  13.504 58.896 18.325 58.92 ;
     RECT  17.953 1.728 18.425 39.24 ;
     RECT  18.325 58.704 18.469 58.92 ;
     RECT  18.325 61.248 18.469 61.272 ;
     RECT  18.425 1.776 18.515 39.24 ;
     RECT  18.515 2.148 18.608 39.24 ;
     RECT  18.421 40.944 18.608 40.968 ;
     RECT  14.861 55.728 18.608 55.752 ;
     RECT  18.469 58.704 18.608 59.832 ;
     RECT  18.469 61.104 18.608 61.272 ;
     RECT  18.608 2.148 18.712 62.652 ;
     RECT  18.712 2.256 18.904 62.382 ;
     RECT  18.904 61.008 19.043 61.176 ;
     RECT  19.043 61.152 19.081 61.176 ;
     RECT  18.904 2.256 19.379 18.552 ;
     RECT  18.904 43.872 19.379 43.896 ;
     RECT  18.904 55.728 19.379 55.752 ;
     RECT  18.904 19.584 19.427 23.112 ;
     RECT  19.427 20.832 19.468 23.112 ;
     RECT  19.379 2.256 19.715 18.456 ;
     RECT  18.904 51.696 19.933 51.72 ;
     RECT  19.897 54.768 19.933 55.08 ;
     RECT  19.715 2.256 19.937 9 ;
     RECT  18.904 58.896 20.041 59.208 ;
     RECT  19.933 53.328 20.185 53.352 ;
     RECT  19.933 54.384 20.185 55.08 ;
     RECT  19.937 8.976 20.333 9 ;
     RECT  19.937 2.256 20.369 7.896 ;
     RECT  19.933 51.696 20.473 52.104 ;
     RECT  20.185 57.456 20.473 57.48 ;
     RECT  20.041 58.896 20.485 60.072 ;
     RECT  19.468 20.976 20.509 23.112 ;
     RECT  20.473 51.504 20.509 52.104 ;
     RECT  20.185 53.328 20.509 55.08 ;
     RECT  20.509 50.448 20.545 50.472 ;
     RECT  20.369 3.024 20.579 7.896 ;
     RECT  19.933 49.2 20.581 49.224 ;
     RECT  20.545 50.352 20.581 50.472 ;
     RECT  20.509 20.88 20.653 23.112 ;
     RECT  18.904 24.144 20.653 41.88 ;
     RECT  20.579 3.168 20.693 7.896 ;
     RECT  19.715 10.08 20.905 18.456 ;
     RECT  19.427 19.584 20.905 19.8 ;
     RECT  20.509 51.504 20.977 55.08 ;
     RECT  20.581 49.2 21.049 50.472 ;
     RECT  20.977 51.504 21.049 55.176 ;
     RECT  20.473 57.264 21.049 57.48 ;
     RECT  21.049 49.2 21.085 55.176 ;
     RECT  21.049 56.4 21.085 57.48 ;
     RECT  20.905 10.08 21.265 19.8 ;
     RECT  20.653 20.88 21.265 41.88 ;
     RECT  21.085 49.2 21.301 57.48 ;
     RECT  21.301 49.2 21.373 57.672 ;
     RECT  20.485 58.896 21.373 60.264 ;
     RECT  21.265 10.08 21.635 41.88 ;
     RECT  21.635 10.08 21.661 19.656 ;
     RECT  21.635 20.688 21.676 41.88 ;
     RECT  20.693 3.168 21.781 7.656 ;
     RECT  21.409 8.784 21.781 8.808 ;
     RECT  21.781 3.168 21.827 8.808 ;
     RECT  21.676 20.976 21.881 41.88 ;
     RECT  21.881 34.608 21.913 41.88 ;
     RECT  21.913 34.608 22.165 42.696 ;
     RECT  22.165 34.608 22.536 42.744 ;
     RECT  21.373 49.2 22.536 60.264 ;
     RECT  21.661 9.888 22.837 19.656 ;
     RECT  21.881 20.976 22.885 26.184 ;
     RECT  21.881 27.168 22.885 33.624 ;
     RECT  22.837 9.888 22.957 19.944 ;
     RECT  22.885 20.976 22.957 33.624 ;
     RECT  21.827 8.304 23.101 8.52 ;
     RECT  21.827 3.168 23.209 7.176 ;
     RECT  23.101 8.256 23.209 8.52 ;
     RECT  22.957 9.888 23.209 33.624 ;
     RECT  22.536 34.608 23.209 61.032 ;
     RECT  23.209 3.168 23.219 61.032 ;
     RECT  23.219 3.168 23.269 41.88 ;
     RECT  23.269 3.12 23.605 41.88 ;
     RECT  23.605 2.928 24.008 41.88 ;
     RECT  24.008 2.148 24.112 41.88 ;
     RECT  24.112 2.418 24.304 41.88 ;
     RECT  24.304 2.88 24.509 41.88 ;
     RECT  24.509 3.168 25.337 41.88 ;
     RECT  25.337 3.168 25.589 19.32 ;
     RECT  25.337 20.448 26.381 41.88 ;
     RECT  26.381 20.448 27.385 21.24 ;
     RECT  26.381 22.224 27.385 41.88 ;
     RECT  25.589 3.168 27.421 18.984 ;
     RECT  27.385 20.448 27.569 41.88 ;
     RECT  27.421 3.168 27.641 19.32 ;
     RECT  27.641 3.168 27.781 18.024 ;
     RECT  27.569 20.448 27.817 21.24 ;
     RECT  27.781 2.88 27.893 18.024 ;
     RECT  27.817 20.352 27.971 21.24 ;
     RECT  27.569 22.224 28.037 41.88 ;
     RECT  27.893 3.168 28.073 18.024 ;
     RECT  28.073 9.216 28.217 18.024 ;
     RECT  27.641 19.296 28.357 19.32 ;
     RECT  27.557 1.728 28.405 1.752 ;
     RECT  28.217 9.36 28.717 18.024 ;
     RECT  28.357 19.296 28.717 19.608 ;
     RECT  28.405 1.152 28.753 1.752 ;
     RECT  27.971 20.592 28.933 21.24 ;
     RECT  28.037 22.224 28.933 39.048 ;
     RECT  28.753 1.152 29.027 1.8 ;
     RECT  28.933 20.592 29.041 39.048 ;
     RECT  28.037 40.272 29.041 41.88 ;
     RECT  28.073 3.168 29.293 7.992 ;
     RECT  28.789 0.096 29.315 0.12 ;
     RECT  28.717 9.36 29.329 19.608 ;
     RECT  29.041 20.592 29.329 41.88 ;
     RECT  29.293 3.12 29.408 7.992 ;
     RECT  29.329 9.36 29.408 41.88 ;
     RECT  29.027 1.152 29.545 1.176 ;
     RECT  29.408 2.148 29.704 41.88 ;
     RECT  29.545 0.576 29.843 1.176 ;
     RECT  29.704 2.88 29.981 41.88 ;
     RECT  29.843 1.152 30.301 1.176 ;
     RECT  30.301 1.152 30.305 1.752 ;
     RECT  29.981 9.792 30.989 41.88 ;
     RECT  29.981 2.88 31.129 8.568 ;
     RECT  30.989 9.792 31.129 40.872 ;
     RECT  31.129 2.88 32.501 40.872 ;
     RECT  30.305 1.728 33.181 1.752 ;
     RECT  33.181 1.728 34.153 1.8 ;
     RECT  32.501 2.88 34.153 7.704 ;
     RECT  32.501 9.024 34.693 40.872 ;
     RECT  34.153 1.728 34.808 7.704 ;
     RECT  34.693 8.832 34.808 40.872 ;
     RECT  30.989 41.856 34.808 41.88 ;
     RECT  34.808 1.728 34.912 41.88 ;
     RECT  34.912 1.728 35.104 40.872 ;
     RECT  35.104 2.88 35.309 40.872 ;
     RECT  35.104 1.728 35.891 1.848 ;
     RECT  35.891 1.728 36.353 1.752 ;
     RECT  35.309 3.12 37.073 40.872 ;
     RECT  37.073 3.168 37.433 40.872 ;
     RECT  37.433 3.168 38.653 30.744 ;
     RECT  38.653 3.168 38.833 30.792 ;
     RECT  37.433 31.872 38.833 40.872 ;
     RECT  38.833 3.168 40.057 40.872 ;
     RECT  40.057 2.88 40.208 40.872 ;
     RECT  34.912 41.856 40.208 41.88 ;
     RECT  40.208 2.148 40.312 41.88 ;
     RECT  40.312 2.418 40.504 40.872 ;
     RECT  40.504 3.312 41.533 7.656 ;
     RECT  40.504 8.688 41.533 40.872 ;
     RECT  41.533 3.312 41.537 40.872 ;
     RECT  41.537 3.312 43.045 39.816 ;
     RECT  43.045 2.88 43.081 39.816 ;
     RECT  41.537 40.848 43.081 40.872 ;
     RECT  43.081 2.88 43.409 40.872 ;
     RECT  43.409 2.88 44.093 40.536 ;
     RECT  45.253 1.728 45.541 1.752 ;
     RECT  45.541 1.392 45.608 1.752 ;
     RECT  44.093 3.408 45.608 40.536 ;
     RECT  40.312 41.856 45.608 41.88 ;
     RECT  45.608 1.392 45.712 41.88 ;
     RECT  45.712 1.392 45.904 40.782 ;
     RECT  45.904 1.392 46.069 1.752 ;
     RECT  45.904 12.48 46.073 40.44 ;
     RECT  46.069 1.152 46.289 1.752 ;
     RECT  45.904 2.88 46.403 11.256 ;
     RECT  46.073 12.48 46.793 39.336 ;
     RECT  46.793 15.552 46.828 29.688 ;
     RECT  46.403 3.024 46.829 11.256 ;
     RECT  46.828 15.552 46.829 29.544 ;
     RECT  46.793 30.72 46.829 39.336 ;
     RECT  46.289 1.728 46.933 1.752 ;
     RECT  46.829 30.768 47.041 39.336 ;
     RECT  46.073 40.416 47.041 40.44 ;
     RECT  46.793 12.48 47.369 14.376 ;
     RECT  46.933 1.728 47.795 1.8 ;
     RECT  46.829 26.208 47.833 29.544 ;
     RECT  47.041 30.768 47.833 40.44 ;
     RECT  46.829 3.408 47.845 11.256 ;
     RECT  47.369 12.528 47.869 14.376 ;
     RECT  46.829 15.552 47.869 25.224 ;
     RECT  47.845 3.408 47.873 11.352 ;
     RECT  47.873 8.976 47.981 11.352 ;
     RECT  47.797 0.576 48.035 0.6 ;
     RECT  47.833 26.208 48.053 40.44 ;
     RECT  47.981 9.36 48.161 11.352 ;
     RECT  47.869 12.528 48.229 25.224 ;
     RECT  48.053 26.208 48.229 32.76 ;
     RECT  48.277 1.152 48.485 1.176 ;
     RECT  47.873 3.408 48.553 7.752 ;
     RECT  48.553 2.88 48.637 7.752 ;
     RECT  48.229 12.528 48.949 32.76 ;
     RECT  48.949 12.384 49.021 32.76 ;
     RECT  48.053 33.792 49.021 40.44 ;
     RECT  48.805 1.728 49.165 1.752 ;
     RECT  48.637 3.36 49.165 7.752 ;
     RECT  48.161 9.36 49.273 11.304 ;
     RECT  49.021 12.384 49.273 40.44 ;
     RECT  49.165 1.728 49.427 1.8 ;
     RECT  49.165 3.36 49.529 8.04 ;
     RECT  49.273 9.36 49.921 40.44 ;
     RECT  49.921 9.12 50.101 40.44 ;
     RECT  50.137 0.576 50.243 0.6 ;
     RECT  50.54 0.096 50.627 0.12 ;
     RECT  49.529 7.728 50.641 8.04 ;
     RECT  50.101 9.12 50.641 40.584 ;
     RECT  49.529 3.36 50.785 6.744 ;
     RECT  50.641 7.728 50.785 40.584 ;
     RECT  49.427 1.728 51.008 1.752 ;
     RECT  50.785 3.36 51.008 40.584 ;
     RECT  45.712 41.856 51.008 41.88 ;
     RECT  51.008 1.728 51.112 41.88 ;
     RECT  51.112 1.728 51.304 40.782 ;
     RECT  51.304 2.88 51.365 29.832 ;
     RECT  51.304 1.728 51.509 1.752 ;
     RECT  51.365 2.88 51.587 29.784 ;
     RECT  51.587 10.416 51.683 29.784 ;
     RECT  51.683 28.944 51.689 29.784 ;
     RECT  51.304 31.488 51.797 40.584 ;
     RECT  51.793 0.576 51.923 0.6 ;
     RECT  51.689 28.944 52.157 29.304 ;
     RECT  51.797 31.488 52.405 39.096 ;
     RECT  51.587 2.88 52.657 9.384 ;
     RECT  51.683 10.416 52.657 27.96 ;
     RECT  51.797 40.08 52.661 40.584 ;
     RECT  52.657 2.88 52.801 27.96 ;
     RECT  52.157 29.28 52.985 29.304 ;
     RECT  52.405 30.576 53.197 39.096 ;
     RECT  52.405 1.152 53.221 1.176 ;
     RECT  53.197 30.432 53.269 39.096 ;
     RECT  52.661 40.08 53.269 40.488 ;
     RECT  52.801 2.88 53.593 28.056 ;
     RECT  53.221 1.152 53.633 1.752 ;
     RECT  53.269 30.432 53.809 40.488 ;
     RECT  53.593 2.88 53.845 28.104 ;
     RECT  53.633 1.728 53.957 1.752 ;
     RECT  53.809 30.096 54.025 40.488 ;
     RECT  53.845 2.88 54.169 28.488 ;
     RECT  54.169 2.88 54.197 29.064 ;
     RECT  54.025 30.048 54.197 40.488 ;
     RECT  54.197 2.88 54.209 40.488 ;
     RECT  54.209 3.408 54.533 40.488 ;
     RECT  54.533 3.408 54.929 40.44 ;
     RECT  54.929 3.408 55.181 40.392 ;
     RECT  55.181 3.408 55.825 36.12 ;
     RECT  55.181 37.104 56.365 40.392 ;
     RECT  55.825 3.36 56.408 36.12 ;
     RECT  56.365 37.104 56.408 40.584 ;
     RECT  51.112 41.856 56.408 41.88 ;
     RECT  56.408 2.148 56.512 41.88 ;
     RECT  56.512 2.418 56.704 40.782 ;
     RECT  56.704 3.168 56.909 40.584 ;
     RECT  56.909 40.32 57.629 40.584 ;
     RECT  56.909 3.168 58.421 39.336 ;
     RECT  58.421 3.312 58.601 39.336 ;
     RECT  58.601 12.816 58.705 39.336 ;
     RECT  57.629 40.32 58.705 40.392 ;
     RECT  58.705 12.816 59.285 40.392 ;
     RECT  58.601 3.312 59.708 11.832 ;
     RECT  59.285 12.816 59.708 35.784 ;
     RECT  59.708 3.312 60.685 35.784 ;
     RECT  59.285 36.864 60.685 40.392 ;
     RECT  60.685 3.312 61.808 40.392 ;
     RECT  56.512 41.856 61.808 41.88 ;
     RECT  61.808 2.148 61.912 41.88 ;
     RECT  61.912 2.418 62.104 40.782 ;
     RECT  62.104 29.856 62.417 40.632 ;
     RECT  62.417 30.144 62.885 40.632 ;
     RECT  62.917 1.728 63.157 1.752 ;
     RECT  63.157 1.152 63.205 1.752 ;
     RECT  62.885 30.624 63.209 40.632 ;
     RECT  63.205 0.576 63.491 1.752 ;
     RECT  63.209 30.624 63.821 38.664 ;
     RECT  63.491 1.152 63.893 1.752 ;
     RECT  63.821 30.624 63.893 37.944 ;
     RECT  62.104 3.312 64.141 28.776 ;
     RECT  64.141 3.312 64.177 29.496 ;
     RECT  63.209 39.888 64.357 40.632 ;
     RECT  64.177 3.216 64.537 29.496 ;
     RECT  63.893 30.624 64.933 37.896 ;
     RECT  64.357 39.024 64.933 40.632 ;
     RECT  64.537 3.12 65.009 29.496 ;
     RECT  63.893 1.728 65.365 1.752 ;
     RECT  65.365 1.152 65.401 1.752 ;
     RECT  65.009 3.216 65.405 29.496 ;
     RECT  65.401 0.576 65.699 1.752 ;
     RECT  65.405 3.264 65.761 29.496 ;
     RECT  64.933 30.624 65.761 40.632 ;
     RECT  65.699 1.152 66.515 1.752 ;
     RECT  66.515 1.728 67.045 1.752 ;
     RECT  67.045 1.728 67.208 2.28 ;
     RECT  65.761 3.264 67.208 40.632 ;
     RECT  61.912 41.856 67.208 41.88 ;
     RECT  67.208 1.728 67.312 41.88 ;
     RECT  67.312 1.728 67.504 40.782 ;
     RECT  67.285 0.288 67.573 0.312 ;
     RECT  67.504 40.032 67.601 40.632 ;
     RECT  67.573 0.096 67.715 0.312 ;
     RECT  67.504 2.88 67.781 38.76 ;
     RECT  67.781 28.752 67.811 38.76 ;
     RECT  67.781 2.88 67.817 27.72 ;
     RECT  67.601 40.608 68.033 40.632 ;
     RECT  67.777 0.576 68.435 0.6 ;
     RECT  67.811 38.736 68.641 38.76 ;
     RECT  67.811 28.752 68.929 37.464 ;
     RECT  68.641 38.736 68.929 39.336 ;
     RECT  68.929 28.752 68.993 39.336 ;
     RECT  68.993 28.752 69.059 39.384 ;
     RECT  67.817 3.456 69.073 27.72 ;
     RECT  69.059 28.752 69.073 38.232 ;
     RECT  69.059 39.312 69.793 39.384 ;
     RECT  69.073 3.456 70.009 38.232 ;
     RECT  69.793 39.312 70.085 39.96 ;
     RECT  70.009 2.832 70.093 38.232 ;
     RECT  67.504 1.728 70.597 1.752 ;
     RECT  70.093 3.12 70.661 38.232 ;
     RECT  70.597 1.152 70.733 1.752 ;
     RECT  70.661 3.12 71.381 38.184 ;
     RECT  70.085 39.936 71.413 39.96 ;
     RECT  71.413 39.312 71.453 39.96 ;
     RECT  70.733 1.728 71.597 1.752 ;
     RECT  71.381 3.12 71.653 37.704 ;
     RECT  71.453 39.312 71.845 39.336 ;
     RECT  71.708 0.048 72.229 0.072 ;
     RECT  72.229 0.048 72.317 0.552 ;
     RECT  72.317 0.048 72.605 0.072 ;
     RECT  71.653 2.304 72.608 37.704 ;
     RECT  71.845 38.784 72.608 39.336 ;
     RECT  67.312 41.856 72.608 41.88 ;
     RECT  72.608 2.148 72.712 41.88 ;
     RECT  72.712 2.418 72.904 40.782 ;
     RECT  72.904 3.312 73.037 26.856 ;
     RECT  72.904 28.224 73.145 38.184 ;
     RECT  73.037 3.648 73.187 26.856 ;
     RECT  73.145 37.056 73.253 38.184 ;
     RECT  73.145 28.224 73.361 36.072 ;
     RECT  73.361 28.224 73.721 36.024 ;
     RECT  73.721 28.224 73.969 35.496 ;
     RECT  73.969 27.888 74.225 35.496 ;
     RECT  73.253 37.2 74.329 38.184 ;
     RECT  74.225 27.888 74.365 35.352 ;
     RECT  74.365 27.6 74.369 35.352 ;
     RECT  73.187 3.648 74.581 26.424 ;
     RECT  74.369 27.6 74.581 34.92 ;
     RECT  74.581 3.648 74.653 34.92 ;
     RECT  74.653 2.88 74.693 34.92 ;
     RECT  74.693 2.88 74.801 32.472 ;
     RECT  74.801 3.648 75.491 32.472 ;
     RECT  74.329 36.528 75.517 38.184 ;
     RECT  74.693 33.552 75.697 34.92 ;
     RECT  75.517 36.288 75.697 38.184 ;
     RECT  75.697 33.552 75.701 38.184 ;
     RECT  75.491 3.648 75.827 32.28 ;
     RECT  75.701 33.552 75.829 36.312 ;
     RECT  75.827 3.648 75.877 26.712 ;
     RECT  75.877 3.408 75.973 26.712 ;
     RECT  75.829 33.36 76.025 36.312 ;
     RECT  75.973 3.36 76.06 26.712 ;
     RECT  76.025 34.224 76.061 36.312 ;
     RECT  76.061 34.224 76.133 35.352 ;
     RECT  75.827 27.888 76.205 32.28 ;
     RECT  75.701 37.44 76.349 38.184 ;
     RECT  76.349 37.44 76.7 37.608 ;
     RECT  76.7 36.816 76.787 37.608 ;
     RECT  76.205 27.888 76.997 31.944 ;
     RECT  76.133 34.224 77.137 34.776 ;
     RECT  76.06 3.408 77.209 26.712 ;
     RECT  77.137 34.224 77.389 34.92 ;
     RECT  77.389 34.224 77.461 35.736 ;
     RECT  76.997 27.936 77.569 31.944 ;
     RECT  76.741 33.024 77.569 33.048 ;
     RECT  77.461 34.08 77.569 35.736 ;
     RECT  77.209 3.408 77.893 26.808 ;
     RECT  77.893 2.784 78.008 26.808 ;
     RECT  77.569 27.936 78.008 35.736 ;
     RECT  76.787 37.584 78.008 37.608 ;
     RECT  72.712 41.856 78.008 41.88 ;
     RECT  78.008 2.148 78.112 41.88 ;
     RECT  78.112 2.418 78.304 40.782 ;
     RECT  78.304 30.336 78.46 33.288 ;
     RECT  78.46 32.736 78.473 33.288 ;
     RECT  78.304 37.584 78.509 37.608 ;
     RECT  78.304 2.784 78.725 29.352 ;
     RECT  78.304 35.04 78.941 35.064 ;
     RECT  78.473 33.264 79.157 33.288 ;
     RECT  78.725 3.36 79.369 29.352 ;
     RECT  78.46 30.336 79.369 31.464 ;
     RECT  79.369 3.36 80.273 31.464 ;
     RECT  80.273 3.408 80.561 31.464 ;
     RECT  80.533 1.728 81.397 1.752 ;
     RECT  80.561 3.408 81.601 29.352 ;
     RECT  80.561 30.336 81.605 31.464 ;
     RECT  81.397 1.152 81.673 1.752 ;
     RECT  81.601 2.88 81.785 29.352 ;
     RECT  81.673 1.152 81.971 1.8 ;
     RECT  81.889 0.096 82.259 0.12 ;
     RECT  81.785 3.408 82.325 29.352 ;
     RECT  81.971 1.152 82.537 1.176 ;
     RECT  82.325 3.456 82.717 29.352 ;
     RECT  81.605 30.336 82.717 31.128 ;
     RECT  82.537 0.576 82.829 1.176 ;
     RECT  82.717 3.456 83.149 31.128 ;
     RECT  82.829 0.576 83.363 0.6 ;
     RECT  82.969 1.728 83.408 1.752 ;
     RECT  83.149 3.456 83.408 31.416 ;
     RECT  78.112 41.856 83.408 41.88 ;
     RECT  83.408 1.728 83.512 41.88 ;
     RECT  83.512 1.728 83.704 40.782 ;
     RECT  83.617 0.096 83.891 0.12 ;
     RECT  83.704 2.88 84.629 31.896 ;
     RECT  84.629 3.024 85.061 31.896 ;
     RECT  85.061 28.944 85.349 31.896 ;
     RECT  85.061 3.024 85.733 27.912 ;
     RECT  85.733 2.88 86.101 27.912 ;
     RECT  85.349 28.944 86.101 31.8 ;
     RECT  86.101 2.88 86.357 31.8 ;
     RECT  83.704 1.728 86.533 1.752 ;
     RECT  86.357 2.88 86.533 31.128 ;
     RECT  86.029 0.576 86.675 0.6 ;
     RECT  86.533 1.728 88.261 31.128 ;
     RECT  88.261 1.152 88.409 31.128 ;
     RECT  23.219 43.2 88.704 61.032 ;
     RECT  88.704 49.296 88.776 60.264 ;
     RECT  88.409 1.728 88.808 31.128 ;
     RECT  83.512 41.856 88.808 41.88 ;
     RECT  88.808 1.728 88.912 41.88 ;
     RECT  88.776 56.4 88.913 60.264 ;
     RECT  88.912 1.728 89.104 40.782 ;
     RECT  89.104 1.728 89.273 1.752 ;
     RECT  89.104 2.784 90.173 31.464 ;
     RECT  90.173 2.784 90.713 31.416 ;
     RECT  90.713 2.88 90.749 31.416 ;
     RECT  88.913 56.496 91.753 60.264 ;
     RECT  88.776 49.296 91.793 51.912 ;
     RECT  91.753 56.448 91.793 60.264 ;
     RECT  91.793 56.448 91.897 59.496 ;
     RECT  91.897 56.208 92.005 59.496 ;
     RECT  91.793 49.296 92.009 51.816 ;
     RECT  88.912 41.856 92.147 41.88 ;
     RECT  92.005 55.776 92.257 59.496 ;
     RECT  92.257 54.912 92.329 59.496 ;
     RECT  92.009 49.872 92.369 51.816 ;
     RECT  92.329 54.48 92.441 59.496 ;
     RECT  92.369 50.256 92.585 51.72 ;
     RECT  92.585 50.256 92.657 51.624 ;
     RECT  92.441 54.48 92.729 59.208 ;
     RECT  90.749 2.928 92.797 31.416 ;
     RECT  92.729 54.624 92.801 59.208 ;
     RECT  92.657 50.256 92.909 51.528 ;
     RECT  92.801 54.624 92.945 58.824 ;
     RECT  92.761 1.392 94.208 1.416 ;
     RECT  92.797 2.544 94.208 31.416 ;
     RECT  92.197 34.944 94.208 34.968 ;
     RECT  92.945 54.912 94.208 58.824 ;
     RECT  94.208 1.392 94.312 62.652 ;
     RECT  94.312 2.418 94.504 62.382 ;
     RECT  94.504 2.592 94.601 31.368 ;
     RECT  94.601 3.408 94.643 31.368 ;
     RECT  94.643 3.408 94.745 31.224 ;
     RECT  94.745 3.552 94.883 31.224 ;
     RECT  94.883 3.552 95.213 17.976 ;
     RECT  95.213 3.552 95.285 12.36 ;
     RECT  95.285 3.552 95.357 12.312 ;
     RECT  94.504 55.008 95.429 55.8 ;
     RECT  94.504 57.072 95.569 57.96 ;
     RECT  95.357 3.6 95.573 12.312 ;
     RECT  95.429 55.008 95.753 55.032 ;
     RECT  95.569 57.024 95.753 57.96 ;
     RECT  95.213 13.392 96.181 17.976 ;
     RECT  94.883 19.056 96.181 31.224 ;
     RECT  95.573 3.696 96.289 12.312 ;
     RECT  96.181 13.392 96.289 31.224 ;
     RECT  96.289 3.696 96.509 31.224 ;
     RECT  96.509 3.696 96.725 30.792 ;
     RECT  96.725 18.528 96.761 30.792 ;
     RECT  96.725 3.696 97.013 17.352 ;
     RECT  97.013 3.696 97.477 13.8 ;
     RECT  96.761 19.056 97.481 30.744 ;
     RECT  97.481 19.056 97.868 30.696 ;
     RECT  97.013 15.168 97.909 17.352 ;
     RECT  97.868 18.96 97.909 30.696 ;
     RECT  97.477 3.408 98.197 13.8 ;
     RECT  94.312 1.392 98.243 1.416 ;
     RECT  97.909 15.168 98.485 30.696 ;
     RECT  98.197 2.64 98.629 13.8 ;
     RECT  98.485 14.976 98.629 30.696 ;
     RECT  98.444 1.104 98.684 1.128 ;
     RECT  98.684 0.528 98.771 1.128 ;
     RECT  98.629 2.64 99.277 30.696 ;
     RECT  99.277 2.304 99.608 30.696 ;
     RECT  94.504 35.04 99.608 35.064 ;
     RECT  99.608 2.148 99.712 62.652 ;
     RECT  98.771 1.104 99.829 1.128 ;
     RECT  99.712 2.148 99.829 62.382 ;
     RECT  99.829 1.104 99.904 62.382 ;
     RECT  99.904 1.104 100.037 2.04 ;
     RECT  99.904 3.12 100.325 30.84 ;
     RECT  100.037 1.104 100.405 1.176 ;
     RECT  100.325 3.84 100.613 30.84 ;
     RECT  100.405 0.576 100.649 1.176 ;
     RECT  100.613 3.936 101.045 30.84 ;
     RECT  101.045 3.936 101.225 16.584 ;
     RECT  101.045 17.568 101.261 30.84 ;
     RECT  100.693 0.096 101.657 0.168 ;
     RECT  101.261 17.712 101.657 20.184 ;
     RECT  101.225 3.936 101.729 13.56 ;
     RECT  100.649 1.152 101.797 1.176 ;
     RECT  101.261 21.168 101.909 30.84 ;
     RECT  101.657 18.288 101.945 20.184 ;
     RECT  101.729 3.936 102.017 13.512 ;
     RECT  101.945 18.288 102.053 18.312 ;
     RECT  102.017 3.936 102.157 11.976 ;
     RECT  102.037 2.304 102.161 2.328 ;
     RECT  102.157 3.408 102.161 11.976 ;
     RECT  101.909 22.272 102.341 30.84 ;
     RECT  101.225 16.56 102.589 16.584 ;
     RECT  99.904 35.04 102.589 35.064 ;
     RECT  102.161 3.408 102.593 7.896 ;
     RECT  102.589 35.04 102.629 35.208 ;
     RECT  101.225 14.784 102.697 15.576 ;
     RECT  102.589 16.56 102.697 17.016 ;
     RECT  102.697 14.784 102.805 17.016 ;
     RECT  102.805 14.784 102.841 17.112 ;
     RECT  102.161 8.88 103.091 11.976 ;
     RECT  103.091 9.264 103.093 11.976 ;
     RECT  102.017 13.296 103.093 13.512 ;
     RECT  102.841 14.784 103.129 17.64 ;
     RECT  101.797 0.576 103.141 1.176 ;
     RECT  101.945 19.728 103.148 20.184 ;
     RECT  101.909 21.168 103.148 21.24 ;
     RECT  103.129 14.784 103.189 18.552 ;
     RECT  103.148 19.728 103.189 21.24 ;
     RECT  102.341 22.272 103.189 30.744 ;
     RECT  103.141 0.096 103.241 1.176 ;
     RECT  103.189 14.784 103.313 30.744 ;
     RECT  103.313 19.248 103.421 30.744 ;
     RECT  103.093 9.264 103.525 13.512 ;
     RECT  103.313 14.784 103.525 17.64 ;
     RECT  103.525 9.264 103.609 17.64 ;
     RECT  102.593 7.344 103.633 7.896 ;
     RECT  103.241 0.528 103.717 1.176 ;
     RECT  103.609 11.376 103.889 17.64 ;
     RECT  103.421 22.752 103.889 28.392 ;
     RECT  102.593 3.408 103.921 6.264 ;
     RECT  103.633 7.344 103.921 7.992 ;
     RECT  103.717 0.528 104.051 1.224 ;
     RECT  103.609 9.264 104.137 10.152 ;
     RECT  103.921 3.408 104.173 7.992 ;
     RECT  104.197 43.824 104.245 44.472 ;
     RECT  102.629 35.184 104.293 35.208 ;
     RECT  104.173 3.408 104.389 8.136 ;
     RECT  104.137 9.12 104.389 10.152 ;
     RECT  103.889 11.424 104.389 17.64 ;
     RECT  103.421 19.248 104.389 21.672 ;
     RECT  103.889 25.056 104.389 28.392 ;
     RECT  103.421 29.616 104.389 30.744 ;
     RECT  104.051 0.576 104.429 1.224 ;
     RECT  104.396 62.4 104.437 62.424 ;
     RECT  104.389 25.056 104.497 28.488 ;
     RECT  104.389 29.616 104.497 31.416 ;
     RECT  104.389 11.424 104.569 21.672 ;
     RECT  103.889 22.752 104.569 23.928 ;
     RECT  104.429 1.152 104.605 1.224 ;
     RECT  104.605 1.152 105.008 1.752 ;
     RECT  104.389 3.408 105.008 10.152 ;
     RECT  104.569 11.424 105.008 23.928 ;
     RECT  104.497 25.056 105.008 31.416 ;
     RECT  104.293 35.184 105.008 36.024 ;
     RECT  104.065 37.344 105.008 37.368 ;
     RECT  104.197 40.704 105.008 41.832 ;
     RECT  104.245 43.824 105.008 45 ;
     RECT  103.813 46.176 105.008 46.2 ;
     RECT  104.389 48.432 105.008 48.456 ;
     RECT  104.348 49.776 105.008 49.8 ;
     RECT  104.101 51.024 105.008 51.048 ;
     RECT  104.389 53.088 105.008 53.112 ;
     RECT  104.348 54.096 105.008 54.12 ;
     RECT  104.029 55.248 105.008 55.272 ;
     RECT  104.437 57.408 105.008 57.432 ;
     RECT  104.396 58.656 105.008 58.68 ;
     RECT  104.101 59.664 105.008 59.688 ;
     RECT  104.437 62.208 105.008 62.424 ;
     RECT  105.008 1.152 105.112 62.652 ;
     RECT  105.101 0.096 105.185 0.12 ;
     RECT  105.112 2.304 105.304 62.382 ;
     RECT  105.112 1.152 105.401 1.224 ;
     RECT  105.304 9.12 105.401 21.192 ;
     RECT  105.401 9.12 105.473 21.144 ;
     RECT  105.473 15.264 105.509 21.144 ;
     RECT  105.401 1.152 105.596 1.176 ;
     RECT  105.509 18.144 105.653 21.144 ;
     RECT  105.596 0.528 105.683 1.176 ;
     RECT  105.304 55.872 105.731 56.328 ;
     RECT  105.304 40.464 105.761 40.968 ;
     RECT  105.304 30.048 105.797 30.408 ;
     RECT  105.473 9.12 105.869 13.896 ;
     RECT  105.509 15.264 106.01 17.112 ;
     RECT  105.304 43.296 106.049 43.848 ;
     RECT  105.304 48.432 106.049 48.456 ;
     RECT  105.304 34.704 106.067 36.024 ;
     RECT  105.304 39.312 106.067 39.336 ;
     RECT  105.304 57.408 106.085 57.432 ;
     RECT  105.761 40.464 106.093 40.488 ;
     RECT  105.304 52.416 106.113 53.112 ;
     RECT  105.304 62.208 106.113 62.232 ;
     RECT  105.683 1.104 106.121 1.176 ;
     RECT  105.653 18.192 106.121 21.144 ;
     RECT  105.797 30.048 106.121 30.072 ;
     RECT  106.067 35.184 106.265 35.208 ;
     RECT  106.213 0.096 106.337 0.12 ;
     RECT  106.121 19.824 106.405 21.144 ;
     RECT  105.304 22.224 106.405 23.64 ;
     RECT  105.304 24.624 106.405 24.648 ;
     RECT  105.304 3.6 106.445 7.752 ;
     RECT  106.01 15.264 106.445 17.064 ;
     RECT  106.121 1.104 106.499 1.128 ;
     RECT  105.304 26.208 106.585 29.064 ;
     RECT  105.304 61.2 106.621 61.224 ;
     RECT  106.121 18.192 106.697 18.84 ;
     RECT  106.445 3.984 106.733 7.752 ;
     RECT  105.869 9.12 106.765 13.848 ;
     RECT  106.7 0.528 106.787 0.552 ;
     RECT  106.405 19.824 106.837 21.192 ;
     RECT  106.405 22.224 106.837 24.648 ;
     RECT  106.837 19.824 106.905 24.648 ;
     RECT  106.765 8.832 106.985 13.848 ;
     RECT  106.905 19.824 107.021 19.944 ;
     RECT  106.621 61.2 107.021 62.184 ;
     RECT  106.445 15.936 107.165 17.064 ;
     RECT  106.905 20.928 107.201 24.648 ;
     RECT  105.304 2.304 107.273 2.328 ;
     RECT  107.201 20.928 107.363 23.64 ;
     RECT  106.585 25.968 107.413 29.064 ;
     RECT  107.363 20.928 107.417 23.4 ;
     RECT  107.413 25.728 107.417 29.064 ;
     RECT  107.417 25.728 107.453 28.44 ;
     RECT  106.985 8.832 107.489 11.448 ;
     RECT  106.733 7.392 107.521 7.752 ;
     RECT  107.489 8.832 107.521 9.096 ;
     RECT  107.521 7.392 107.525 9.096 ;
     RECT  105.731 56.304 107.633 56.328 ;
     RECT  106.049 43.296 107.653 43.32 ;
     RECT  107.453 25.728 107.665 27.528 ;
     RECT  107.201 24.624 107.669 24.648 ;
     RECT  105.304 33.6 107.669 33.624 ;
     RECT  105.304 38.16 107.669 38.184 ;
     RECT  106.113 52.416 107.669 52.44 ;
     RECT  107.021 61.2 107.669 61.224 ;
     RECT  107.653 42.912 107.699 43.32 ;
     RECT  107.621 46.752 107.705 46.776 ;
     RECT  107.699 42.912 107.74 42.936 ;
     RECT  107.525 7.584 107.741 9.096 ;
     RECT  106.697 18.192 107.741 18.216 ;
     RECT  107.665 25.632 107.777 27.528 ;
     RECT  106.733 3.984 107.845 6.12 ;
     RECT  107.165 15.936 107.881 16.584 ;
     RECT  107.777 25.632 107.921 27.48 ;
     RECT  107.845 3.552 107.941 6.12 ;
     RECT  107.021 19.92 107.993 19.944 ;
     RECT  107.417 21.12 107.993 23.4 ;
     RECT  107.993 21.36 108.065 23.4 ;
     RECT  107.881 15.84 108.133 16.584 ;
     RECT  107.741 9.072 108.137 9.096 ;
     RECT  107.741 7.584 108.227 7.992 ;
     RECT  108.065 22.176 108.227 23.4 ;
     RECT  107.921 25.632 108.241 27.336 ;
     RECT  107.489 10.224 108.277 11.448 ;
     RECT  107.941 3.552 108.281 6.312 ;
     RECT  108.281 3.552 108.389 6.12 ;
     RECT  108.227 7.584 108.389 7.944 ;
     RECT  108.389 3.552 108.425 3.576 ;
     RECT  108.133 15.6 108.497 16.584 ;
     RECT  108.389 4.656 108.569 6.12 ;
     RECT  108.389 7.728 108.605 7.944 ;
     RECT  108.241 24.672 108.637 27.336 ;
     RECT  108.497 15.744 108.641 15.864 ;
     RECT  108.637 23.904 108.713 27.336 ;
     RECT  108.277 10.224 108.749 12.36 ;
     RECT  108.749 10.848 108.785 12.36 ;
     RECT  108.227 22.176 108.821 22.488 ;
     RECT  108.713 25.632 108.821 25.992 ;
     RECT  108.821 25.632 108.893 25.656 ;
     RECT  108.605 7.92 108.929 7.944 ;
     RECT  108.785 11.376 108.965 12.36 ;
     RECT  108.641 15.84 108.965 15.864 ;
     RECT  108.713 27.312 108.965 27.336 ;
     RECT  108.821 22.464 109.001 22.488 ;
     RECT  106.985 13.824 109.073 13.848 ;
     RECT  108.569 5.088 109.109 6.12 ;
     RECT  108.713 23.904 109.109 23.928 ;
     RECT  108.965 12.336 109.253 12.36 ;
     RECT  109.109 5.328 109.757 6.12 ;
     RECT  109.757 6.096 109.865 6.12 ;
     RECT  109.141 3.408 110.081 3.432 ;
     RECT  112.201 1.536 112.284 1.56 ;
     RECT  112.201 2.688 112.284 2.712 ;
     RECT  112.201 3.84 112.284 3.864 ;
     RECT  110.581 4.992 112.284 5.016 ;
     RECT  112.201 6.144 112.284 6.168 ;
     RECT  111.121 7.248 112.284 7.272 ;
     RECT  111.121 8.4 112.284 8.424 ;
     RECT  112.201 9.552 112.284 9.576 ;
     RECT  111.121 10.704 112.284 10.728 ;
     RECT  110.581 11.856 112.284 11.88 ;
     RECT  111.121 12.96 112.284 12.984 ;
     RECT  110.581 14.112 112.284 14.136 ;
     RECT  110.581 15.264 112.284 15.288 ;
     RECT  112.201 16.416 112.284 16.44 ;
     RECT  111.121 17.568 112.284 17.592 ;
     RECT  112.201 18.672 112.284 18.696 ;
     RECT  110.581 19.824 112.284 19.848 ;
     RECT  110.581 20.976 112.284 21 ;
     RECT  110.545 22.128 112.284 22.152 ;
     RECT  111.121 23.232 112.284 23.256 ;
     RECT  112.201 24.384 112.284 24.408 ;
     RECT  111.697 25.536 112.284 25.56 ;
     RECT  110.005 26.688 112.284 26.712 ;
     RECT  111.121 27.84 112.284 27.864 ;
     RECT  111.121 28.944 112.284 28.968 ;
     RECT  110.581 30.096 112.284 30.12 ;
     RECT  111.697 31.248 112.284 31.272 ;
     RECT  110.545 32.4 112.284 32.424 ;
     RECT  110.581 33.552 112.284 33.576 ;
     RECT  110.581 34.656 112.284 34.68 ;
     RECT  110.581 35.808 112.284 35.832 ;
     RECT  112.201 36.96 112.284 36.984 ;
     RECT  111.121 38.112 112.284 38.136 ;
     RECT  111.121 39.216 112.284 39.24 ;
     RECT  112.201 40.368 112.284 40.392 ;
     RECT  110.005 41.52 112.284 41.544 ;
     RECT  111.121 42.672 112.284 42.696 ;
     RECT  110.581 43.824 112.284 43.848 ;
     RECT  110.581 44.928 112.284 44.952 ;
     RECT  110.005 46.08 112.284 46.104 ;
     RECT  112.201 47.232 112.284 47.256 ;
     RECT  110.545 48.384 112.284 48.408 ;
     RECT  110.545 49.536 112.284 49.56 ;
     RECT  110.545 50.64 112.284 50.664 ;
     RECT  110.005 51.792 112.284 51.816 ;
     RECT  111.121 52.944 112.284 52.968 ;
     RECT  110.545 54.096 112.284 54.12 ;
     RECT  112.201 55.248 112.284 55.272 ;
     RECT  110.005 56.352 112.284 56.376 ;
     RECT  111.121 57.504 112.284 57.528 ;
     RECT  111.121 58.656 112.284 58.68 ;
     RECT  110.581 59.808 112.284 59.832 ;
     RECT  110.545 60.912 112.284 60.936 ;
     RECT  110.005 62.064 112.284 62.088 ;
     RECT  110.545 63.216 112.284 63.24 ;
    LAYER M5 ;
     RECT  62.928 0.016 71.496 0.037 ;
     RECT  98.208 0.016 106.776 0.563 ;
     RECT  98.208 0.563 106.488 0.611 ;
     RECT  101.232 0.611 106.488 0.659 ;
     RECT  103.44 0.659 106.488 1.139 ;
     RECT  62.928 0.037 72.36 1.187 ;
     RECT  80.544 0.016 89.112 1.187 ;
     RECT  98.208 0.611 100.152 1.187 ;
     RECT  101.232 0.659 102.36 1.187 ;
     RECT  103.44 1.139 105.96 1.187 ;
     RECT  103.728 1.187 105.96 1.235 ;
     RECT  98.208 1.187 99.864 1.427 ;
     RECT  9.936 0.016 18.504 1.763 ;
     RECT  27.6 0.016 36.168 1.763 ;
     RECT  45.264 0.016 53.832 1.763 ;
     RECT  62.928 1.187 62.952 1.763 ;
     RECT  64.032 1.187 72.36 1.763 ;
     RECT  80.544 1.187 81.96 1.763 ;
     RECT  83.04 1.187 89.112 1.763 ;
     RECT  11.328 1.763 11.352 1.811 ;
     RECT  14.64 1.763 14.664 1.811 ;
     RECT  16.848 1.763 16.872 1.811 ;
     RECT  28.992 1.763 29.712 1.811 ;
     RECT  33.408 1.763 33.432 1.811 ;
     RECT  34.752 1.763 35.88 1.811 ;
     RECT  45.6 1.763 49.416 1.811 ;
     RECT  81.936 1.763 81.96 1.811 ;
     RECT  86.88 1.763 86.904 1.811 ;
     RECT  12.432 1.763 13.512 1.859 ;
     RECT  34.8 1.811 35.88 1.859 ;
     RECT  3.36 0.037 3.912 2.137 ;
     RECT  17.952 1.763 18.504 2.137 ;
     RECT  71.664 1.763 72.36 2.137 ;
     RECT  7.8 2.137 7.92 2.151 ;
     RECT  17.952 2.137 18.72 2.151 ;
     RECT  24 2.137 24.12 2.151 ;
     RECT  40.2 2.137 40.32 2.151 ;
     RECT  56.4 2.137 56.52 2.151 ;
     RECT  61.8 2.137 61.92 2.151 ;
     RECT  71.664 2.137 72.72 2.151 ;
     RECT  78 2.137 78.12 2.151 ;
     RECT  94.2 2.137 94.32 2.151 ;
     RECT  99.024 1.427 99.864 2.151 ;
     RECT  2.4 2.137 3.912 2.245 ;
     RECT  67.056 1.763 67.608 2.291 ;
     RECT  102.048 1.187 102.072 2.339 ;
     RECT  104.544 1.235 105.96 2.339 ;
     RECT  17.952 2.151 18.912 2.915 ;
     RECT  45.6 1.811 46.392 2.915 ;
     RECT  48.576 1.811 48.6 2.915 ;
     RECT  50.592 1.763 52.728 2.915 ;
     RECT  67.2 2.291 67.608 2.915 ;
     RECT  83.4 1.763 84.456 2.915 ;
     RECT  85.776 1.763 85.8 2.915 ;
     RECT  13.104 1.859 13.512 3.061 ;
     RECT  24 2.151 24.312 3.109 ;
     RECT  45.6 2.915 45.912 3.685 ;
     RECT  23.28 3.109 24.312 3.875 ;
     RECT  2.4 2.245 3.96 3.925 ;
     RECT  5.136 3.253 5.16 3.925 ;
     RECT  31.488 3.877 31.512 3.925 ;
     RECT  33.12 3.877 33.144 3.925 ;
     RECT  12.336 3.061 13.512 3.971 ;
     RECT  14.736 3.061 14.76 3.971 ;
     RECT  16.656 3.061 16.68 3.971 ;
     RECT  71.664 2.151 72.912 4.019 ;
     RECT  70.032 2.821 70.056 4.117 ;
     RECT  104.544 2.339 105.312 4.213 ;
     RECT  75.984 3.349 76.008 4.307 ;
     RECT  24 3.875 24.312 4.309 ;
     RECT  67.2 2.915 67.512 4.309 ;
     RECT  83.4 2.915 83.712 4.357 ;
     RECT  2.4 3.925 4.008 4.501 ;
     RECT  5.04 3.925 5.16 4.501 ;
     RECT  20.544 3.013 20.568 4.501 ;
     RECT  24 4.309 24.408 4.501 ;
     RECT  61.8 2.151 62.112 4.501 ;
     RECT  67.2 4.309 67.992 4.501 ;
     RECT  37.968 4.117 37.992 4.549 ;
     RECT  70.032 4.117 70.68 4.595 ;
     RECT  71.712 4.019 72.912 4.595 ;
     RECT  31.488 3.925 33.144 4.643 ;
     RECT  104.544 4.213 106.2 4.643 ;
     RECT  24 4.501 24.504 4.645 ;
     RECT  31.488 4.643 31.512 4.691 ;
     RECT  45.072 3.685 45.912 4.693 ;
     RECT  33.072 4.643 33.144 4.741 ;
     RECT  40.2 2.151 40.512 4.741 ;
     RECT  45.072 4.693 46.008 4.741 ;
     RECT  17.088 4.597 17.112 4.787 ;
     RECT  33.072 4.741 33.192 4.787 ;
     RECT  37.968 4.549 38.136 4.837 ;
     RECT  72.096 4.595 72.912 4.837 ;
     RECT  74.352 4.789 74.376 4.837 ;
     RECT  83.184 4.357 83.712 4.883 ;
     RECT  78 2.151 78.312 4.885 ;
     RECT  104.544 4.643 105.576 4.885 ;
     RECT  47.328 4.501 47.352 4.933 ;
     RECT  50.592 2.915 51.312 4.933 ;
     RECT  52.464 4.261 52.488 4.933 ;
     RECT  33.12 4.787 33.192 4.979 ;
     RECT  37.968 4.837 38.28 4.979 ;
     RECT  40.2 4.741 40.92 4.979 ;
     RECT  61.8 4.501 62.952 4.979 ;
     RECT  88.8 1.763 89.112 5.029 ;
     RECT  86.256 4.933 86.28 5.075 ;
     RECT  2.4 4.501 5.832 5.077 ;
     RECT  29.4 1.811 29.712 5.077 ;
     RECT  61.8 4.979 62.112 5.077 ;
     RECT  103.776 4.885 105.576 5.123 ;
     RECT  18.6 2.915 18.912 5.125 ;
     RECT  48.672 3.349 48.696 5.125 ;
     RECT  12.144 4.501 12.168 5.171 ;
     RECT  48.48 5.125 48.696 5.171 ;
     RECT  72.096 4.837 74.376 5.171 ;
     RECT  99.024 2.151 99.912 5.171 ;
     RECT  37.968 4.979 37.992 5.173 ;
     RECT  43.296 4.069 43.32 5.219 ;
     RECT  44.736 4.741 46.008 5.219 ;
     RECT  58.128 4.501 58.152 5.219 ;
     RECT  48.48 5.171 48.504 5.267 ;
     RECT  2.4 5.077 6.744 5.269 ;
     RECT  7.8 2.151 8.112 5.269 ;
     RECT  47.04 4.933 47.352 5.315 ;
     RECT  18.432 5.125 18.912 5.317 ;
     RECT  34.8 1.859 35.112 5.317 ;
     RECT  37.824 5.173 37.992 5.365 ;
     RECT  44.736 5.219 45.912 5.461 ;
     RECT  66.816 4.501 67.992 5.605 ;
     RECT  28.128 5.077 28.152 5.651 ;
     RECT  83.4 4.883 83.712 5.653 ;
     RECT  2.4 5.269 8.112 5.747 ;
     RECT  33.12 4.979 33.144 5.747 ;
     RECT  50.592 4.933 52.488 5.747 ;
     RECT  40.2 4.979 40.512 5.893 ;
     RECT  6.336 5.747 8.112 5.941 ;
     RECT  34.8 5.317 35.256 5.941 ;
     RECT  34.8 5.941 35.352 5.989 ;
     RECT  88.368 5.029 89.112 6.035 ;
     RECT  13.2 3.971 13.512 6.037 ;
     RECT  103.776 5.123 105.312 6.083 ;
     RECT  24 4.645 25.08 6.085 ;
     RECT  37.104 5.365 37.992 6.179 ;
     RECT  42.288 3.829 42.312 6.181 ;
     RECT  34.8 5.989 35.448 6.275 ;
     RECT  66.432 5.605 67.992 6.275 ;
     RECT  42.288 6.181 42.456 6.323 ;
     RECT  44.448 5.461 45.912 6.323 ;
     RECT  107.952 4.213 107.976 6.323 ;
     RECT  72.6 5.171 74.376 6.325 ;
     RECT  93.168 3.925 93.192 6.325 ;
     RECT  66.912 6.275 67.992 6.371 ;
     RECT  20.544 4.501 21 6.373 ;
     RECT  59.664 5.461 59.688 6.421 ;
     RECT  83.4 5.653 84.408 6.515 ;
     RECT  18 5.317 18.912 6.565 ;
     RECT  20.544 6.373 21.096 6.565 ;
     RECT  92.208 6.325 93.192 6.565 ;
     RECT  99.6 5.171 99.912 6.565 ;
     RECT  58.992 6.421 59.688 6.611 ;
     RECT  72.24 6.325 74.376 6.709 ;
     RECT  2.4 5.747 5.112 6.805 ;
     RECT  6.336 5.941 8.52 6.805 ;
     RECT  42.432 6.323 42.456 6.805 ;
     RECT  105 6.083 105.312 6.805 ;
     RECT  78 4.885 78.648 6.851 ;
     RECT  47.328 5.315 47.352 6.899 ;
     RECT  61.584 5.077 62.112 6.899 ;
     RECT  34.8 6.275 35.208 6.901 ;
     RECT  29.184 5.077 29.712 6.947 ;
     RECT  72.24 6.709 74.472 6.995 ;
     RECT  13.2 6.037 14.28 7.043 ;
     RECT  23.808 6.085 25.08 7.139 ;
     RECT  79.872 4.501 79.896 7.189 ;
     RECT  88.8 6.035 89.112 7.237 ;
     RECT  94.2 2.151 94.512 7.237 ;
     RECT  74.352 6.995 74.472 7.331 ;
     RECT  50.592 5.747 52.248 7.333 ;
     RECT  2.4 6.805 9.144 7.379 ;
     RECT  18 6.565 21.096 7.381 ;
     RECT  67.056 6.371 67.992 7.381 ;
     RECT  76.896 6.229 76.92 7.381 ;
     RECT  76.56 7.381 76.92 7.427 ;
     RECT  74.448 7.331 74.472 7.429 ;
     RECT  31.008 6.229 31.032 7.475 ;
     RECT  48.96 6.229 48.984 7.475 ;
     RECT  18 7.381 21.816 7.523 ;
     RECT  32.448 6.181 32.472 7.523 ;
     RECT  56.4 2.151 56.712 7.525 ;
     RECT  34.704 6.901 35.208 7.619 ;
     RECT  105 6.805 106.008 7.667 ;
     RECT  83.4 6.515 84.072 7.765 ;
     RECT  67.056 7.381 68.568 7.859 ;
     RECT  79.872 7.189 80.28 7.861 ;
     RECT  103.776 6.083 103.8 7.861 ;
     RECT  72.24 6.995 72.912 7.907 ;
     RECT  103.536 7.861 103.8 7.907 ;
     RECT  13.2 7.043 13.512 7.909 ;
     RECT  29.4 6.947 29.712 7.909 ;
     RECT  37.104 6.179 37.848 7.909 ;
     RECT  61.8 6.899 62.112 8.005 ;
     RECT  74.448 7.429 75.24 8.147 ;
     RECT  76.56 7.427 76.584 8.147 ;
     RECT  81.984 7.381 82.008 8.147 ;
     RECT  86.304 5.653 86.328 8.147 ;
     RECT  2.4 7.379 8.52 8.339 ;
     RECT  90.528 7.909 90.552 8.341 ;
     RECT  90.288 8.341 90.552 8.387 ;
     RECT  5.568 8.339 8.52 8.389 ;
     RECT  5.568 8.389 9.192 8.435 ;
     RECT  56.4 7.525 57.384 8.435 ;
     RECT  59.664 6.611 59.688 8.435 ;
     RECT  88.368 7.237 89.112 8.437 ;
     RECT  98.688 6.565 99.912 8.437 ;
     RECT  5.568 8.435 8.112 8.483 ;
     RECT  42.432 6.805 42.648 8.485 ;
     RECT  67.2 7.859 68.568 8.485 ;
     RECT  69.648 5.317 69.672 8.485 ;
     RECT  70.704 6.133 70.728 8.485 ;
     RECT  2.4 8.339 4.536 8.579 ;
     RECT  24 7.139 25.08 8.579 ;
     RECT  34.8 7.619 35.208 8.579 ;
     RECT  78 6.851 78.504 8.579 ;
     RECT  37.008 7.909 37.848 8.675 ;
     RECT  50.592 7.333 53.016 8.675 ;
     RECT  12.48 7.909 13.512 8.771 ;
     RECT  21.792 7.523 21.816 8.819 ;
     RECT  39.888 5.893 40.512 8.819 ;
     RECT  31.392 7.573 31.752 8.867 ;
     RECT  103.536 7.907 103.56 8.869 ;
     RECT  79.872 7.861 80.328 9.011 ;
     RECT  61.632 8.005 62.112 9.013 ;
     RECT  79.872 9.011 80.28 9.013 ;
     RECT  5.568 8.483 5.592 9.059 ;
     RECT  4.464 8.579 4.536 9.155 ;
     RECT  37.104 8.675 37.848 9.155 ;
     RECT  67.2 8.485 70.776 9.155 ;
     RECT  88.368 8.437 89.208 9.155 ;
     RECT  94.2 7.237 95.496 9.155 ;
     RECT  9.168 8.435 9.192 9.251 ;
     RECT  65.52 8.485 65.544 9.301 ;
     RECT  64.992 9.301 65.544 9.347 ;
     RECT  74.448 8.147 74.472 9.349 ;
     RECT  15.936 7.189 15.96 9.395 ;
     RECT  78 8.579 78.456 9.395 ;
     RECT  72.6 7.907 72.912 9.397 ;
     RECT  86.352 8.485 86.376 9.397 ;
     RECT  10.368 5.605 10.392 9.493 ;
     RECT  34.8 8.579 35.112 9.541 ;
     RECT  18 7.523 20.568 9.587 ;
     RECT  67.2 9.155 70.728 9.587 ;
     RECT  61.632 9.013 63.048 9.589 ;
     RECT  38.88 6.805 38.904 9.637 ;
     RECT  92.112 6.565 93.192 9.637 ;
     RECT  103.056 8.869 103.56 9.683 ;
     RECT  44.736 6.323 45.912 9.731 ;
     RECT  67.2 9.587 70.104 9.731 ;
     RECT  83.4 7.765 84.984 9.731 ;
     RECT  18 9.587 19.08 9.781 ;
     RECT  42.432 8.485 42.744 9.781 ;
     RECT  83.4 9.731 84.072 9.827 ;
     RECT  98.688 8.437 100.344 9.827 ;
     RECT  74.448 9.349 74.52 9.925 ;
     RECT  31.344 9.013 31.368 9.971 ;
     RECT  28.992 7.909 29.712 10.067 ;
     RECT  64.992 9.347 65.016 10.069 ;
     RECT  86.352 9.397 86.664 10.115 ;
     RECT  34.416 9.541 35.112 10.117 ;
     RECT  37.968 9.637 38.904 10.117 ;
     RECT  40.2 8.819 40.512 10.117 ;
     RECT  59.568 9.781 59.592 10.211 ;
     RECT  37.968 10.117 40.512 10.213 ;
     RECT  50.592 8.675 52.248 10.213 ;
     RECT  10.224 9.493 10.392 10.259 ;
     RECT  79.776 9.013 80.28 10.259 ;
     RECT  37.056 10.213 40.512 10.307 ;
     RECT  37.056 10.307 37.992 10.403 ;
     RECT  34.416 10.117 35.208 10.405 ;
     RECT  27.36 9.109 27.384 10.547 ;
     RECT  86.352 10.115 86.376 10.643 ;
     RECT  91.728 9.637 93.192 10.643 ;
     RECT  47.856 10.261 47.88 10.741 ;
     RECT  88.656 9.155 89.208 10.741 ;
     RECT  90.288 8.387 90.312 10.741 ;
     RECT  50.112 10.213 52.248 10.835 ;
     RECT  64.848 10.069 65.016 10.835 ;
     RECT  103.536 9.683 103.56 10.883 ;
     RECT  39.36 10.307 40.512 10.931 ;
     RECT  74.448 9.925 74.712 10.931 ;
     RECT  39.792 10.931 40.512 11.027 ;
     RECT  72.48 9.397 72.912 11.027 ;
     RECT  91.728 10.643 93 11.123 ;
     RECT  2.4 8.579 3.384 11.125 ;
     RECT  4.512 9.155 4.536 11.125 ;
     RECT  69.168 9.731 70.104 11.173 ;
     RECT  88.656 10.741 90.312 11.173 ;
     RECT  29.4 10.067 29.712 11.317 ;
     RECT  30.768 10.933 30.792 11.317 ;
     RECT  33.024 9.061 33.048 11.317 ;
     RECT  47.808 10.741 47.88 11.363 ;
     RECT  33.024 11.317 33.144 11.365 ;
     RECT  34.416 10.405 35.448 11.365 ;
     RECT  60.72 9.589 63.048 11.365 ;
     RECT  60.72 11.365 63.528 11.413 ;
     RECT  105 7.667 105.312 11.413 ;
     RECT  84.816 10.741 84.84 11.459 ;
     RECT  88.656 11.173 90.6 11.459 ;
     RECT  42.096 9.781 42.744 11.509 ;
     RECT  50.112 10.835 51.576 11.509 ;
     RECT  52.56 11.461 52.584 11.509 ;
     RECT  56.4 8.435 56.712 11.509 ;
     RECT  57.84 11.269 57.864 11.509 ;
     RECT  96.192 10.981 96.216 11.509 ;
     RECT  98.688 9.827 99.912 11.509 ;
     RECT  24 8.579 24.408 11.557 ;
     RECT  87.6 10.789 87.624 11.651 ;
     RECT  13.2 8.771 13.512 11.653 ;
     RECT  79.872 10.259 80.28 11.653 ;
     RECT  96.192 11.509 96.84 11.699 ;
     RECT  98.688 11.509 100.824 11.795 ;
     RECT  33.024 11.365 35.448 11.797 ;
     RECT  50.064 11.509 51.576 11.939 ;
     RECT  104.88 11.413 105.312 11.941 ;
     RECT  10.368 10.259 10.392 12.035 ;
     RECT  55.248 10.981 55.272 12.035 ;
     RECT  92.112 11.123 93 12.035 ;
     RECT  42.048 11.509 42.744 12.181 ;
     RECT  50.064 11.939 51.312 12.181 ;
     RECT  52.56 11.509 53.112 12.227 ;
     RECT  59.76 11.413 63.528 12.227 ;
     RECT  69.168 11.173 70.152 12.277 ;
     RECT  78 9.395 78.312 12.277 ;
     RECT  79.488 11.653 80.28 12.277 ;
     RECT  23.088 11.557 24.408 12.469 ;
     RECT  22.752 12.469 24.408 12.515 ;
     RECT  68.976 12.277 70.152 12.515 ;
     RECT  56.4 11.509 57.864 12.517 ;
     RECT  94.2 9.155 94.872 12.517 ;
     RECT  90.576 11.459 90.6 12.563 ;
     RECT  98.688 11.795 100.008 12.563 ;
     RECT  16.752 11.701 16.776 12.565 ;
     RECT  17.808 9.781 19.08 12.565 ;
     RECT  37.584 10.403 37.992 12.755 ;
     RECT  24 12.515 24.408 12.757 ;
     RECT  16.752 12.565 19.08 12.803 ;
     RECT  74.448 10.931 74.472 12.805 ;
     RECT  78 12.277 80.28 12.853 ;
     RECT  67.2 9.731 67.992 12.949 ;
     RECT  37.968 12.755 37.992 12.997 ;
     RECT  78 12.853 80.328 13.043 ;
     RECT  29.4 11.317 30.792 13.045 ;
     RECT  98.688 12.563 99.912 13.045 ;
     RECT  9.12 11.125 9.144 13.091 ;
     RECT  29.4 13.045 30.84 13.091 ;
     RECT  54.096 8.821 54.12 13.091 ;
     RECT  60.72 12.227 63.528 13.091 ;
     RECT  103.248 11.941 105.312 13.091 ;
     RECT  22.752 12.515 22.776 13.139 ;
     RECT  32.448 11.797 35.448 13.139 ;
     RECT  37.968 12.997 38.232 13.139 ;
     RECT  82.128 8.149 82.152 13.141 ;
     RECT  83.4 9.827 83.712 13.141 ;
     RECT  34.704 13.139 35.112 13.187 ;
     RECT  42.048 12.181 43.224 13.187 ;
     RECT  78 13.043 80.28 13.187 ;
     RECT  67.104 12.949 67.992 13.189 ;
     RECT  69.84 12.515 70.152 13.285 ;
     RECT  82.128 13.141 83.712 13.331 ;
     RECT  40.08 11.027 40.512 13.333 ;
     RECT  64.848 10.835 64.872 13.333 ;
     RECT  24 12.757 24.456 13.427 ;
     RECT  66.912 13.189 67.992 13.429 ;
     RECT  29.4 13.091 29.712 13.477 ;
     RECT  84.864 12.517 84.888 13.523 ;
     RECT  66.624 13.429 67.992 13.619 ;
     RECT  88.8 11.459 89.256 13.619 ;
     RECT  101.088 13.285 101.112 13.621 ;
     RECT  100.896 13.621 101.112 13.667 ;
     RECT  74.448 12.805 75.144 13.669 ;
     RECT  5.712 11.941 5.736 13.715 ;
     RECT  30.816 13.091 30.84 13.715 ;
     RECT  32.448 13.139 33.72 13.715 ;
     RECT  42.384 13.187 43.224 13.715 ;
     RECT  49.92 12.181 51.312 13.715 ;
     RECT  74.352 13.669 75.144 13.715 ;
     RECT  93.84 12.517 94.872 13.715 ;
     RECT  53.088 12.227 53.112 13.763 ;
     RECT  100.896 13.667 100.92 13.763 ;
     RECT  96.192 11.699 96.216 13.811 ;
     RECT  6.72 8.483 8.112 13.859 ;
     RECT  56.4 12.517 57.912 13.859 ;
     RECT  106.56 13.141 106.584 13.859 ;
     RECT  98.64 13.045 99.912 13.861 ;
     RECT  13.2 11.653 13.608 13.907 ;
     RECT  2.4 11.125 4.536 13.955 ;
     RECT  69.84 13.285 70.872 14.051 ;
     RECT  42.384 13.715 42.408 14.099 ;
     RECT  4.032 13.955 4.536 14.147 ;
     RECT  91.008 12.613 91.08 14.195 ;
     RECT  7.008 13.859 8.112 14.197 ;
     RECT  25.536 13.237 25.56 14.197 ;
     RECT  28.848 13.477 29.712 14.197 ;
     RECT  39.936 13.333 40.512 14.197 ;
     RECT  4.032 14.147 4.344 14.243 ;
     RECT  32.448 13.715 32.472 14.291 ;
     RECT  66.912 13.619 67.992 14.291 ;
     RECT  91.008 14.195 91.032 14.291 ;
     RECT  53.04 14.197 53.064 14.339 ;
     RECT  28.848 14.197 30.36 14.435 ;
     RECT  67.2 14.291 67.992 14.581 ;
     RECT  88.8 13.619 89.208 14.581 ;
     RECT  64.848 13.333 64.968 14.675 ;
     RECT  24 13.427 24.408 14.771 ;
     RECT  56.4 13.859 57 14.773 ;
     RECT  28.848 14.435 30.264 14.867 ;
     RECT  61.8 13.091 63.528 14.867 ;
     RECT  93.84 13.715 94.632 14.867 ;
     RECT  72.6 11.027 72.912 14.869 ;
     RECT  58.416 14.245 58.728 14.915 ;
     RECT  98.64 13.861 100.008 14.965 ;
     RECT  78 13.187 80.232 15.109 ;
     RECT  94.08 14.867 94.632 15.155 ;
     RECT  20.544 9.587 20.568 15.157 ;
     RECT  22.032 14.773 22.056 15.157 ;
     RECT  86.112 14.341 86.136 15.203 ;
     RECT  103.92 13.091 105.312 15.253 ;
     RECT  17.808 12.803 19.08 15.299 ;
     RECT  38.208 13.139 38.232 15.299 ;
     RECT  14.832 15.253 14.856 15.349 ;
     RECT  47.808 11.363 47.832 15.349 ;
     RECT  49.152 14.773 49.176 15.349 ;
     RECT  27.6 13.621 27.624 15.397 ;
     RECT  98.64 14.965 100.104 15.397 ;
     RECT  18.432 15.299 19.08 15.443 ;
     RECT  25.44 14.197 25.8 15.443 ;
     RECT  27.312 15.397 27.624 15.443 ;
     RECT  88.656 14.581 89.208 15.443 ;
     RECT  14.832 15.349 15.24 15.491 ;
     RECT  20.544 15.157 22.056 15.491 ;
     RECT  39.936 14.197 40.728 15.491 ;
     RECT  64.848 14.675 64.872 15.493 ;
     RECT  47.808 15.349 49.176 15.539 ;
     RECT  44.88 9.731 45.912 15.637 ;
     RECT  7.008 14.197 8.232 15.779 ;
     RECT  98.592 15.397 100.104 15.781 ;
     RECT  42.288 15.685 42.312 15.827 ;
     RECT  78 15.109 80.856 15.877 ;
     RECT  82.128 13.331 82.152 15.877 ;
     RECT  98.592 15.781 100.92 15.923 ;
     RECT  47.808 15.539 48.312 15.971 ;
     RECT  50.4 13.715 51.312 15.973 ;
     RECT  88.656 15.443 89.112 15.973 ;
     RECT  78 15.877 82.152 16.019 ;
     RECT  84.912 14.773 84.936 16.019 ;
     RECT  2.4 13.955 2.712 16.021 ;
     RECT  7.536 15.779 8.232 16.021 ;
     RECT  24 14.771 24.312 16.021 ;
     RECT  61.8 14.867 62.112 16.069 ;
     RECT  63.168 14.867 63.528 16.069 ;
     RECT  74.352 13.715 74.472 16.069 ;
     RECT  60.72 13.091 60.744 16.165 ;
     RECT  103.92 15.253 105.816 16.259 ;
     RECT  12.192 15.253 12.216 16.261 ;
     RECT  13.2 13.907 13.512 16.261 ;
     RECT  27.312 15.443 27.336 16.261 ;
     RECT  67.2 14.581 68.664 16.261 ;
     RECT  69.84 14.051 70.392 16.261 ;
     RECT  67.2 16.261 70.392 16.403 ;
     RECT  28.848 14.867 29.712 16.453 ;
     RECT  92.112 12.035 92.232 16.501 ;
     RECT  64.608 15.493 64.872 16.547 ;
     RECT  20.544 15.491 21.528 16.549 ;
     RECT  55.872 14.773 57 16.595 ;
     RECT  96.624 14.917 96.648 16.595 ;
     RECT  98.592 15.923 100.104 16.595 ;
     RECT  33.696 13.715 33.72 16.645 ;
     RECT  39.936 15.491 40.512 16.645 ;
     RECT  60.576 16.165 60.744 16.741 ;
     RECT  61.8 16.069 63.528 16.741 ;
     RECT  60.576 16.741 63.528 16.787 ;
     RECT  64.848 16.547 64.872 16.787 ;
     RECT  88.464 15.973 89.112 16.789 ;
     RECT  98.688 16.595 100.104 16.883 ;
     RECT  64.992 16.789 65.016 16.885 ;
     RECT  76.944 16.597 76.968 16.931 ;
     RECT  87.648 16.789 89.112 16.931 ;
     RECT  58.416 14.915 58.44 16.933 ;
     RECT  64.992 16.885 65.208 16.979 ;
     RECT  39.936 16.645 41.304 16.981 ;
     RECT  18.432 15.443 18.912 17.029 ;
     RECT  19.92 16.549 21.528 17.029 ;
     RECT  7.536 16.021 9.096 17.075 ;
     RECT  15.216 15.491 15.24 17.075 ;
     RECT  26.4 16.261 27.336 17.075 ;
     RECT  39.936 16.981 41.496 17.075 ;
     RECT  12.192 16.261 13.512 17.123 ;
     RECT  33.072 16.645 33.72 17.123 ;
     RECT  65.184 16.979 65.208 17.123 ;
     RECT  17.28 15.925 17.304 17.171 ;
     RECT  18.432 17.029 21.528 17.171 ;
     RECT  38.736 16.117 38.76 17.171 ;
     RECT  78 16.019 81.672 17.171 ;
     RECT  91.824 16.501 92.232 17.171 ;
     RECT  48.96 17.077 48.984 17.219 ;
     RECT  60.816 16.787 63.528 17.219 ;
     RECT  30.816 17.077 30.84 17.221 ;
     RECT  40.032 17.075 41.496 17.267 ;
     RECT  28.512 16.453 29.712 17.363 ;
     RECT  98.784 16.883 100.104 17.363 ;
     RECT  18.432 17.171 19.368 17.413 ;
     RECT  94.08 15.155 94.512 17.413 ;
     RECT  72.432 14.869 72.912 17.459 ;
     RECT  28.944 17.363 29.712 17.461 ;
     RECT  30.816 17.221 30.936 17.461 ;
     RECT  2.4 16.021 2.856 17.507 ;
     RECT  7.536 17.075 9 17.507 ;
     RECT  92.112 17.171 92.232 17.509 ;
     RECT  56.4 16.595 57 17.605 ;
     RECT  58.08 16.933 58.44 17.605 ;
     RECT  88.464 16.931 89.112 17.605 ;
     RECT  28.944 17.461 30.936 17.651 ;
     RECT  56.4 17.605 58.44 17.651 ;
     RECT  61.8 17.219 63.528 17.651 ;
     RECT  67.2 16.403 68.664 17.653 ;
     RECT  74.112 16.069 74.472 17.653 ;
     RECT  20.544 17.171 21.528 17.699 ;
     RECT  26.4 17.075 26.424 17.699 ;
     RECT  24 16.021 24.984 17.747 ;
     RECT  66.72 17.653 68.664 17.843 ;
     RECT  67.2 17.843 68.664 17.893 ;
     RECT  74.112 17.653 74.52 17.893 ;
     RECT  76.032 17.509 76.056 17.893 ;
     RECT  7.536 17.507 8.112 17.939 ;
     RECT  28.944 17.651 29.832 17.939 ;
     RECT  56.4 17.651 57.288 17.939 ;
     RECT  88.464 17.605 89.304 17.941 ;
     RECT  12.192 17.123 12.216 17.989 ;
     RECT  22.992 16.981 23.016 18.035 ;
     RECT  30.816 17.651 30.936 18.083 ;
     RECT  74.112 17.893 74.664 18.083 ;
     RECT  88.464 17.941 90.072 18.131 ;
     RECT  20.544 17.699 21.48 18.179 ;
     RECT  58.416 17.651 58.44 18.181 ;
     RECT  72.48 17.459 72.912 18.181 ;
     RECT  76.032 17.893 76.968 18.181 ;
     RECT  78 17.171 80.856 18.181 ;
     RECT  92.112 17.509 92.328 18.181 ;
     RECT  94.032 17.413 94.512 18.181 ;
     RECT  76.032 18.181 80.856 18.227 ;
     RECT  4.32 14.243 4.344 18.229 ;
     RECT  49.968 15.973 51.312 18.229 ;
     RECT  53.664 17.989 53.688 18.229 ;
     RECT  67.2 17.893 68.712 18.229 ;
     RECT  69.84 16.403 70.392 18.229 ;
     RECT  4.32 18.229 4.488 18.275 ;
     RECT  30.816 18.083 30.84 18.323 ;
     RECT  52.896 18.229 53.688 18.371 ;
     RECT  74.112 18.083 74.568 18.371 ;
     RECT  76.944 18.227 80.856 18.371 ;
     RECT  11.952 17.989 12.216 18.419 ;
     RECT  74.304 18.371 74.472 18.419 ;
     RECT  18.24 17.413 19.368 18.467 ;
     RECT  18.432 18.467 19.368 18.563 ;
     RECT  67.2 18.229 70.392 18.563 ;
     RECT  61.8 17.651 62.112 18.565 ;
     RECT  28.944 17.939 29.712 18.707 ;
     RECT  77.232 18.371 80.856 18.707 ;
     RECT  93.984 18.181 94.512 18.757 ;
     RECT  104.88 16.259 105.816 18.757 ;
     RECT  61.68 18.565 62.112 18.805 ;
     RECT  58.416 18.181 58.776 18.851 ;
     RECT  86.016 16.453 86.04 18.851 ;
     RECT  87.648 18.421 87.672 18.851 ;
     RECT  72.48 18.181 73.032 18.901 ;
     RECT  61.632 18.805 62.112 18.947 ;
     RECT  21.456 18.179 21.48 18.995 ;
     RECT  97.92 18.133 97.944 18.995 ;
     RECT  101.664 18.277 101.688 18.995 ;
     RECT  61.68 18.947 62.112 19.045 ;
     RECT  63.504 17.651 63.528 19.045 ;
     RECT  14.832 17.605 14.856 19.235 ;
     RECT  65.328 19.045 65.448 19.235 ;
     RECT  24 17.747 24.312 19.237 ;
     RECT  72.432 18.901 73.032 19.237 ;
     RECT  83.28 13.331 83.712 19.237 ;
     RECT  61.68 19.045 63.528 19.283 ;
     RECT  93.984 18.757 94.872 19.283 ;
     RECT  36.96 19.189 36.984 19.331 ;
     RECT  33.264 17.123 33.72 19.333 ;
     RECT  34.8 13.187 35.112 19.333 ;
     RECT  53.664 18.371 53.688 19.379 ;
     RECT  65.328 19.235 65.352 19.379 ;
     RECT  49.968 18.229 51.912 19.427 ;
     RECT  104.784 18.757 105.816 19.427 ;
     RECT  33.264 19.333 35.112 19.475 ;
     RECT  61.68 19.283 62.664 19.523 ;
     RECT  18.432 18.563 18.912 19.571 ;
     RECT  92.112 18.181 92.904 19.571 ;
     RECT  23.472 19.237 24.312 19.619 ;
     RECT  69.84 18.563 70.392 19.619 ;
     RECT  104.784 19.427 105.48 19.667 ;
     RECT  104.88 19.667 105.48 19.811 ;
     RECT  82.608 19.237 83.712 19.813 ;
     RECT  85.392 19.765 85.416 19.813 ;
     RECT  71.76 19.237 73.032 19.861 ;
     RECT  74.4 18.419 74.472 19.861 ;
     RECT  77.232 18.707 78.888 19.861 ;
     RECT  79.872 18.707 80.856 19.861 ;
     RECT  15.888 19.669 15.912 19.909 ;
     RECT  44.64 15.637 45.912 19.957 ;
     RECT  11.952 18.419 11.976 20.003 ;
     RECT  44.448 19.957 45.912 20.003 ;
     RECT  77.232 19.861 80.856 20.003 ;
     RECT  56.4 17.939 56.856 20.053 ;
     RECT  18.48 19.571 18.912 20.149 ;
     RECT  88.8 18.131 90.072 20.149 ;
     RECT  88.368 20.149 90.072 20.195 ;
     RECT  78 20.003 80.856 20.291 ;
     RECT  18.48 20.149 19.416 20.339 ;
     RECT  61.68 19.523 62.112 20.389 ;
     RECT  94.2 19.283 94.872 20.389 ;
     RECT  15.888 19.909 16.008 20.435 ;
     RECT  61.152 20.389 62.112 20.531 ;
     RECT  94.2 20.389 95.16 20.531 ;
     RECT  15.984 20.435 16.008 20.579 ;
     RECT  44.448 20.003 44.472 20.579 ;
     RECT  49.968 19.427 51.312 20.579 ;
     RECT  75.792 19.813 75.816 20.579 ;
     RECT  82.608 19.813 85.416 20.579 ;
     RECT  69.84 19.619 70.344 20.677 ;
     RECT  71.76 19.861 74.472 20.677 ;
     RECT  88.368 20.195 89.112 20.677 ;
     RECT  21.6 19.909 21.624 20.723 ;
     RECT  4.464 18.275 4.488 20.725 ;
     RECT  71.76 20.677 74.52 20.819 ;
     RECT  87.936 20.677 89.112 20.819 ;
     RECT  18.6 20.339 19.416 20.867 ;
     RECT  7.8 17.939 8.112 20.869 ;
     RECT  69.84 20.677 70.728 20.915 ;
     RECT  72.6 20.819 74.52 20.915 ;
     RECT  69.84 20.915 70.2 20.917 ;
     RECT  96.336 20.773 96.36 21.011 ;
     RECT  104.88 19.811 105.432 21.011 ;
     RECT  76.32 20.677 76.344 21.059 ;
     RECT  38.256 20.533 38.28 21.107 ;
     RECT  106.848 20.533 106.872 21.107 ;
     RECT  4.464 20.725 5.112 21.155 ;
     RECT  17.04 19.285 17.064 21.155 ;
     RECT  83.28 20.579 85.416 21.155 ;
     RECT  88.368 20.819 89.112 21.155 ;
     RECT  24 19.619 24.312 21.157 ;
     RECT  33.696 19.475 35.112 21.205 ;
     RECT  27.936 20.341 27.96 21.251 ;
     RECT  67.2 18.563 68.664 21.253 ;
     RECT  69.648 20.917 70.2 21.253 ;
     RECT  78 20.291 80.664 21.299 ;
     RECT  33.36 21.205 35.112 21.347 ;
     RECT  7.8 20.869 8.904 21.541 ;
     RECT  5.088 21.155 5.112 21.637 ;
     RECT  29.4 18.707 29.712 21.637 ;
     RECT  92.112 19.571 92.232 21.637 ;
     RECT  94.2 20.531 95.064 21.683 ;
     RECT  103.2 19.093 103.224 21.683 ;
     RECT  58.416 18.851 58.44 21.731 ;
     RECT  56.4 20.053 57.288 21.733 ;
     RECT  61.8 20.531 62.112 21.733 ;
     RECT  60.96 21.733 62.112 21.781 ;
     RECT  79.872 21.299 80.664 21.781 ;
     RECT  7.488 21.541 8.904 21.829 ;
     RECT  43.248 21.637 43.272 21.829 ;
     RECT  72.6 20.915 74.472 21.875 ;
     RECT  40.032 17.267 40.512 21.925 ;
     RECT  72.6 21.875 74.424 21.925 ;
     RECT  45.6 20.003 45.912 21.973 ;
     RECT  7.488 21.829 9.048 22.019 ;
     RECT  99.6 17.363 100.104 22.021 ;
     RECT  18.6 20.867 18.912 22.165 ;
     RECT  20.4 21.925 20.424 22.165 ;
     RECT  34.8 21.347 35.112 22.165 ;
     RECT  41.616 21.925 41.64 22.165 ;
     RECT  47.808 15.971 47.832 22.165 ;
     RECT  88.8 21.155 89.112 22.165 ;
     RECT  5.088 21.637 5.784 22.211 ;
     RECT  67.2 21.253 70.2 22.213 ;
     RECT  54.192 21.589 54.648 22.259 ;
     RECT  11.568 20.725 11.592 22.307 ;
     RECT  72.336 21.925 74.424 22.307 ;
     RECT  67.104 22.213 70.2 22.355 ;
     RECT  76.944 21.061 76.968 22.357 ;
     RECT  54.528 22.259 54.648 22.405 ;
     RECT  56.4 21.733 58.152 22.405 ;
     RECT  39.888 21.925 40.512 22.451 ;
     RECT  24 21.157 24.984 22.453 ;
     RECT  67.2 22.355 70.2 22.453 ;
     RECT  71.184 21.973 71.208 22.453 ;
     RECT  91.2 21.637 92.232 22.499 ;
     RECT  33.36 21.347 33.384 22.547 ;
     RECT  60.384 21.781 62.112 22.547 ;
     RECT  22.848 19.909 22.872 22.549 ;
     RECT  7.8 22.019 9.048 22.595 ;
     RECT  24 22.453 25.128 22.595 ;
     RECT  96.288 22.405 96.312 22.595 ;
     RECT  46.896 22.165 47.832 22.597 ;
     RECT  63.744 21.781 63.768 22.645 ;
     RECT  67.2 22.453 71.208 22.691 ;
     RECT  101.712 22.165 101.736 22.691 ;
     RECT  83.28 21.155 83.712 22.693 ;
     RECT  41.616 22.165 42.216 22.739 ;
     RECT  44.928 21.973 45.912 22.739 ;
     RECT  72.6 22.307 74.424 22.739 ;
     RECT  18.6 22.165 20.424 22.741 ;
     RECT  79.872 21.781 81.48 22.835 ;
     RECT  34.8 22.165 35.352 22.837 ;
     RECT  66.096 21.061 66.12 22.931 ;
     RECT  76.848 22.357 76.968 22.933 ;
     RECT  78 21.299 78.312 22.933 ;
     RECT  83.232 22.693 83.712 22.933 ;
     RECT  79.872 22.835 80.664 22.979 ;
     RECT  42.192 22.739 42.216 22.981 ;
     RECT  43.248 21.829 43.32 22.981 ;
     RECT  54.528 22.405 58.152 22.981 ;
     RECT  46.896 22.597 48.696 23.027 ;
     RECT  27.888 22.741 27.912 23.125 ;
     RECT  29.28 21.637 29.712 23.125 ;
     RECT  31.104 23.077 31.128 23.125 ;
     RECT  99.504 22.021 100.104 23.125 ;
     RECT  34.272 22.837 35.352 23.171 ;
     RECT  83.232 22.933 83.928 23.171 ;
     RECT  95.904 23.029 95.928 23.171 ;
     RECT  61.8 22.547 62.112 23.221 ;
     RECT  63.264 22.645 63.768 23.221 ;
     RECT  72.6 22.739 73.08 23.267 ;
     RECT  39.936 22.451 40.512 23.315 ;
     RECT  50.4 20.579 51.312 23.317 ;
     RECT  52.56 22.789 52.584 23.317 ;
     RECT  76.848 22.933 78.312 23.317 ;
     RECT  83.232 23.171 83.712 23.363 ;
     RECT  40.032 23.315 40.512 23.365 ;
     RECT  106.512 22.453 106.536 23.365 ;
     RECT  108.192 7.957 108.216 23.365 ;
     RECT  71.184 22.691 71.208 23.411 ;
     RECT  94.2 21.683 94.872 23.411 ;
     RECT  106.512 23.365 108.216 23.411 ;
     RECT  54.528 22.981 58.296 23.461 ;
     RECT  27.888 23.125 31.128 23.557 ;
     RECT  27.744 23.557 31.128 23.603 ;
     RECT  54.528 23.461 58.392 23.603 ;
     RECT  59.808 22.549 60.264 23.651 ;
     RECT  88.8 22.165 89.88 23.653 ;
     RECT  50.4 23.317 52.584 23.747 ;
     RECT  54.528 23.603 58.296 23.747 ;
     RECT  61.8 23.221 63.768 23.747 ;
     RECT  76.848 23.317 78.84 23.795 ;
     RECT  88.512 23.653 89.88 23.795 ;
     RECT  22.848 22.549 22.968 23.797 ;
     RECT  67.2 22.691 70.2 23.797 ;
     RECT  28.752 23.603 31.128 23.843 ;
     RECT  66.144 22.981 66.168 23.845 ;
     RECT  67.2 23.797 70.728 23.845 ;
     RECT  28.752 23.843 31.032 23.891 ;
     RECT  66.144 23.845 70.728 23.891 ;
     RECT  59.808 23.651 59.832 23.893 ;
     RECT  25.632 22.741 25.656 23.939 ;
     RECT  16.992 23.077 17.016 23.941 ;
     RECT  18.192 22.741 20.424 23.941 ;
     RECT  22.656 23.797 22.968 23.941 ;
     RECT  24 22.595 24.312 23.941 ;
     RECT  70.704 23.891 70.728 23.987 ;
     RECT  97.344 22.789 97.368 23.989 ;
     RECT  54.624 23.747 58.296 24.131 ;
     RECT  97.2 23.989 97.368 24.131 ;
     RECT  40.032 23.365 41.016 24.133 ;
     RECT  42.192 22.981 43.32 24.133 ;
     RECT  34.8 23.171 35.352 24.181 ;
     RECT  83.28 23.363 83.712 24.181 ;
     RECT  40.032 24.133 41.208 24.323 ;
     RECT  42.192 24.133 43.416 24.323 ;
     RECT  42.192 24.323 43.272 24.371 ;
     RECT  40.032 24.323 40.512 24.373 ;
     RECT  34.8 24.181 36.264 24.421 ;
     RECT  77.472 23.795 78.84 24.421 ;
     RECT  79.872 22.979 79.896 24.421 ;
     RECT  5.76 22.211 5.784 24.467 ;
     RECT  80.928 24.325 80.952 24.467 ;
     RECT  7.8 22.595 8.112 24.469 ;
     RECT  27.744 23.603 27.768 24.469 ;
     RECT  45.6 22.739 45.912 24.469 ;
     RECT  59.616 23.893 59.832 24.469 ;
     RECT  88.8 23.795 89.88 24.515 ;
     RECT  99.504 23.125 100.776 24.517 ;
     RECT  11.28 22.885 11.304 24.563 ;
     RECT  27.36 24.469 27.768 24.563 ;
     RECT  42.768 24.371 43.272 24.563 ;
     RECT  77.472 24.421 79.896 24.563 ;
     RECT  44.976 24.469 45.912 24.613 ;
     RECT  106.512 23.411 107.352 24.659 ;
     RECT  61.8 23.747 63.624 24.661 ;
     RECT  59.328 24.469 59.832 24.707 ;
     RECT  7.8 24.469 9.096 24.755 ;
     RECT  94.2 23.411 94.512 24.757 ;
     RECT  71.136 24.469 71.16 24.805 ;
     RECT  44.976 24.613 46.008 24.853 ;
     RECT  50.4 23.747 51.864 24.901 ;
     RECT  47.04 23.027 48.696 24.947 ;
     RECT  27.36 24.563 27.48 24.949 ;
     RECT  61.008 24.661 63.624 24.949 ;
     RECT  71.136 24.805 71.544 25.045 ;
     RECT  72.6 23.267 72.912 25.045 ;
     RECT  88.8 24.515 89.112 25.045 ;
     RECT  102.912 23.029 102.936 25.045 ;
     RECT  26.784 24.949 27.48 25.091 ;
     RECT  60.768 24.949 63.624 25.091 ;
     RECT  99.504 24.517 101.208 25.091 ;
     RECT  102.912 25.045 103.176 25.091 ;
     RECT  34.176 24.421 36.264 25.139 ;
     RECT  66.144 23.891 69.24 25.139 ;
     RECT  71.136 25.045 72.912 25.139 ;
     RECT  7.8 24.755 8.76 25.187 ;
     RECT  16.992 23.941 20.424 25.189 ;
     RECT  39.312 24.373 40.512 25.235 ;
     RECT  47.808 24.947 48.696 25.235 ;
     RECT  54.624 24.131 56.856 25.285 ;
     RECT  58.272 24.131 58.296 25.285 ;
     RECT  66.144 25.139 66.216 25.285 ;
     RECT  36.24 25.139 36.264 25.331 ;
     RECT  65.904 25.285 66.216 25.331 ;
     RECT  59.328 24.707 59.64 25.427 ;
     RECT  67.2 25.139 69.24 25.427 ;
     RECT  44.88 24.853 46.008 25.477 ;
     RECT  69.216 25.427 69.24 25.477 ;
     RECT  11.472 24.709 11.496 25.621 ;
     RECT  43.248 24.563 43.272 25.621 ;
     RECT  44.88 25.477 46.056 25.621 ;
     RECT  61.8 25.091 63.624 25.621 ;
     RECT  92.112 22.499 92.232 25.621 ;
     RECT  50.112 24.901 51.864 25.715 ;
     RECT  83.28 24.181 84.312 25.715 ;
     RECT  13.2 17.123 13.512 25.717 ;
     RECT  85.392 21.155 85.416 25.717 ;
     RECT  88.656 25.045 89.112 25.763 ;
     RECT  71.232 25.139 72.912 25.765 ;
     RECT  54.624 25.285 58.296 25.811 ;
     RECT  43.248 25.621 46.056 25.813 ;
     RECT  34.176 25.139 35.208 25.859 ;
     RECT  16.944 25.189 20.424 26.005 ;
     RECT  21.408 25.573 21.432 26.005 ;
     RECT  54.624 25.811 57.576 26.051 ;
     RECT  85.008 25.717 85.416 26.101 ;
     RECT  27.36 25.091 27.48 26.149 ;
     RECT  103.152 25.091 103.176 26.149 ;
     RECT  102.768 26.149 103.176 26.195 ;
     RECT  71.232 25.765 73.176 26.197 ;
     RECT  74.4 22.739 74.424 26.197 ;
     RECT  65.904 25.331 66.168 26.243 ;
     RECT  69.216 25.477 70.152 26.243 ;
     RECT  85.008 26.101 86.04 26.243 ;
     RECT  91.296 25.621 92.232 26.243 ;
     RECT  61.8 25.621 63.72 26.291 ;
     RECT  43.248 25.813 46.728 26.293 ;
     RECT  27.36 26.149 27.672 26.435 ;
     RECT  93.744 24.757 94.512 26.483 ;
     RECT  31.008 23.891 31.032 26.485 ;
     RECT  102.768 26.195 102.792 26.485 ;
     RECT  63.36 26.291 63.72 26.533 ;
     RECT  85.392 26.243 86.04 26.533 ;
     RECT  42.768 26.293 46.728 26.579 ;
     RECT  80.928 26.437 80.952 26.579 ;
     RECT  85.392 26.533 86.712 26.675 ;
     RECT  102.624 26.485 102.792 26.675 ;
     RECT  83.28 25.715 83.712 26.725 ;
     RECT  14.832 26.005 14.856 26.773 ;
     RECT  33.216 26.245 33.24 26.819 ;
     RECT  85.392 26.675 86.04 26.819 ;
     RECT  93.888 26.483 94.512 26.819 ;
     RECT  99.504 25.091 100.296 26.819 ;
     RECT  102.768 26.675 102.792 26.819 ;
     RECT  71.232 26.197 74.424 26.867 ;
     RECT  34.656 25.859 35.208 26.869 ;
     RECT  22.656 23.941 24.312 26.965 ;
     RECT  22.656 26.965 24.408 27.013 ;
     RECT  99.504 26.819 100.248 27.059 ;
     RECT  30.864 26.485 31.032 27.107 ;
     RECT  54.624 26.051 57.096 27.109 ;
     RECT  71.232 26.867 72.912 27.155 ;
     RECT  97.008 26.773 97.032 27.157 ;
     RECT  22.656 27.013 25.032 27.203 ;
     RECT  28.752 23.891 29.712 27.203 ;
     RECT  63.36 26.533 63.816 27.203 ;
     RECT  86.016 26.819 86.04 27.203 ;
     RECT  40.2 25.235 40.512 27.205 ;
     RECT  50.4 25.715 51.864 27.205 ;
     RECT  16.944 26.005 21.432 27.253 ;
     RECT  14.832 26.773 15.528 27.299 ;
     RECT  22.656 27.203 24.408 27.299 ;
     RECT  96.432 27.157 97.032 27.299 ;
     RECT  10.512 25.621 11.496 27.301 ;
     RECT  13.104 25.717 13.512 27.301 ;
     RECT  99.504 27.059 100.008 27.347 ;
     RECT  43.2 26.579 46.728 27.395 ;
     RECT  50.112 27.205 51.864 27.395 ;
     RECT  94.08 26.819 94.512 27.395 ;
     RECT  34.032 26.869 35.208 27.491 ;
     RECT  54.24 27.109 57.096 27.539 ;
     RECT  82.944 26.725 83.712 27.637 ;
     RECT  82.944 27.637 83.832 27.683 ;
     RECT  43.2 27.395 46.056 27.781 ;
     RECT  66.144 26.243 66.168 27.829 ;
     RECT  67.2 25.427 68.232 27.829 ;
     RECT  66.144 27.829 68.232 27.875 ;
     RECT  10.512 27.301 13.512 27.923 ;
     RECT  42.768 27.781 46.056 28.019 ;
     RECT  14.832 27.299 14.856 28.211 ;
     RECT  39.792 27.205 40.512 28.211 ;
     RECT  71.232 27.155 71.352 28.213 ;
     RECT  55.584 27.539 57.096 28.259 ;
     RECT  7.8 25.187 8.28 28.261 ;
     RECT  12.672 27.923 13.512 28.261 ;
     RECT  29.4 27.203 29.712 28.405 ;
     RECT  30.864 27.107 30.888 28.405 ;
     RECT  34.656 27.491 35.208 28.405 ;
     RECT  50.112 27.395 51.432 28.405 ;
     RECT  70.992 28.213 71.352 28.451 ;
     RECT  107.328 24.659 107.352 28.451 ;
     RECT  16.704 27.253 21.432 28.453 ;
     RECT  60.768 25.091 60.792 28.453 ;
     RECT  102.816 27.877 102.84 28.499 ;
     RECT  34.656 28.405 35.736 28.549 ;
     RECT  97.008 27.299 97.032 28.643 ;
     RECT  83.232 27.683 83.832 28.739 ;
     RECT  15.984 28.453 21.432 28.789 ;
     RECT  15.36 28.789 21.432 28.885 ;
     RECT  54.24 27.539 54.264 28.885 ;
     RECT  55.584 28.259 56.712 28.885 ;
     RECT  91.584 26.243 92.232 28.885 ;
     RECT  15.36 28.885 21.576 28.931 ;
     RECT  12.672 28.261 13.608 28.933 ;
     RECT  91.584 28.885 92.904 28.933 ;
     RECT  99.6 27.347 100.008 28.933 ;
     RECT  50.112 28.405 51.672 28.981 ;
     RECT  88.8 25.763 89.112 28.981 ;
     RECT  21.408 28.931 21.576 29.027 ;
     RECT  60.672 28.453 60.792 29.027 ;
     RECT  43.2 28.019 46.056 29.029 ;
     RECT  72.6 27.155 72.912 29.029 ;
     RECT  74.016 26.867 74.424 29.029 ;
     RECT  15.36 28.931 19.992 29.075 ;
     RECT  72.6 29.029 74.424 29.075 ;
     RECT  90.912 28.933 92.904 29.075 ;
     RECT  99.6 28.933 100.488 29.075 ;
     RECT  15.36 29.075 19.656 29.123 ;
     RECT  83.28 28.739 83.832 29.123 ;
     RECT  91.584 29.075 92.232 29.123 ;
     RECT  54.24 28.885 56.712 29.315 ;
     RECT  66.576 27.875 68.232 29.363 ;
     RECT  69.216 26.243 69.24 29.365 ;
     RECT  70.992 28.451 71.256 29.365 ;
     RECT  88.272 28.981 89.112 29.461 ;
     RECT  83.4 29.123 83.832 29.507 ;
     RECT  27.648 26.435 27.672 29.605 ;
     RECT  10.512 27.923 11.544 29.651 ;
     RECT  33.936 28.549 35.736 29.699 ;
     RECT  43.2 29.029 46.776 29.699 ;
     RECT  59.328 25.427 59.352 29.699 ;
     RECT  49.824 28.981 51.672 29.795 ;
     RECT  54.96 29.315 56.712 29.797 ;
     RECT  94.2 27.395 94.512 29.797 ;
     RECT  98.352 29.029 98.376 29.843 ;
     RECT  40.2 28.211 40.512 29.845 ;
     RECT  43.2 29.699 46.056 29.891 ;
     RECT  36.864 29.509 36.888 29.893 ;
     RECT  104.88 21.011 105.312 30.037 ;
     RECT  66.576 29.363 67.944 30.179 ;
     RECT  72.6 29.075 74.04 30.179 ;
     RECT  22.656 27.299 24.312 30.181 ;
     RECT  29.4 28.405 30.888 30.181 ;
     RECT  92.112 29.123 92.232 30.181 ;
     RECT  88.272 29.461 90.024 30.227 ;
     RECT  21.408 29.027 21.48 30.229 ;
     RECT  60.768 29.027 60.792 30.277 ;
     RECT  61.8 26.291 62.376 30.277 ;
     RECT  54.96 29.797 57.192 30.323 ;
     RECT  74.016 30.179 74.04 30.323 ;
     RECT  88.704 30.227 90.024 30.371 ;
     RECT  26.208 27.061 26.232 30.373 ;
     RECT  27.648 29.605 27.96 30.373 ;
     RECT  11.52 29.651 11.544 30.419 ;
     RECT  34.656 29.699 35.736 30.421 ;
     RECT  36.864 29.893 37.752 30.421 ;
     RECT  54.96 30.323 55.272 30.421 ;
     RECT  15.36 29.123 15.384 30.469 ;
     RECT  26.208 30.373 27.96 30.469 ;
     RECT  29.4 30.181 31.128 30.469 ;
     RECT  26.208 30.469 31.128 30.515 ;
     RECT  14.928 30.469 15.384 30.517 ;
     RECT  16.704 29.123 19.656 30.517 ;
     RECT  99.6 29.075 100.056 30.565 ;
     RECT  14.832 30.517 19.656 30.611 ;
     RECT  34.656 30.421 37.752 30.611 ;
     RECT  78 24.563 79.896 30.611 ;
     RECT  33.024 30.085 33.048 30.613 ;
     RECT  75.792 27.205 75.816 30.613 ;
     RECT  32.784 30.613 33.048 30.659 ;
     RECT  60.768 30.277 62.376 30.659 ;
     RECT  66.576 30.179 67.848 30.659 ;
     RECT  99.6 30.565 100.152 30.707 ;
     RECT  34.656 30.611 36.744 30.709 ;
     RECT  43.2 29.891 44.184 30.755 ;
     RECT  14.832 30.611 14.952 30.757 ;
     RECT  14.784 30.757 14.952 30.803 ;
     RECT  26.208 30.515 27.672 30.803 ;
     RECT  69.216 29.365 71.256 30.803 ;
     RECT  96.336 30.181 96.36 30.803 ;
     RECT  12.528 28.933 13.608 30.851 ;
     RECT  91.296 30.181 92.232 30.851 ;
     RECT  99.6 30.707 100.056 30.851 ;
     RECT  21.12 30.229 21.48 30.899 ;
     RECT  14.784 30.803 14.808 30.947 ;
     RECT  28.896 30.515 31.128 30.947 ;
     RECT  22.656 30.181 24.984 30.949 ;
     RECT  22.656 30.949 25.08 31.139 ;
     RECT  58.944 30.997 58.968 31.139 ;
     RECT  79.632 30.611 79.896 31.139 ;
     RECT  30.864 30.947 31.128 31.235 ;
     RECT  10.512 29.651 10.536 31.331 ;
     RECT  33.792 30.709 36.744 31.379 ;
     RECT  42.192 28.741 42.216 31.379 ;
     RECT  79.872 31.139 79.896 31.379 ;
     RECT  94.2 29.797 94.632 31.379 ;
     RECT  75.792 30.613 76.296 31.381 ;
     RECT  75.456 31.381 76.92 31.427 ;
     RECT  88.8 30.371 90.024 31.427 ;
     RECT  104.88 30.037 105.72 31.427 ;
     RECT  28.896 30.947 29.832 31.667 ;
     RECT  60.768 30.659 60.792 31.717 ;
     RECT  61.8 30.659 62.376 31.717 ;
     RECT  47.808 25.235 47.832 31.765 ;
     RECT  34.656 31.379 36.744 31.861 ;
     RECT  37.728 30.611 37.752 31.861 ;
     RECT  69.216 30.803 69.24 31.861 ;
     RECT  69.12 31.861 69.24 31.907 ;
     RECT  84.96 30.709 84.984 31.907 ;
     RECT  76.896 31.427 76.92 31.955 ;
     RECT  26.208 30.803 26.232 32.005 ;
     RECT  43.2 30.755 43.752 32.051 ;
     RECT  78 30.611 78.408 32.195 ;
     RECT  16.224 30.611 19.656 32.197 ;
     RECT  21.408 30.899 21.48 32.197 ;
     RECT  29.088 31.667 29.832 32.243 ;
     RECT  43.2 32.051 43.512 32.291 ;
     RECT  67.2 30.659 67.8 32.293 ;
     RECT  52.896 23.893 52.92 32.341 ;
     RECT  56.4 30.323 57.192 32.341 ;
     RECT  16.224 32.197 21.48 32.435 ;
     RECT  50.4 29.795 51.672 32.437 ;
     RECT  52.896 32.341 53.016 32.483 ;
     RECT  67.104 32.293 67.8 32.483 ;
     RECT  75.456 31.427 75.816 32.483 ;
     RECT  7.8 28.261 9 32.531 ;
     RECT  47.376 31.765 47.832 32.531 ;
     RECT  54 30.421 55.272 32.531 ;
     RECT  20.88 32.435 21.48 32.533 ;
     RECT  45.6 29.891 46.056 32.533 ;
     RECT  66.096 30.757 66.12 32.533 ;
     RECT  43.2 32.291 43.416 32.627 ;
     RECT  25.68 32.005 26.232 32.629 ;
     RECT  25.68 32.629 26.616 32.771 ;
     RECT  27.648 30.803 27.672 32.771 ;
     RECT  49.728 32.437 51.672 32.771 ;
     RECT  66 32.533 66.12 32.773 ;
     RECT  13.2 30.851 13.608 32.821 ;
     RECT  30.864 31.235 30.888 32.821 ;
     RECT  30.864 32.821 31.32 32.867 ;
     RECT  16.224 32.435 19.656 32.965 ;
     RECT  29.088 32.243 29.712 33.013 ;
     RECT  56.4 32.341 57.24 33.013 ;
     RECT  58.8 32.197 58.824 33.013 ;
     RECT  65.28 32.773 66.12 33.013 ;
     RECT  75.792 32.483 75.816 33.013 ;
     RECT  54 32.531 54.984 33.059 ;
     RECT  20.88 32.533 21.672 33.061 ;
     RECT  22.656 31.139 24.696 33.061 ;
     RECT  47.376 32.531 47.4 33.107 ;
     RECT  65.232 33.013 66.12 33.107 ;
     RECT  39.888 29.845 40.512 33.109 ;
     RECT  45.6 32.533 46.152 33.109 ;
     RECT  20.88 33.061 24.696 33.157 ;
     RECT  25.68 32.771 26.232 33.157 ;
     RECT  74.496 32.965 74.52 33.203 ;
     RECT  39.888 33.109 41.448 33.251 ;
     RECT  60.768 31.717 62.376 33.251 ;
     RECT  60.768 33.251 62.232 33.347 ;
     RECT  67.2 32.483 67.8 33.445 ;
     RECT  20.88 33.157 26.232 33.587 ;
     RECT  67.056 33.445 67.8 33.589 ;
     RECT  69.12 31.907 69.144 33.589 ;
     RECT  105 31.427 105.72 33.589 ;
     RECT  28.128 33.013 29.712 33.635 ;
     RECT  31.296 32.867 31.32 33.635 ;
     RECT  45.024 33.109 46.152 33.635 ;
     RECT  56.4 33.013 58.824 33.635 ;
     RECT  32.784 30.659 32.808 33.731 ;
     RECT  9.984 33.445 10.008 33.781 ;
     RECT  39.936 33.251 41.448 34.021 ;
     RECT  15.456 32.965 19.656 34.067 ;
     RECT  22.848 33.587 26.232 34.115 ;
     RECT  34.656 31.861 37.752 34.115 ;
     RECT  39.936 34.021 41.64 34.163 ;
     RECT  26.16 34.115 26.232 34.165 ;
     RECT  28.8 33.635 29.712 34.165 ;
     RECT  67.056 33.589 69.144 34.165 ;
     RECT  45.072 33.635 46.152 34.355 ;
     RECT  63.36 27.203 63.72 34.357 ;
     RECT  33.408 34.213 33.432 34.453 ;
     RECT  36.72 34.115 37.752 34.499 ;
     RECT  13.2 32.821 13.752 34.501 ;
     RECT  63.264 34.357 63.72 34.547 ;
     RECT  7.8 32.531 8.112 34.597 ;
     RECT  16.368 34.067 19.656 34.643 ;
     RECT  26.16 34.165 26.76 34.691 ;
     RECT  9.264 33.781 10.008 34.741 ;
     RECT  33.408 34.453 33.624 34.741 ;
     RECT  54 33.059 54.792 34.741 ;
     RECT  56.4 33.635 58.056 34.741 ;
     RECT  67.056 34.165 69.528 34.787 ;
     RECT  43.2 32.627 43.368 34.789 ;
     RECT  63.36 34.547 63.72 34.789 ;
     RECT  37.728 34.499 37.752 34.883 ;
     RECT  72.6 30.179 72.912 34.885 ;
     RECT  26.16 34.691 26.52 34.931 ;
     RECT  63.36 34.789 64.104 34.931 ;
     RECT  69.12 34.787 69.528 34.931 ;
     RECT  43.2 34.789 43.8 34.979 ;
     RECT  92.112 30.851 92.232 34.979 ;
     RECT  45.6 34.355 46.152 35.029 ;
     RECT  52.896 32.483 52.92 35.075 ;
     RECT  45.6 35.029 46.728 35.269 ;
     RECT  61.536 33.347 62.232 35.269 ;
     RECT  7.8 34.597 8.232 35.315 ;
     RECT  70.992 30.803 71.256 35.317 ;
     RECT  9.264 34.741 10.056 35.363 ;
     RECT  13.2 34.501 14.28 35.363 ;
     RECT  22.848 34.115 24.984 35.363 ;
     RECT  63.36 34.931 63.384 35.411 ;
     RECT  28.8 34.165 29.928 35.459 ;
     RECT  32.64 34.741 33.624 35.459 ;
     RECT  54 34.741 58.056 35.461 ;
     RECT  61.536 35.269 62.328 35.509 ;
     RECT  65.232 33.107 66.024 35.509 ;
     RECT  39.936 34.163 41.448 35.555 ;
     RECT  53.04 35.461 58.056 35.651 ;
     RECT  64.992 35.509 66.024 35.651 ;
     RECT  65.28 35.651 66.024 35.747 ;
     RECT  53.472 35.651 58.056 35.795 ;
     RECT  60.72 35.509 62.328 35.795 ;
     RECT  36.72 34.499 36.744 35.845 ;
     RECT  37.968 35.461 37.992 35.845 ;
     RECT  33.456 35.459 33.624 35.891 ;
     RECT  9.264 35.363 9.288 35.939 ;
     RECT  16.368 34.643 17.544 35.939 ;
     RECT  45.6 35.269 47.16 35.987 ;
     RECT  105 33.589 106.056 35.989 ;
     RECT  61.584 35.795 62.328 36.035 ;
     RECT  69.12 34.931 69.144 36.083 ;
     RECT  28.8 35.459 29.712 36.229 ;
     RECT  70.176 35.317 71.256 36.275 ;
     RECT  49.728 32.771 51.432 36.323 ;
     RECT  75.792 33.013 76.776 36.323 ;
     RECT  33.456 35.891 33.48 36.469 ;
     RECT  45.6 35.987 46.152 36.469 ;
     RECT  36.72 35.845 37.992 36.515 ;
     RECT  53.472 35.795 54.888 36.515 ;
     RECT  65.28 35.747 65.304 36.515 ;
     RECT  70.176 36.275 71.016 36.515 ;
     RECT  16.368 35.939 16.536 36.563 ;
     RECT  61.584 36.035 62.232 36.563 ;
     RECT  49.728 36.323 49.752 36.565 ;
     RECT  43.2 34.979 43.368 36.611 ;
     RECT  72.48 34.885 72.912 36.659 ;
     RECT  34.656 34.115 35.208 36.755 ;
     RECT  67.056 34.787 67.512 36.805 ;
     RECT  17.52 35.939 17.544 36.851 ;
     RECT  28.704 36.229 29.712 36.851 ;
     RECT  76.752 36.323 76.776 36.851 ;
     RECT  45.504 36.469 46.152 36.853 ;
     RECT  26.16 34.931 26.184 36.899 ;
     RECT  37.968 36.515 37.992 36.899 ;
     RECT  48.912 36.565 49.752 36.899 ;
     RECT  56.4 35.795 58.056 36.899 ;
     RECT  53.472 36.515 54.024 36.901 ;
     RECT  18.6 34.643 19.656 37.043 ;
     RECT  53.376 36.901 54.024 37.043 ;
     RECT  50.736 36.323 51.432 37.091 ;
     RECT  28.8 36.851 29.712 37.139 ;
     RECT  40.032 35.555 41.448 37.283 ;
     RECT  104.304 35.989 106.056 37.379 ;
     RECT  45.408 36.853 46.152 37.381 ;
     RECT  47.136 35.987 47.16 37.381 ;
     RECT  29.088 37.139 29.712 37.427 ;
     RECT  45.408 37.381 47.16 37.427 ;
     RECT  56.4 36.899 57.24 37.427 ;
     RECT  66.144 36.805 67.512 37.427 ;
     RECT  70.704 36.515 71.016 37.427 ;
     RECT  43.344 36.611 43.368 37.477 ;
     RECT  43.344 37.477 43.512 37.523 ;
     RECT  40.032 37.283 40.512 37.571 ;
     RECT  32.64 36.469 33.48 37.667 ;
     RECT  40.08 37.571 40.512 37.667 ;
     RECT  32.784 37.667 33.48 37.811 ;
     RECT  56.4 37.427 57.192 37.859 ;
     RECT  16.368 36.563 16.392 38.003 ;
     RECT  20.88 33.587 21.672 38.147 ;
     RECT  49.728 36.899 49.752 38.147 ;
     RECT  70.704 37.427 70.728 38.147 ;
     RECT  66.432 37.427 67.512 38.149 ;
     RECT  45.408 37.427 46.776 38.195 ;
     RECT  18.6 37.043 19.56 38.291 ;
     RECT  45.408 38.195 46.344 38.291 ;
     RECT  53.376 37.043 53.496 38.341 ;
     RECT  50.784 37.091 51.432 38.389 ;
     RECT  34.704 36.755 35.208 38.435 ;
     RECT  45.6 38.291 46.344 38.483 ;
     RECT  50.592 38.389 51.432 38.483 ;
     RECT  53.376 38.341 54.12 38.483 ;
     RECT  36.72 36.515 36.744 38.675 ;
     RECT  66.432 38.149 67.8 38.725 ;
     RECT  50.592 38.483 51.312 38.771 ;
     RECT  65.904 38.725 67.8 38.771 ;
     RECT  20.88 38.147 20.904 38.819 ;
     RECT  61.68 36.563 62.232 38.819 ;
     RECT  53.376 38.483 53.4 38.867 ;
     RECT  40.2 37.667 40.512 39.061 ;
     RECT  50.784 38.771 51.312 39.107 ;
     RECT  61.8 38.819 62.232 39.107 ;
     RECT  38.784 38.965 38.808 39.109 ;
     RECT  65.904 38.771 67.512 39.155 ;
     RECT  34.8 38.435 35.208 39.203 ;
     RECT  37.824 39.109 38.808 39.251 ;
     RECT  40.2 39.061 41.4 39.251 ;
     RECT  45.6 38.483 46.008 39.253 ;
     RECT  40.2 39.251 41.304 39.347 ;
     RECT  58.56 38.725 58.584 39.347 ;
     RECT  26.784 38.677 26.808 39.395 ;
     RECT  33.456 37.811 33.48 39.395 ;
     RECT  55.344 37.573 55.368 39.395 ;
     RECT  69.024 38.725 69.048 39.395 ;
     RECT  22.848 35.363 24.936 39.587 ;
     RECT  45.504 39.253 46.008 39.779 ;
     RECT  30.912 38.149 30.936 40.019 ;
     RECT  60.384 38.149 60.408 40.019 ;
     RECT  65.904 39.155 65.928 40.067 ;
     RECT  29.136 37.427 29.712 40.261 ;
     RECT  11.088 37.573 11.112 40.307 ;
     RECT  22.848 39.587 24.792 40.307 ;
     RECT  38.784 39.251 38.808 40.307 ;
     RECT  67.104 39.155 67.512 40.307 ;
     RECT  45.504 39.779 45.912 40.451 ;
     RECT  43.488 37.523 43.512 40.499 ;
     RECT  105 37.379 106.056 40.499 ;
     RECT  29.136 40.261 29.832 40.595 ;
     RECT  29.136 40.595 29.712 40.691 ;
     RECT  105 40.499 105.72 40.693 ;
     RECT  18.6 38.291 18.912 40.837 ;
     RECT  18.6 40.837 19.368 40.933 ;
     RECT  92.112 34.979 92.136 41.891 ;
     RECT  22.848 40.307 24.312 42.707 ;
     RECT  22.848 42.707 22.872 42.709 ;
     RECT  22.176 42.709 22.872 42.755 ;
     RECT  104.208 40.693 105.72 44.483 ;
     RECT  104.256 44.483 105.72 46.211 ;
     RECT  107.664 42.901 107.688 46.787 ;
     RECT  105 46.211 105.72 48.421 ;
     RECT  104.4 48.421 105.72 52.405 ;
     RECT  104.4 52.405 106.056 53.123 ;
     RECT  104.4 53.123 105.72 54.131 ;
     RECT  104.544 54.131 105.72 55.237 ;
     RECT  18.432 40.933 19.368 55.763 ;
     RECT  104.448 55.237 105.72 56.293 ;
     RECT  104.448 56.293 105.864 57.443 ;
     RECT  18.432 55.763 18.912 58.693 ;
     RECT  22.176 42.755 22.2 59.699 ;
     RECT  20.496 59.797 20.52 60.275 ;
     RECT  18.336 58.693 18.912 60.997 ;
     RECT  18.336 60.997 19.032 61.187 ;
     RECT  104.448 57.443 105.312 61.189 ;
     RECT  18.336 61.187 18.912 61.283 ;
     RECT  104.448 61.189 106.056 62.243 ;
     RECT  104.448 62.243 105.312 62.435 ;
     RECT  2.4 17.507 2.712 62.649 ;
     RECT  7.8 35.315 8.112 62.649 ;
     RECT  13.2 35.363 13.512 62.649 ;
     RECT  18.6 61.283 18.912 62.649 ;
     RECT  24 42.707 24.312 62.649 ;
     RECT  29.4 40.691 29.712 62.649 ;
     RECT  34.8 39.203 35.112 62.649 ;
     RECT  40.2 39.347 40.512 62.649 ;
     RECT  45.6 40.451 45.912 62.649 ;
     RECT  51 39.107 51.312 62.649 ;
     RECT  56.4 37.859 56.712 62.649 ;
     RECT  61.8 39.107 62.112 62.649 ;
     RECT  67.2 40.307 67.512 62.649 ;
     RECT  72.6 36.659 72.912 62.649 ;
     RECT  78 32.195 78.312 62.649 ;
     RECT  83.4 29.507 83.712 62.649 ;
     RECT  88.8 31.427 89.112 62.649 ;
     RECT  94.2 31.379 94.512 62.649 ;
     RECT  99.6 30.851 99.912 62.649 ;
     RECT  105 62.435 105.312 62.649 ;
     RECT  2.4 62.649 2.52 62.663 ;
     RECT  7.8 62.649 7.92 62.663 ;
     RECT  13.2 62.649 13.32 62.663 ;
     RECT  18.6 62.649 18.72 62.663 ;
     RECT  94.2 62.649 94.32 62.663 ;
     RECT  99.6 62.649 99.72 62.663 ;
     RECT  105 62.649 105.12 62.663 ;
  END
END ot_hgi_coll_fj_n1s0_r256
END LIBRARY
